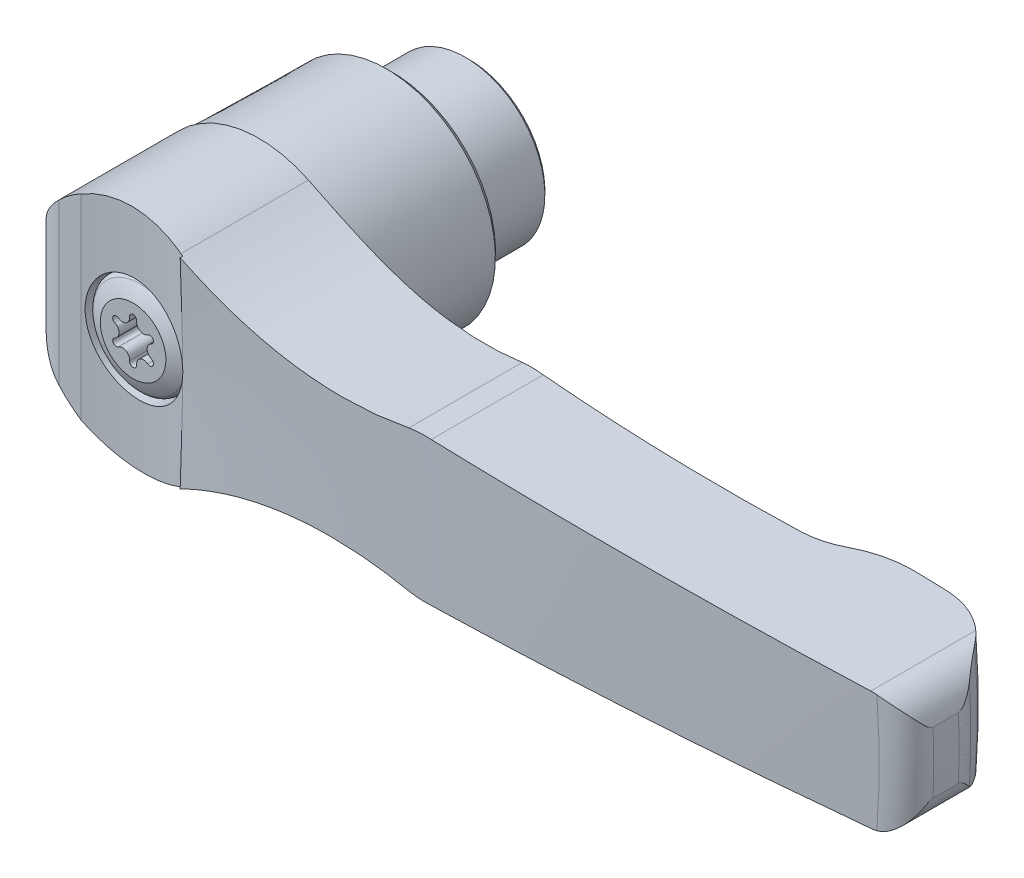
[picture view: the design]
ISO-10303-21;
HEADER;
FILE_DESCRIPTION(('STEP AP214'),'2;1');
FILE_NAME('part.step','',(''),(''),'','','');
FILE_SCHEMA(('AUTOMOTIVE_DESIGN { 1 0 10303 214 1 1 1 1 }'));
ENDSEC;
DATA;
#1=APPLICATION_CONTEXT('core data for automotive mechanical design processes');
#2=APPLICATION_PROTOCOL_DEFINITION('international standard','automotive_design',2000,#1);
#3=PRODUCT_CONTEXT('',#1,'mechanical');
#4=PRODUCT('Part','Part','',(#3));
#5=PRODUCT_RELATED_PRODUCT_CATEGORY('part','',(#4));
#6=PRODUCT_DEFINITION_FORMATION('','',#4);
#7=PRODUCT_DEFINITION_CONTEXT('part definition',#1,'design');
#8=PRODUCT_DEFINITION('design','',#6,#7);
#9=PRODUCT_DEFINITION_SHAPE('','',#8);
#10=(LENGTH_UNIT() NAMED_UNIT(*) SI_UNIT(.MILLI.,.METRE.));
#11=(NAMED_UNIT(*) PLANE_ANGLE_UNIT() SI_UNIT($,.RADIAN.));
#12=(NAMED_UNIT(*) SI_UNIT($,.STERADIAN.) SOLID_ANGLE_UNIT());
#13=UNCERTAINTY_MEASURE_WITH_UNIT(LENGTH_MEASURE(1.E-05),#10,'distance_accuracy_value','');
#14=(GEOMETRIC_REPRESENTATION_CONTEXT(3) GLOBAL_UNCERTAINTY_ASSIGNED_CONTEXT((#13)) GLOBAL_UNIT_ASSIGNED_CONTEXT((#10,
#11,#12)) REPRESENTATION_CONTEXT('',''));
#15=CARTESIAN_POINT('',(0.,0.,0.));
#16=DIRECTION('',(0.,0.,1.));
#17=DIRECTION('',(1.,0.,0.));
#18=AXIS2_PLACEMENT_3D('',#15,#16,#17);
#19=CARTESIAN_POINT('',(0.,0.,28.6698930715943));
#20=DIRECTION('',(0.,0.,1.));
#21=DIRECTION('',(0.,-1.,0.));
#22=AXIS2_PLACEMENT_3D('',#19,#20,#21);
#23=CONICAL_SURFACE('',#22,4.38770360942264,0.0279252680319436);
#24=CARTESIAN_POINT('',(0.,0.,28.6701538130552));
#25=DIRECTION('',(0.,0.,-1.));
#26=DIRECTION('',(0.,1.,0.));
#27=AXIS2_PLACEMENT_3D('',#24,#25,#26);
#28=CIRCLE('',#27,4.38771089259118);
#29=CARTESIAN_POINT('',(4.37640128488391,0.314814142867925,28.6698627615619));
#30=VERTEX_POINT('',#29);
#31=CARTESIAN_POINT('',(4.37640128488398,-0.314814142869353,28.6698627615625));
#32=VERTEX_POINT('',#31);
#33=EDGE_CURVE('E681',#30,#32,#28,.T.);
#34=ORIENTED_EDGE('',*,*,#33,.F.);
#35=CARTESIAN_POINT('',(4.37638813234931,0.314810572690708,28.6696312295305));
#36=CARTESIAN_POINT('',(4.36759225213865,0.436746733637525,28.66825751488));
#37=CARTESIAN_POINT('',(4.35365143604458,0.558298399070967,28.666073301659));
#38=CARTESIAN_POINT('',(4.31565104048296,0.799759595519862,28.6601580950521));
#39=CARTESIAN_POINT('',(4.29159247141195,0.919669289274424,28.6564272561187));
#40=CARTESIAN_POINT('',(4.23356084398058,1.15685508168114,28.6474980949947));
#41=CARTESIAN_POINT('',(4.19959976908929,1.27413418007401,28.6423015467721));
#42=CARTESIAN_POINT('',(4.1220143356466,1.50538038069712,28.6305521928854));
#43=CARTESIAN_POINT('',(4.07838997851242,1.61934748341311,28.6239993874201));
#44=CARTESIAN_POINT('',(3.9818019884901,1.84317559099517,28.6096750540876));
#45=CARTESIAN_POINT('',(3.92883814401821,1.95303650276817,28.6019034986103));
#46=CARTESIAN_POINT('',(3.81394032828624,2.16793056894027,28.5852999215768));
#47=CARTESIAN_POINT('',(3.75200305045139,2.2729619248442,28.5764675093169));
#48=CARTESIAN_POINT('',(3.61964681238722,2.4773951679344,28.5579277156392));
#49=CARTESIAN_POINT('',(3.5492312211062,2.57679926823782,28.5482206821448));
#50=CARTESIAN_POINT('',(3.40037126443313,2.76938620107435,28.5281177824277));
#51=CARTESIAN_POINT('',(3.32192391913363,2.86256670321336,28.5177216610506));
#52=CARTESIAN_POINT('',(3.15690159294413,3.04277004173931,28.4963587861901));
#53=CARTESIAN_POINT('',(3.07026568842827,3.12973662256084,28.485388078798));
#54=CARTESIAN_POINT('',(2.88998825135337,3.29610688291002,28.4631610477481));
#55=CARTESIAN_POINT('',(2.7963441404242,3.37550775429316,28.4519046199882));
#56=CARTESIAN_POINT('',(2.60274956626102,3.52615287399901,28.4293219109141));
#57=CARTESIAN_POINT('',(2.50280041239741,3.59739880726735,28.4179956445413));
#58=CARTESIAN_POINT('',(2.29723122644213,3.7312887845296,28.3954704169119));
#59=CARTESIAN_POINT('',(2.19160910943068,3.79392963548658,28.384271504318));
#60=CARTESIAN_POINT('',(1.97464335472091,3.91058078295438,28.3621157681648));
#61=CARTESIAN_POINT('',(1.86326268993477,3.96452269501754,28.3511613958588));
#62=CARTESIAN_POINT('',(1.63625749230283,4.06283483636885,28.3297617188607));
#63=CARTESIAN_POINT('',(1.52063139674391,4.10720149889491,28.319316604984));
#64=CARTESIAN_POINT('',(1.28603822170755,4.18599718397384,28.2991083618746));
#65=CARTESIAN_POINT('',(1.16707260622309,4.22043048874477,28.2893449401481));
#66=CARTESIAN_POINT('',(0.926553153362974,4.27913923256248,28.2706331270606));
#67=CARTESIAN_POINT('',(0.804998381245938,4.30341093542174,28.2616850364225));
#68=CARTESIAN_POINT('',(0.56050926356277,4.34153901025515,28.2447454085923));
#69=CARTESIAN_POINT('',(0.437579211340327,4.35542170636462,28.2367514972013));
#70=CARTESIAN_POINT('',(0.190912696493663,4.37277111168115,28.221778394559));
#71=CARTESIAN_POINT('',(0.067175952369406,4.37623396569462,28.2147995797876));
#72=CARTESIAN_POINT('',(-0.303814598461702,4.37087373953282,28.1954907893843));
#73=CARTESIAN_POINT('',(-0.551121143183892,4.34634416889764,28.1847695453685));
#74=CARTESIAN_POINT('',(-1.03650636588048,4.2562142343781,28.1678211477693));
#75=CARTESIAN_POINT('',(-1.27463404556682,4.19087822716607,28.1615656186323));
#76=CARTESIAN_POINT('',(-1.73666742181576,4.02119102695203,28.1530588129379));
#77=CARTESIAN_POINT('',(-1.96057336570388,3.91684051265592,28.1508074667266));
#78=CARTESIAN_POINT('',(-2.38718935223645,3.67236312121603,28.1495611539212));
#79=CARTESIAN_POINT('',(-2.58994945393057,3.53232357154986,28.1505583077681));
#80=CARTESIAN_POINT('',(-2.96915676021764,3.22029180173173,28.1547714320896));
#81=CARTESIAN_POINT('',(-3.14560364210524,3.04829918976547,28.1579874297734));
#82=CARTESIAN_POINT('',(-3.46742933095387,2.67692052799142,28.1654937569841));
#83=CARTESIAN_POINT('',(-3.61276071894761,2.4774934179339,28.169785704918));
#84=CARTESIAN_POINT('',(-3.86788705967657,2.05707167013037,28.1783049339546));
#85=CARTESIAN_POINT('',(-3.97768202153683,1.8360770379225,28.1825322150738));
#86=CARTESIAN_POINT('',(-4.15862712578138,1.37869612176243,28.1899517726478));
#87=CARTESIAN_POINT('',(-4.22976508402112,1.14230501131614,28.1931437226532));
#88=CARTESIAN_POINT('',(-4.33129348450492,0.660912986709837,28.1978079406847));
#89=CARTESIAN_POINT('',(-4.36168448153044,0.415912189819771,28.1992802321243));
#90=CARTESIAN_POINT('',(-4.38082304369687,-0.0752514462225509,28.2001998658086));
#91=CARTESIAN_POINT('',(-4.36964881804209,-0.321411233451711,28.1996510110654));
#92=CARTESIAN_POINT('',(-4.30615469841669,-0.808352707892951,28.1966493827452));
#93=CARTESIAN_POINT('',(-4.25383484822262,-1.04913440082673,28.1941966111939));
#94=CARTESIAN_POINT('',(-4.10958617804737,-1.51838976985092,28.1879011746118));
#95=CARTESIAN_POINT('',(-4.01767438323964,-1.74686868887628,28.1840591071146));
#96=CARTESIAN_POINT('',(-3.79686828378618,-2.18518682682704,28.1758300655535));
#97=CARTESIAN_POINT('',(-3.66797348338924,-2.39502579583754,28.1714430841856));
#98=CARTESIAN_POINT('',(-3.37658641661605,-2.79052813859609,28.1631865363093));
#99=CARTESIAN_POINT('',(-3.21403231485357,-2.97614597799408,28.1593179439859));
#100=CARTESIAN_POINT('',(-2.86008476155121,-3.31751162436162,28.1532728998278));
#101=CARTESIAN_POINT('',(-2.66869127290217,-3.47325939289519,28.1510964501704));
#102=CARTESIAN_POINT('',(-2.26239270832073,-3.75056183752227,28.1495386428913));
#103=CARTESIAN_POINT('',(-2.04747487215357,-3.87209782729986,28.1501588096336));
#104=CARTESIAN_POINT('',(-1.60034041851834,-4.07742306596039,28.1550942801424));
#105=CARTESIAN_POINT('',(-1.36812412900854,-4.1612130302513,28.1594095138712));
#106=CARTESIAN_POINT('',(-0.893482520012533,-4.28860890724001,28.1722769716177));
#107=CARTESIAN_POINT('',(-0.651074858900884,-4.33228155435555,28.1808221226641));
#108=CARTESIAN_POINT('',(-0.162434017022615,-4.3784984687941,28.2022857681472));
#109=CARTESIAN_POINT('',(0.0837991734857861,-4.38104263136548,28.2152042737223));
#110=CARTESIAN_POINT('',(0.450557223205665,-4.35410663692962,28.2375786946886));
#111=CARTESIAN_POINT('',(0.572490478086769,-4.33997502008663,28.2455451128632));
#112=CARTESIAN_POINT('',(0.814673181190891,-4.3015689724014,28.262388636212));
#113=CARTESIAN_POINT('',(0.934923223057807,-4.27729821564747,28.271265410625));
#114=CARTESIAN_POINT('',(1.17294984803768,-4.21878135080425,28.2898222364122));
#115=CARTESIAN_POINT('',(1.2907254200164,-4.1845312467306,28.2995026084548));
#116=CARTESIAN_POINT('',(1.52290562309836,-4.10632591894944,28.319522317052));
#117=CARTESIAN_POINT('',(1.63731144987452,-4.0623741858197,28.3298614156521));
#118=CARTESIAN_POINT('',(1.86270011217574,-3.9647705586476,28.3511080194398));
#119=CARTESIAN_POINT('',(1.9736573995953,-3.91106034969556,28.3620186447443));
#120=CARTESIAN_POINT('',(2.19059187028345,-3.79452642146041,28.3841641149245));
#121=CARTESIAN_POINT('',(2.29657083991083,-3.73170600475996,28.3953988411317));
#122=CARTESIAN_POINT('',(2.50289007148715,-3.59735327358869,28.4180046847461));
#123=CARTESIAN_POINT('',(2.60322844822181,-3.52581807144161,28.4293758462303));
#124=CARTESIAN_POINT('',(2.79749365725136,-3.37457510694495,28.4520406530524));
#125=CARTESIAN_POINT('',(2.89142283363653,-3.29487035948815,28.4633343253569));
#126=CARTESIAN_POINT('',(3.07268721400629,-3.12741243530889,28.4856903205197));
#127=CARTESIAN_POINT('',(3.15998858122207,-3.03962244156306,28.4967512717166));
#128=CARTESIAN_POINT('',(3.32684040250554,-2.85696457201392,28.5183655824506));
#129=CARTESIAN_POINT('',(3.40639373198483,-2.76209934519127,28.5289191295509));
#130=CARTESIAN_POINT('',(3.55727025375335,-2.5658447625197,28.5493194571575));
#131=CARTESIAN_POINT('',(3.62858698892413,-2.46445038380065,28.559165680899));
#132=CARTESIAN_POINT('',(3.76236832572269,-2.25595422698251,28.577935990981));
#133=CARTESIAN_POINT('',(3.82483631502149,-2.1488546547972,28.5868604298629));
#134=CARTESIAN_POINT('',(3.94027260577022,-1.9300734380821,28.6035728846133));
#135=CARTESIAN_POINT('',(3.99327497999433,-1.8184100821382,28.6113649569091));
#136=CARTESIAN_POINT('',(4.08964142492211,-1.590970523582,28.6256827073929));
#137=CARTESIAN_POINT('',(4.13300929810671,-1.47519596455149,28.6322088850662));
#138=CARTESIAN_POINT('',(4.20974206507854,-1.24050512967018,28.6438484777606));
#139=CARTESIAN_POINT('',(4.24312178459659,-1.12159379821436,28.6489639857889));
#140=CARTESIAN_POINT('',(4.29969149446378,-0.881370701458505,28.6576807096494));
#141=CARTESIAN_POINT('',(4.32288741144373,-0.760060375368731,28.6612828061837));
#142=CARTESIAN_POINT('',(4.34882803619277,-0.584348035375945,28.6653234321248));
#143=CARTESIAN_POINT('',(4.35574888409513,-0.530548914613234,28.6664035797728));
#144=CARTESIAN_POINT('',(4.36757549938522,-0.422796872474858,28.6682515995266));
#145=CARTESIAN_POINT('',(4.37248393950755,-0.368844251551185,28.6690198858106));
#146=CARTESIAN_POINT('',(4.37638813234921,-0.314810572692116,28.6696312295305));
#147=B_SPLINE_CURVE_WITH_KNOTS('',3,(#35,#36,#37,#38,#39,#40,#41,#42,#43,#44,#45,#46,#47,#48,
#49,#50,#51,#52,#53,#54,#55,#56,#57,#58,#59,#60,#61,#62,#63,#64,#65,#66,#67,#68,#69,#70,#71,#72,
#73,#74,#75,#76,#77,#78,#79,#80,#81,#82,#83,#84,#85,#86,#87,#88,#89,#90,#91,#92,#93,#94,#95,#96,
#97,#98,#99,#100,#101,#102,#103,#104,#105,#106,#107,#108,#109,#110,#111,#112,#113,#114,#115,
#116,#117,#118,#119,#120,#121,#122,#123,#124,#125,#126,#127,#128,#129,#130,#131,#132,#133,#134,
#135,#136,#137,#138,#139,#140,#141,#142,#143,#144,#145,#146),.UNSPECIFIED.,.F.,.F.,(4,2,2,2,2,2,
2,2,2,2,2,2,2,2,2,2,2,2,2,2,2,2,2,2,2,2,2,2,2,2,2,2,2,2,2,2,2,2,2,2,2,2,2,2,2,2,2,2,2,2,2,2,2,2,
2,4),(0.,0.366665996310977,0.733295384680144,1.09948292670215,1.46567041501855,1.83186620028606,
2.19819726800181,2.56438324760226,2.93070558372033,3.30000778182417,3.66944652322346,
4.03880879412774,4.40830775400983,4.78058304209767,5.15299676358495,5.525249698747,
5.89763938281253,6.26908226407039,6.64066255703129,7.38300471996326,8.12058694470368,
8.85815633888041,9.5939380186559,10.3297287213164,11.0666328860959,11.803536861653,
12.540672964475,13.2777990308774,14.0135388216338,14.7492778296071,15.484700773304,
16.220133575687,16.9569296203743,17.6937266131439,18.4309252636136,19.1681099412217,
19.9040660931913,20.6400241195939,21.0086915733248,21.3772255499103,21.7459073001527,
22.1144566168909,22.485285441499,22.855980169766,23.2267980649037,23.59747960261,
23.969941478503,24.342264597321,24.7148776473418,25.08734765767,25.4584486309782,
25.8294028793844,26.1998037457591,26.569988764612,26.732716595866,26.8952275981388),.UNSPECIFIED.);
#148=EDGE_CURVE('E1294',#30,#32,#147,.T.);
#149=ORIENTED_EDGE('',*,*,#148,.T.);
#150=EDGE_LOOP('',(#34,#149));
#151=FACE_BOUND('',#150,.T.);
#152=CARTESIAN_POINT('',(0.,0.,25.5));
#153=DIRECTION('',(0.,0.,-1.));
#154=DIRECTION('',(-1.,0.,0.));
#155=AXIS2_PLACEMENT_3D('',#152,#153,#154);
#156=CIRCLE('',#155,4.29916047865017);
#157=CARTESIAN_POINT('',(-4.29916047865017,0.,25.5));
#158=VERTEX_POINT('',#157);
#159=EDGE_CURVE('E9',#158,#158,#156,.F.);
#160=ORIENTED_EDGE('',*,*,#159,.F.);
#161=EDGE_LOOP('',(#160));
#162=FACE_BOUND('',#161,.T.);
#163=ADVANCED_FACE('F14',(#151,#162),#23,.F.);
#164=CARTESIAN_POINT('',(6.45,0.,0.));
#165=DIRECTION('',(0.,0.,1.));
#166=DIRECTION('',(0.,-1.,0.));
#167=AXIS2_PLACEMENT_3D('',#164,#165,#166);
#168=PLANE('',#167);
#169=CARTESIAN_POINT('',(0.,0.,0.));
#170=DIRECTION('',(0.,0.,1.));
#171=DIRECTION('',(0.,-1.,0.));
#172=AXIS2_PLACEMENT_3D('',#169,#170,#171);
#173=CIRCLE('',#172,4.5);
#174=CARTESIAN_POINT('',(0.,-4.5,0.));
#175=VERTEX_POINT('',#174);
#176=EDGE_CURVE('E23',#175,#175,#173,.T.);
#177=ORIENTED_EDGE('',*,*,#176,.T.);
#178=EDGE_LOOP('',(#177));
#179=FACE_BOUND('',#178,.T.);
#180=CARTESIAN_POINT('',(0.,0.,0.));
#181=DIRECTION('',(0.,0.,1.));
#182=DIRECTION('',(0.,-1.,0.));
#183=AXIS2_PLACEMENT_3D('',#180,#181,#182);
#184=CIRCLE('',#183,6.45000000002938);
#185=CARTESIAN_POINT('',(0.,-6.45000000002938,0.));
#186=VERTEX_POINT('',#185);
#187=EDGE_CURVE('E385',#186,#186,#184,.T.);
#188=ORIENTED_EDGE('',*,*,#187,.F.);
#189=EDGE_LOOP('',(#188));
#190=FACE_BOUND('',#189,.T.);
#191=ADVANCED_FACE('F400',(#179,#190),#168,.F.);
#192=CARTESIAN_POINT('',(0.,0.,0.299999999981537));
#193=DIRECTION('',(0.,0.,1.));
#194=DIRECTION('',(0.,-1.,0.));
#195=AXIS2_PLACEMENT_3D('',#192,#193,#194);
#196=CONICAL_SURFACE('',#195,6.75000000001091,0.785398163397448);
#197=CARTESIAN_POINT('',(0.,0.,0.3));
#198=DIRECTION('',(0.,0.,1.));
#199=DIRECTION('',(0.,-1.,0.));
#200=AXIS2_PLACEMENT_3D('',#197,#198,#199);
#201=CIRCLE('',#200,6.75);
#202=CARTESIAN_POINT('',(0.,-6.75,0.3));
#203=VERTEX_POINT('',#202);
#204=EDGE_CURVE('E381',#203,#203,#201,.T.);
#205=ORIENTED_EDGE('',*,*,#204,.F.);
#206=EDGE_LOOP('',(#205));
#207=FACE_BOUND('',#206,.T.);
#208=ORIENTED_EDGE('',*,*,#187,.T.);
#209=EDGE_LOOP('',(#208));
#210=FACE_BOUND('',#209,.T.);
#211=ADVANCED_FACE('F707',(#207,#210),#196,.T.);
#212=CARTESIAN_POINT('',(0.,0.,0.));
#213=DIRECTION('',(0.,0.,1.));
#214=DIRECTION('',(0.,-1.,0.));
#215=AXIS2_PLACEMENT_3D('',#212,#213,#214);
#216=CYLINDRICAL_SURFACE('',#215,6.75);
#217=CARTESIAN_POINT('',(0.,0.,6.5));
#218=DIRECTION('',(0.,0.,1.));
#219=DIRECTION('',(0.,-1.,0.));
#220=AXIS2_PLACEMENT_3D('',#217,#218,#219);
#221=CIRCLE('',#220,6.75);
#222=CARTESIAN_POINT('',(0.,-6.75,6.5));
#223=VERTEX_POINT('',#222);
#224=EDGE_CURVE('E384',#223,#223,#221,.F.);
#225=ORIENTED_EDGE('',*,*,#224,.T.);
#226=EDGE_LOOP('',(#225));
#227=FACE_BOUND('',#226,.T.);
#228=ORIENTED_EDGE('',*,*,#204,.T.);
#229=EDGE_LOOP('',(#228));
#230=FACE_BOUND('',#229,.T.);
#231=ADVANCED_FACE('F1124',(#227,#230),#216,.T.);
#232=CARTESIAN_POINT('',(8.75,0.,6.5));
#233=DIRECTION('',(0.,0.,1.));
#234=DIRECTION('',(0.,-1.,0.));
#235=AXIS2_PLACEMENT_3D('',#232,#233,#234);
#236=PLANE('',#235);
#237=CARTESIAN_POINT('',(0.,0.,6.5));
#238=DIRECTION('',(0.,0.,1.));
#239=DIRECTION('',(0.,-1.,0.));
#240=AXIS2_PLACEMENT_3D('',#237,#238,#239);
#241=CIRCLE('',#240,8.75);
#242=CARTESIAN_POINT('',(0.,-8.75,6.5));
#243=VERTEX_POINT('',#242);
#244=EDGE_CURVE('E684',#243,#243,#241,.T.);
#245=ORIENTED_EDGE('',*,*,#244,.F.);
#246=EDGE_LOOP('',(#245));
#247=FACE_BOUND('',#246,.T.);
#248=ORIENTED_EDGE('',*,*,#224,.F.);
#249=EDGE_LOOP('',(#248));
#250=FACE_BOUND('',#249,.T.);
#251=ADVANCED_FACE('F1116',(#247,#250),#236,.F.);
#252=CARTESIAN_POINT('',(0.,0.,7.));
#253=DIRECTION('',(0.,0.,1.));
#254=DIRECTION('',(0.,-1.,0.));
#255=AXIS2_PLACEMENT_3D('',#252,#253,#254);
#256=CONICAL_SURFACE('',#255,9.25,0.785398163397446);
#257=CARTESIAN_POINT('',(0.,0.,7.));
#258=DIRECTION('',(0.,0.,1.));
#259=DIRECTION('',(0.,-1.,0.));
#260=AXIS2_PLACEMENT_3D('',#257,#258,#259);
#261=CIRCLE('',#260,9.25);
#262=CARTESIAN_POINT('',(0.,-9.25,6.99999999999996));
#263=VERTEX_POINT('',#262);
#264=EDGE_CURVE('E374',#263,#263,#261,.T.);
#265=ORIENTED_EDGE('',*,*,#264,.F.);
#266=EDGE_LOOP('',(#265));
#267=FACE_BOUND('',#266,.T.);
#268=ORIENTED_EDGE('',*,*,#244,.T.);
#269=EDGE_LOOP('',(#268));
#270=FACE_BOUND('',#269,.T.);
#271=ADVANCED_FACE('F664',(#267,#270),#256,.T.);
#272=CARTESIAN_POINT('',(-9.25,-19.1,7.));
#273=DIRECTION('',(-0.999862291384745,0.,-0.0165951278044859));
#274=DIRECTION('',(0.0165951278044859,0.,-0.999862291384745));
#275=AXIS2_PLACEMENT_3D('',#272,#273,#274);
#276=PLANE('',#275);
#277=CARTESIAN_POINT('',(1.01243252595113E-13,0.,-550.315755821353));
#278=DIRECTION('',(-0.999862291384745,0.,-0.0165951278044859));
#279=DIRECTION('',(-0.0165951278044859,0.,0.999862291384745));
#280=AXIS2_PLACEMENT_3D('',#277,#278,#279);
#281=ELLIPSE('',#280,575.470108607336,9.55);
#282=CARTESIAN_POINT('',(-9.4295477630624,1.51199503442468,17.8178159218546));
#283=VERTEX_POINT('',#282);
#284=CARTESIAN_POINT('',(-9.54958687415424,0.0888286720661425,25.0502146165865));
#285=VERTEX_POINT('',#284);
#286=EDGE_CURVE('E637',#283,#285,#281,.F.);
#287=ORIENTED_EDGE('',*,*,#286,.F.);
#288=CARTESIAN_POINT('',(-9.4295477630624,1.51199503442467,17.8178159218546));
#289=CARTESIAN_POINT('',(-9.42944136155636,1.26003673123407,17.8114051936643));
#290=CARTESIAN_POINT('',(-9.42936147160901,1.00805803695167,17.8065917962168));
#291=CARTESIAN_POINT('',(-9.42925471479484,0.504059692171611,17.8001596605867));
#292=CARTESIAN_POINT('',(-9.42922784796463,0.252040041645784,17.7985409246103));
#293=CARTESIAN_POINT('',(-9.42922749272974,0.,17.798519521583));
#294=B_SPLINE_CURVE_WITH_KNOTS('',3,(#288,#289,#290,#291,#292,#293),.UNSPECIFIED.,.F.,.F.,(4,2,
4),(0.,0.75607402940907,1.51214858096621),.UNSPECIFIED.);
#295=CARTESIAN_POINT('',(-9.42922749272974,0.,17.798519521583));
#296=VERTEX_POINT('',#295);
#297=EDGE_CURVE('E380',#283,#296,#294,.T.);
#298=ORIENTED_EDGE('',*,*,#297,.T.);
#299=CARTESIAN_POINT('',(-9.42922749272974,0.,17.798519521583));
#300=CARTESIAN_POINT('',(-9.42922784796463,-0.252040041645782,17.7985409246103));
#301=CARTESIAN_POINT('',(-9.42925471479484,-0.504059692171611,17.8001596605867));
#302=CARTESIAN_POINT('',(-9.42936147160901,-1.00805803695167,17.8065917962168));
#303=CARTESIAN_POINT('',(-9.42944136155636,-1.26003673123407,17.8114051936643));
#304=CARTESIAN_POINT('',(-9.4295477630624,-1.51199503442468,17.8178159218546));
#305=B_SPLINE_CURVE_WITH_KNOTS('',3,(#299,#300,#301,#302,#303,#304),.UNSPECIFIED.,.F.,.F.,(4,2,
4),(0.,0.756074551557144,1.51214858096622),.UNSPECIFIED.);
#306=CARTESIAN_POINT('',(-9.4295477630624,-1.5119950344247,17.8178159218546));
#307=VERTEX_POINT('',#306);
#308=EDGE_CURVE('E675',#296,#307,#305,.T.);
#309=ORIENTED_EDGE('',*,*,#308,.T.);
#310=CARTESIAN_POINT('',(1.01243252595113E-13,0.,-550.315755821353));
#311=DIRECTION('',(-0.999862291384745,0.,-0.0165951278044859));
#312=DIRECTION('',(-0.0165951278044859,0.,0.999862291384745));
#313=AXIS2_PLACEMENT_3D('',#310,#311,#312);
#314=ELLIPSE('',#313,575.470108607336,9.55);
#315=CARTESIAN_POINT('',(-9.54958687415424,-0.0888286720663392,25.0502146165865));
#316=VERTEX_POINT('',#315);
#317=EDGE_CURVE('E1256',#316,#307,#314,.F.);
#318=ORIENTED_EDGE('',*,*,#317,.F.);
#319=DIRECTION('',(0.,-1.,0.));
#320=VECTOR('',#319,1.);
#321=CARTESIAN_POINT('',(-9.54958687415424,-19.1,25.0502146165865));
#322=LINE('',#321,#320);
#323=EDGE_CURVE('E375',#285,#316,#322,.T.);
#324=ORIENTED_EDGE('',*,*,#323,.F.);
#325=EDGE_LOOP('',(#287,#298,#309,#318,#324));
#326=FACE_BOUND('',#325,.T.);
#327=ADVANCED_FACE('F659',(#326),#276,.T.);
#328=CARTESIAN_POINT('',(-6.69999999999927,-19.1,28.0962476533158));
#329=DIRECTION('',(-0.0601647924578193,0.,0.998188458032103));
#330=DIRECTION('',(-0.998188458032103,0.,-0.0601647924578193));
#331=AXIS2_PLACEMENT_3D('',#328,#329,#330);
#332=PLANE('',#331);
#333=CARTESIAN_POINT('',(0.,0.,28.500083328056));
#334=DIRECTION('',(-0.0601647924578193,0.,0.998188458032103));
#335=DIRECTION('',(0.998188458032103,0.,0.0601647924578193));
#336=AXIS2_PLACEMENT_3D('',#333,#334,#335);
#337=ELLIPSE('',#336,9.56733162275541,9.55);
#338=CARTESIAN_POINT('',(-6.69999999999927,6.80532879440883,28.0962476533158));
#339=VERTEX_POINT('',#338);
#340=CARTESIAN_POINT('',(-4.70000000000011,8.31339280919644,28.2167956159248));
#341=VERTEX_POINT('',#340);
#342=EDGE_CURVE('E648',#339,#341,#337,.F.);
#343=ORIENTED_EDGE('',*,*,#342,.F.);
#344=DIRECTION('',(0.,-1.,0.));
#345=VECTOR('',#344,1.);
#346=CARTESIAN_POINT('',(-6.69999999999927,-19.1,28.0962476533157));
#347=LINE('',#346,#345);
#348=CARTESIAN_POINT('',(-6.69999999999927,-6.80532879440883,28.0962476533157));
#349=VERTEX_POINT('',#348);
#350=EDGE_CURVE('E378',#349,#339,#347,.F.);
#351=ORIENTED_EDGE('',*,*,#350,.F.);
#352=CARTESIAN_POINT('',(0.,0.,28.500083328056));
#353=DIRECTION('',(-0.0601647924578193,0.,0.998188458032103));
#354=DIRECTION('',(0.998188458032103,0.,0.0601647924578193));
#355=AXIS2_PLACEMENT_3D('',#352,#353,#354);
#356=ELLIPSE('',#355,9.56733162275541,9.55);
#357=CARTESIAN_POINT('',(-4.70000000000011,-8.31339280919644,28.2167956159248));
#358=VERTEX_POINT('',#357);
#359=EDGE_CURVE('E1262',#358,#349,#356,.F.);
#360=ORIENTED_EDGE('',*,*,#359,.F.);
#361=DIRECTION('',(0.,-1.,0.));
#362=VECTOR('',#361,1.);
#363=CARTESIAN_POINT('',(-4.70000000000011,-19.1,28.2167956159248));
#364=LINE('',#363,#362);
#365=EDGE_CURVE('E1233',#358,#341,#364,.F.);
#366=ORIENTED_EDGE('',*,*,#365,.T.);
#367=EDGE_LOOP('',(#343,#351,#360,#366));
#368=FACE_BOUND('',#367,.T.);
#369=ADVANCED_FACE('F654',(#368),#332,.T.);
#370=CARTESIAN_POINT('',(-6.55,-19.1,25.1));
#371=DIRECTION('',(0.,-1.,0.));
#372=DIRECTION('',(1.,0.,0.));
#373=AXIS2_PLACEMENT_3D('',#370,#371,#372);
#374=CYLINDRICAL_SURFACE('',#373,3.);
#375=CARTESIAN_POINT('',(-9.55,0.,25.1));
#376=CARTESIAN_POINT('',(-9.55,3.47671001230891E-08,25.1001435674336));
#377=CARTESIAN_POINT('',(-9.54999998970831,0.000424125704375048,25.1002871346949));
#378=CARTESIAN_POINT('',(-9.54999993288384,0.0013735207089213,25.1006836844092));
#379=CARTESIAN_POINT('',(-9.54999986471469,0.00172979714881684,25.1009366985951));
#380=CARTESIAN_POINT('',(-9.54999948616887,0.00320746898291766,25.1018926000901));
#381=CARTESIAN_POINT('',(-9.54999896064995,0.00456206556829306,25.102594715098));
#382=CARTESIAN_POINT('',(-9.54999589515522,0.00980280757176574,25.1053821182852));
#383=CARTESIAN_POINT('',(-9.54999142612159,0.0134222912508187,25.1074690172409));
#384=CARTESIAN_POINT('',(-9.54984305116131,0.0944102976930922,25.154064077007));
#385=CARTESIAN_POINT('',(-9.54871139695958,0.175284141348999,25.1985505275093));
#386=CARTESIAN_POINT('',(-9.5444403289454,0.336150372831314,25.2880374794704));
#387=CARTESIAN_POINT('',(-9.5412756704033,0.41611862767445,25.3330373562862));
#388=CARTESIAN_POINT('',(-9.53306454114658,0.573610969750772,25.4212745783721));
#389=CARTESIAN_POINT('',(-9.52809098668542,0.651117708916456,25.464516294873));
#390=CARTESIAN_POINT('',(-9.51627073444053,0.805689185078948,25.5506915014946));
#391=CARTESIAN_POINT('',(-9.50943037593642,0.882754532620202,25.5936255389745));
#392=CARTESIAN_POINT('',(-9.48445472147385,1.12996192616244,25.7310467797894));
#393=CARTESIAN_POINT('',(-9.46266049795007,1.30002022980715,25.8251235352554));
#394=CARTESIAN_POINT('',(-9.40954494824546,1.64104493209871,26.0124493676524));
#395=CARTESIAN_POINT('',(-9.37814208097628,1.81200629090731,26.1056840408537));
#396=CARTESIAN_POINT('',(-9.31379295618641,2.11521576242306,26.2693440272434));
#397=CARTESIAN_POINT('',(-9.28274317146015,2.24761769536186,26.3402306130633));
#398=CARTESIAN_POINT('',(-9.21483141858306,2.51155601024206,26.4801106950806));
#399=CARTESIAN_POINT('',(-9.1779819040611,2.64309363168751,26.5491078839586));
#400=CARTESIAN_POINT('',(-9.09908481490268,2.90297154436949,26.6837096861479));
#401=CARTESIAN_POINT('',(-9.05714892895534,3.03132520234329,26.7493538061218));
#402=CARTESIAN_POINT('',(-8.96742994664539,3.2872629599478,26.8782580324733));
#403=CARTESIAN_POINT('',(-8.9196441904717,3.41484668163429,26.941517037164));
#404=CARTESIAN_POINT('',(-8.79975726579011,3.71503866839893,27.087578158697));
#405=CARTESIAN_POINT('',(-8.7251146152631,3.88723290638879,27.1691685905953));
#406=CARTESIAN_POINT('',(-8.56416880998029,4.2300744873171,27.3261666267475));
#407=CARTESIAN_POINT('',(-8.4778157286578,4.4007116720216,27.4015454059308));
#408=CARTESIAN_POINT('',(-8.28951988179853,4.74622896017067,27.5472095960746));
#409=CARTESIAN_POINT('',(-8.18707228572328,4.92098334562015,27.6171448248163));
#410=CARTESIAN_POINT('',(-7.96936829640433,5.26623550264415,27.7460103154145));
#411=CARTESIAN_POINT('',(-7.85413022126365,5.43673894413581,27.8049559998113));
#412=CARTESIAN_POINT('',(-7.64561682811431,5.72441551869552,27.8943766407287));
#413=CARTESIAN_POINT('',(-7.55551597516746,5.84286462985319,27.9281691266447));
#414=CARTESIAN_POINT('',(-7.36878441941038,6.07666798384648,27.9877671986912));
#415=CARTESIAN_POINT('',(-7.2721523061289,6.19202155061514,28.0135710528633));
#416=CARTESIAN_POINT('',(-7.0736511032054,6.41781298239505,28.0556686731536));
#417=CARTESIAN_POINT('',(-6.97184621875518,6.52828924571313,28.0720576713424));
#418=CARTESIAN_POINT('',(-6.76252380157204,6.74488219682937,28.0943126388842));
#419=CARTESIAN_POINT('',(-6.65500601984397,6.85099869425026,28.1001781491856));
#420=CARTESIAN_POINT('',(-6.46343795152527,7.03128991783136,28.0998606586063));
#421=CARTESIAN_POINT('',(-6.38048824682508,7.10664323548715,28.0963952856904));
#422=CARTESIAN_POINT('',(-6.21235451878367,7.25407788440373,28.0821322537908));
#423=CARTESIAN_POINT('',(-6.12717105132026,7.32616001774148,28.0713364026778));
#424=CARTESIAN_POINT('',(-5.955080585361,7.46671649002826,28.0417159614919));
#425=CARTESIAN_POINT('',(-5.86817218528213,7.53518771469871,28.0228845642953));
#426=CARTESIAN_POINT('',(-5.69355294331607,7.6679866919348,27.9765732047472));
#427=CARTESIAN_POINT('',(-5.60584224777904,7.73231518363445,27.9490947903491));
#428=CARTESIAN_POINT('',(-5.37383569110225,7.8965468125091,27.8640863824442));
#429=CARTESIAN_POINT('',(-5.22954554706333,7.9926221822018,27.7986060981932));
#430=CARTESIAN_POINT('',(-5.01773611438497,8.12600028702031,27.6804530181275));
#431=CARTESIAN_POINT('',(-4.94788689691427,8.1686799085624,27.6377332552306));
#432=CARTESIAN_POINT('',(-4.8104935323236,8.25033380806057,27.5455968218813));
#433=CARTESIAN_POINT('',(-4.74294828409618,8.28930987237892,27.4961834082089));
#434=CARTESIAN_POINT('',(-4.61056271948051,8.36367281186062,27.3903740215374));
#435=CARTESIAN_POINT('',(-4.54574333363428,8.3990341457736,27.3339338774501));
#436=CARTESIAN_POINT('',(-4.42019774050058,8.46577835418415,27.2145781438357));
#437=CARTESIAN_POINT('',(-4.35946970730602,8.4971630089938,27.1516654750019));
#438=CARTESIAN_POINT('',(-4.24293765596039,8.55594777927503,27.0196895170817));
#439=CARTESIAN_POINT('',(-4.18713404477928,8.58334756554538,26.9506257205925));
#440=CARTESIAN_POINT('',(-4.0812939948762,8.63417541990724,26.806889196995));
#441=CARTESIAN_POINT('',(-4.03125694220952,8.65760391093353,26.7322170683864));
#442=CARTESIAN_POINT('',(-3.90083205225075,8.71748250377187,26.5169917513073));
#443=CARTESIAN_POINT('',(-3.82753078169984,8.7496789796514,26.3708197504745));
#444=CARTESIAN_POINT('',(-3.70530262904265,8.80214203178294,26.0667360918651));
#445=CARTESIAN_POINT('',(-3.6563685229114,8.82241214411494,25.9088279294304));
#446=CARTESIAN_POINT('',(-3.58669946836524,8.85095678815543,25.5936337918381));
#447=CARTESIAN_POINT('',(-3.56475897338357,8.8597453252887,25.4366603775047));
#448=CARTESIAN_POINT('',(-3.54590998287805,8.86730708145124,25.1209897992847));
#449=CARTESIAN_POINT('',(-3.54899880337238,8.86608137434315,24.9622928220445));
#450=CARTESIAN_POINT('',(-3.57992840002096,8.85363637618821,24.6492415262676));
#451=CARTESIAN_POINT('',(-3.60753685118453,8.84251088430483,24.4948604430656));
#452=CARTESIAN_POINT('',(-3.686063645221,8.81006376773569,24.1932781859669));
#453=CARTESIAN_POINT('',(-3.73698074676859,8.7887426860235,24.0460766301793));
#454=CARTESIAN_POINT('',(-3.86017848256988,8.73533137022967,23.7625338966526));
#455=CARTESIAN_POINT('',(-3.93251587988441,8.70321249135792,23.6262228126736));
#456=CARTESIAN_POINT('',(-4.09541934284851,8.62774986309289,23.368444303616));
#457=CARTESIAN_POINT('',(-4.18598535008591,8.5844061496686,23.2469768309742));
#458=CARTESIAN_POINT('',(-4.3835634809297,8.48524049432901,23.0191927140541));
#459=CARTESIAN_POINT('',(-4.49088076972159,8.42917584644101,22.9132473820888));
#460=CARTESIAN_POINT('',(-4.71597947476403,8.30533115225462,22.7212884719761));
#461=CARTESIAN_POINT('',(-4.83376196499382,8.23754990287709,22.6352769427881));
#462=CARTESIAN_POINT('',(-5.08355636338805,8.08595728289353,22.4784048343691));
#463=CARTESIAN_POINT('',(-5.21599086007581,8.0013678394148,22.4089779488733));
#464=CARTESIAN_POINT('',(-5.48298659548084,7.82082800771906,22.2923775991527));
#465=CARTESIAN_POINT('',(-5.61754980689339,7.72486647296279,22.2452261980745));
#466=CARTESIAN_POINT('',(-5.84755511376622,7.55137315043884,22.1816811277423));
#467=CARTESIAN_POINT('',(-5.9434498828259,7.47615707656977,22.1603779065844));
#468=CARTESIAN_POINT('',(-6.13329531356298,7.32121517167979,22.1275201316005));
#469=CARTESIAN_POINT('',(-6.22724527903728,7.24148776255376,22.1159690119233));
#470=CARTESIAN_POINT('',(-6.41225725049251,7.07818317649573,22.1017285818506));
#471=CARTESIAN_POINT('',(-6.50332159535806,6.99460925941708,22.0990319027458));
#472=CARTESIAN_POINT('',(-6.68208625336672,6.82403828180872,22.1015760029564));
#473=CARTESIAN_POINT('',(-6.76978559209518,6.73704024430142,22.1068190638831));
#474=CARTESIAN_POINT('',(-6.97625280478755,6.52414074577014,22.1279597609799));
#475=CARTESIAN_POINT('',(-7.09317594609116,6.39678691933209,22.1473193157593));
#476=CARTESIAN_POINT('',(-7.31887069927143,6.13728311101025,22.1978934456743));
#477=CARTESIAN_POINT('',(-7.42763838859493,6.0051308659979,22.2291136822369));
#478=CARTESIAN_POINT('',(-7.63812605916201,5.73508834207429,22.3020440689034));
#479=CARTESIAN_POINT('',(-7.73972802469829,5.59714403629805,22.3438930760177));
#480=CARTESIAN_POINT('',(-7.93408325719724,5.31805820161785,22.4361903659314));
#481=CARTESIAN_POINT('',(-8.02683920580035,5.176917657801,22.4866360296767));
#482=CARTESIAN_POINT('',(-8.24980156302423,4.81751224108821,22.6229913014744));
#483=CARTESIAN_POINT('',(-8.37426162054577,4.59747182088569,22.7136613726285));
#484=CARTESIAN_POINT('',(-8.60363827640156,4.15243763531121,22.9079226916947));
#485=CARTESIAN_POINT('',(-8.70851443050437,3.92743466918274,23.0115399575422));
#486=CARTESIAN_POINT('',(-8.89364636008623,3.48701966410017,23.2222758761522));
#487=CARTESIAN_POINT('',(-8.97496602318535,3.27179358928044,23.3288567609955));
#488=CARTESIAN_POINT('',(-9.12062405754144,2.84045818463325,23.5478797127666));
#489=CARTESIAN_POINT('',(-9.18506623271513,2.62436297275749,23.6602806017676));
#490=CARTESIAN_POINT('',(-9.26410174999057,2.32097248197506,23.820838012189));
#491=CARTESIAN_POINT('',(-9.28537933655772,2.23431431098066,23.8670103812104));
#492=CARTESIAN_POINT('',(-9.32541816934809,2.06082435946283,23.959993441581));
#493=CARTESIAN_POINT('',(-9.34418091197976,1.97399271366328,24.0068037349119));
#494=CARTESIAN_POINT('',(-9.37958405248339,1.79835785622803,24.1019601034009));
#495=CARTESIAN_POINT('',(-9.39617308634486,1.70955070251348,24.1503179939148));
#496=CARTESIAN_POINT('',(-9.42681937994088,1.53158407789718,24.2476394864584));
#497=CARTESIAN_POINT('',(-9.4408711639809,1.44242425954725,24.296604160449));
#498=CARTESIAN_POINT('',(-9.47029095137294,1.23688333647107,24.4098656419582));
#499=CARTESIAN_POINT('',(-9.48476525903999,1.12044890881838,24.4743078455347));
#500=CARTESIAN_POINT('',(-9.50929003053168,0.888497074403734,24.6031447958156));
#501=CARTESIAN_POINT('',(-9.51937783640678,0.772980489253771,24.6675350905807));
#502=CARTESIAN_POINT('',(-9.5345920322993,0.552299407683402,24.790656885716));
#503=CARTESIAN_POINT('',(-9.54009172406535,0.447168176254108,24.8493594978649));
#504=CARTESIAN_POINT('',(-9.54581598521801,0.288015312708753,24.9386824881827));
#505=CARTESIAN_POINT('',(-9.5473054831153,0.233694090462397,24.9692511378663));
#506=CARTESIAN_POINT('',(-9.54933602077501,0.124477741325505,25.0300231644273));
#507=CARTESIAN_POINT('',(-9.54988855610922,0.0695980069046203,25.0602263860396));
#508=CARTESIAN_POINT('',(-9.54999142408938,0.0134216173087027,25.0925303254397));
#509=CARTESIAN_POINT('',(-9.54999589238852,0.00980484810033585,25.0946165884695));
#510=CARTESIAN_POINT('',(-9.54999895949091,0.00456470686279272,25.0974038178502));
#511=CARTESIAN_POINT('',(-9.54999948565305,0.00320907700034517,25.0981064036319));
#512=CARTESIAN_POINT('',(-9.54999986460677,0.00173053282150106,25.0990629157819));
#513=CARTESIAN_POINT('',(-9.54999993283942,0.00137409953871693,25.0993160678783));
#514=CARTESIAN_POINT('',(-9.54999998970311,0.000424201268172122,25.0997127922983));
#515=CARTESIAN_POINT('',(-9.55,-3.47759051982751E-08,25.0998563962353));
#516=CARTESIAN_POINT('',(-9.55,0.,25.1));
#517=B_SPLINE_CURVE_WITH_KNOTS('',3,(#375,#376,#377,#378,#379,#380,#381,#382,#383,#384,#385,
#386,#387,#388,#389,#390,#391,#392,#393,#394,#395,#396,#397,#398,#399,#400,#401,#402,#403,#404,
#405,#406,#407,#408,#409,#410,#411,#412,#413,#414,#415,#416,#417,#418,#419,#420,#421,#422,#423,
#424,#425,#426,#427,#428,#429,#430,#431,#432,#433,#434,#435,#436,#437,#438,#439,#440,#441,#442,
#443,#444,#445,#446,#447,#448,#449,#450,#451,#452,#453,#454,#455,#456,#457,#458,#459,#460,#461,
#462,#463,#464,#465,#466,#467,#468,#469,#470,#471,#472,#473,#474,#475,#476,#477,#478,#479,#480,
#481,#482,#483,#484,#485,#486,#487,#488,#489,#490,#491,#492,#493,#494,#495,#496,#497,#498,#499,
#500,#501,#502,#503,#504,#505,#506,#507,#508,#509,#510,#511,#512,#513,#514,#515,#516),
.UNSPECIFIED.,.T.,.F.,(4,2,2,2,2,2,2,2,2,2,2,2,2,2,2,2,2,2,2,2,2,2,2,2,2,2,2,2,2,2,2,2,2,2,2,2,
2,2,2,2,2,2,2,2,2,2,2,2,2,2,2,2,2,2,2,2,2,2,2,2,2,2,2,2,2,2,2,2,2,2,4),(0.,0.000880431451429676,
0.00243160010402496,0.00674349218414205,0.0195448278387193,0.292570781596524,0.569054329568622,
0.835444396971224,1.100940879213,1.68733296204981,2.27884620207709,2.73880759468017,
3.19779446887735,3.64808683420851,4.09858470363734,4.7121040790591,5.32832658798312,
5.97060769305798,6.61198053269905,7.06948666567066,7.52709191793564,7.97998303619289,
8.43289390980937,8.76897667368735,9.10497658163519,9.44126169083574,9.77748663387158,
10.3306557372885,10.6073799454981,10.8839699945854,11.1623959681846,11.4406968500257,
11.7190207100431,11.9973149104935,12.4945187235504,12.9915750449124,13.4655162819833,
13.9394066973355,14.4088543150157,14.8782769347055,15.3489548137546,15.8196311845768,
16.3001819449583,16.780782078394,17.2941651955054,17.808055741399,18.1787484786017,
18.54957169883,18.9200862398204,19.2907072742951,19.8118239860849,20.3331897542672,
20.8617526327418,21.3901547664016,22.1945693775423,23.000627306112,23.7606591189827,
24.5159003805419,24.8172874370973,25.1184943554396,25.4258729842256,25.7339072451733,
26.1353797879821,26.5333643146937,26.8944471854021,27.0821321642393,27.2674973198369,
27.2802946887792,27.2846094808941,27.2861614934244,27.2870421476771),.UNSPECIFIED.);
#518=CARTESIAN_POINT('',(-9.55,-2.23035405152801E-07,25.0999998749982));
#519=VERTEX_POINT('',#518);
#520=EDGE_CURVE('E641',#519,#339,#517,.T.);
#521=ORIENTED_EDGE('',*,*,#520,.F.);
#522=CARTESIAN_POINT('',(-6.69999999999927,-6.80532879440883,28.0962476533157));
#523=CARTESIAN_POINT('',(-6.81996946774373,-6.68725177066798,28.0902004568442));
#524=CARTESIAN_POINT('',(-6.93649081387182,-6.56625473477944,28.077190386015));
#525=CARTESIAN_POINT('',(-7.16193168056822,-6.31957018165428,28.0391558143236));
#526=CARTESIAN_POINT('',(-7.27086521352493,-6.19389200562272,28.014154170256));
#527=CARTESIAN_POINT('',(-7.47996613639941,-5.93965552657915,27.9542734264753));
#528=CARTESIAN_POINT('',(-7.58020183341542,-5.81113200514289,27.9194825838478));
#529=CARTESIAN_POINT('',(-7.77288444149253,-5.55076668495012,27.8414168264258));
#530=CARTESIAN_POINT('',(-7.8653262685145,-5.4189227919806,27.7981364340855));
#531=CARTESIAN_POINT('',(-8.08527935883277,-5.08794110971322,27.6816755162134));
#532=CARTESIAN_POINT('',(-8.20806234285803,-4.88717024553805,27.6041723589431));
#533=CARTESIAN_POINT('',(-8.43659039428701,-4.4811559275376,27.4368437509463));
#534=CARTESIAN_POINT('',(-8.54233044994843,-4.27591117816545,27.3470146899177));
#535=CARTESIAN_POINT('',(-8.73776973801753,-3.86092720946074,27.1572579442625));
#536=CARTESIAN_POINT('',(-8.82737926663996,-3.65116970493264,27.0572783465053));
#537=CARTESIAN_POINT('',(-8.99035400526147,-3.22911960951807,26.8498759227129));
#538=CARTESIAN_POINT('',(-9.06372075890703,-3.01682726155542,26.7424538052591));
#539=CARTESIAN_POINT('',(-9.19977329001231,-2.57379717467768,26.5134302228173));
#540=CARTESIAN_POINT('',(-9.26119179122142,-2.34290423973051,26.3913749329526));
#541=CARTESIAN_POINT('',(-9.3662171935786,-1.87961094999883,26.142666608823));
#542=CARTESIAN_POINT('',(-9.40982093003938,-1.64721033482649,26.0160127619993));
#543=CARTESIAN_POINT('',(-9.51423453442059,-0.949863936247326,25.632354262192));
#544=CARTESIAN_POINT('',(-9.54915312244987,-0.483098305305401,25.370765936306));
#545=CARTESIAN_POINT('',(-9.54999492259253,-0.0113662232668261,25.1063705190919));
#546=CARTESIAN_POINT('',(-9.54999999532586,-0.00568305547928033,25.1031852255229));
#547=CARTESIAN_POINT('',(-9.55,0.,25.1));
#548=B_SPLINE_CURVE_WITH_KNOTS('',3,(#522,#523,#524,#525,#526,#527,#528,#529,#530,#531,#532,
#533,#534,#535,#536,#537,#538,#539,#540,#541,#542,#543,#544,#545,#546,#547),.UNSPECIFIED.,.F.,
.F.,(4,2,2,2,2,2,2,2,2,2,2,2,4),(0.,0.504881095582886,1.00880365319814,1.5083210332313,
2.00816177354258,2.75035501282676,3.49276610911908,4.23918622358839,4.98553537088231,
5.78968736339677,6.5939821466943,8.19672773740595,8.21627256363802),.UNSPECIFIED.);
#549=EDGE_CURVE('E309',#349,#519,#548,.T.);
#550=ORIENTED_EDGE('',*,*,#549,.F.);
#551=ORIENTED_EDGE('',*,*,#350,.T.);
#552=EDGE_LOOP('',(#521,#550,#551));
#553=FACE_BOUND('',#552,.T.);
#554=ADVANCED_FACE('F650',(#553),#374,.T.);
#555=CARTESIAN_POINT('',(-6.55,-19.1,25.1));
#556=DIRECTION('',(0.,-1.,0.));
#557=DIRECTION('',(1.,0.,0.));
#558=AXIS2_PLACEMENT_3D('',#555,#556,#557);
#559=CYLINDRICAL_SURFACE('',#558,3.);
#560=CARTESIAN_POINT('',(-9.55,0.,25.1));
#561=CARTESIAN_POINT('',(-9.55000000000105,-0.00370124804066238,25.0979256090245));
#562=CARTESIAN_POINT('',(-9.54999784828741,-0.00740249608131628,25.0958512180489));
#563=CARTESIAN_POINT('',(-9.54998924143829,-0.0148049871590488,25.0917024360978));
#564=CARTESIAN_POINT('',(-9.54998278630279,-0.0185062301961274,25.0896280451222));
#565=CARTESIAN_POINT('',(-9.54996557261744,-0.0259087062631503,25.0854792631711));
#566=CARTESIAN_POINT('',(-9.54995481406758,-0.0296099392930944,25.0834048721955));
#567=CARTESIAN_POINT('',(-9.54992899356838,-0.0370123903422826,25.0792560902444));
#568=CARTESIAN_POINT('',(-9.54991393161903,-0.0407136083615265,25.0771816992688));
#569=CARTESIAN_POINT('',(-9.54987950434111,-0.0481160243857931,25.0730329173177));
#570=CARTESIAN_POINT('',(-9.54986013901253,-0.0518172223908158,25.0709585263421));
#571=CARTESIAN_POINT('',(-9.54981710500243,-0.0592195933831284,25.066809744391));
#572=CARTESIAN_POINT('',(-9.54979343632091,-0.0629207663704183,25.0647353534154));
#573=CARTESIAN_POINT('',(-9.54974179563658,-0.0703230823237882,25.0605865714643));
#574=CARTESIAN_POINT('',(-9.54971382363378,-0.0740242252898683,25.0585121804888));
#575=CARTESIAN_POINT('',(-9.54965357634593,-0.081426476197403,25.0543633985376));
#576=CARTESIAN_POINT('',(-9.54962130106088,-0.0851275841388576,25.0522890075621));
#577=CARTESIAN_POINT('',(-9.54958687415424,-0.0888286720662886,25.0502146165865));
#578=B_SPLINE_CURVE_WITH_KNOTS('',3,(#560,#561,#562,#563,#564,#565,#566,#567,#568,#569,#570,
#571,#572,#573,#574,#575,#576,#577),.UNSPECIFIED.,.F.,.F.,(4,2,2,2,2,2,2,2,4),(0.,
0.0127287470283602,0.0254574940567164,0.0381862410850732,0.0509149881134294,0.0636437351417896,
0.0763724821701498,0.0891012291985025,0.101829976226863),.UNSPECIFIED.);
#579=EDGE_CURVE('E302',#519,#316,#578,.T.);
#580=ORIENTED_EDGE('',*,*,#579,.F.);
#581=CARTESIAN_POINT('',(-9.54958687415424,0.0888286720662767,25.0502146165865));
#582=CARTESIAN_POINT('',(-9.54962130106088,0.08512758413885,25.0522890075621));
#583=CARTESIAN_POINT('',(-9.54965357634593,0.0814264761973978,25.0543633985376));
#584=CARTESIAN_POINT('',(-9.54971382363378,0.0740242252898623,25.0585121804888));
#585=CARTESIAN_POINT('',(-9.54974179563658,0.070323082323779,25.0605865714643));
#586=CARTESIAN_POINT('',(-9.54979343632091,0.0629207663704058,25.0647353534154));
#587=CARTESIAN_POINT('',(-9.54981710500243,0.0592195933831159,25.066809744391));
#588=CARTESIAN_POINT('',(-9.54986013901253,0.0518172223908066,25.0709585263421));
#589=CARTESIAN_POINT('',(-9.54987950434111,0.0481160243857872,25.0730329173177));
#590=CARTESIAN_POINT('',(-9.54991393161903,0.0407136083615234,25.0771816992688));
#591=CARTESIAN_POINT('',(-9.54992899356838,0.0370123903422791,25.0792560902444));
#592=CARTESIAN_POINT('',(-9.54995481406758,0.029609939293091,25.0834048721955));
#593=CARTESIAN_POINT('',(-9.54996557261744,0.0259087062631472,25.0854792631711));
#594=CARTESIAN_POINT('',(-9.54998278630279,0.0185062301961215,25.0896280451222));
#595=CARTESIAN_POINT('',(-9.54998924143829,0.0148049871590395,25.0917024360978));
#596=CARTESIAN_POINT('',(-9.54999784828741,0.00740249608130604,25.0958512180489));
#597=CARTESIAN_POINT('',(-9.55000000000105,0.00370124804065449,25.0979256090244));
#598=CARTESIAN_POINT('',(-9.55,0.,25.1));
#599=B_SPLINE_CURVE_WITH_KNOTS('',3,(#581,#582,#583,#584,#585,#586,#587,#588,#589,#590,#591,
#592,#593,#594,#595,#596,#597,#598),.UNSPECIFIED.,.F.,.F.,(4,2,2,2,2,2,2,2,4),(0.,
0.0127287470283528,0.025457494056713,0.0381862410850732,0.050914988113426,0.0636437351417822,
0.076372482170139,0.0891012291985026,0.101829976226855),.UNSPECIFIED.);
#600=EDGE_CURVE('E640',#285,#519,#599,.T.);
#601=ORIENTED_EDGE('',*,*,#600,.F.);
#602=ORIENTED_EDGE('',*,*,#323,.T.);
#603=EDGE_LOOP('',(#580,#601,#602));
#604=FACE_BOUND('',#603,.T.);
#605=ADVANCED_FACE('F361',(#604),#559,.T.);
#606=CARTESIAN_POINT('',(0.,0.,23.4));
#607=DIRECTION('',(0.,0.,-1.));
#608=DIRECTION('',(0.,1.,0.));
#609=AXIS2_PLACEMENT_3D('',#606,#607,#608);
#610=TOROIDAL_SURFACE('',#609,62.5,2.50000000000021);
#611=CARTESIAN_POINT('',(64.9476609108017,2.60793830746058,23.4));
#612=CARTESIAN_POINT('',(64.9476635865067,2.60791747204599,23.385594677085));
#613=CARTESIAN_POINT('',(64.947502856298,2.60877349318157,23.3712062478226));
#614=CARTESIAN_POINT('',(64.9468772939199,2.61206665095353,23.3426765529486));
#615=CARTESIAN_POINT('',(64.9464137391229,2.61449714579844,23.3285345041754));
#616=CARTESIAN_POINT('',(64.9452204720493,2.6206884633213,23.3009477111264));
#617=CARTESIAN_POINT('',(64.9444979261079,2.62441339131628,23.2874943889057));
#618=CARTESIAN_POINT('',(64.9428130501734,2.63298432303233,23.2609554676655));
#619=CARTESIAN_POINT('',(64.941850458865,2.63783154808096,23.2478702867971));
#620=CARTESIAN_POINT('',(64.9386420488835,2.65373696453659,23.20918343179));
#621=CARTESIAN_POINT('',(64.9360765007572,2.66615397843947,23.1841697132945));
#622=CARTESIAN_POINT('',(64.930257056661,2.69326279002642,23.1354982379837));
#623=CARTESIAN_POINT('',(64.9270020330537,2.70795830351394,23.1118427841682));
#624=CARTESIAN_POINT('',(64.919825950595,2.73911357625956,23.0651153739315));
#625=CARTESIAN_POINT('',(64.9158924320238,2.75560370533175,23.0420658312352));
#626=CARTESIAN_POINT('',(64.9074693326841,2.78954602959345,22.9968322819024));
#627=CARTESIAN_POINT('',(64.9029801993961,2.80699744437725,22.9746475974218));
#628=CARTESIAN_POINT('',(64.8921425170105,2.84753754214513,22.9247915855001));
#629=CARTESIAN_POINT('',(64.8856256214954,2.87083431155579,22.8973268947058));
#630=CARTESIAN_POINT('',(64.8717651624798,2.91808586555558,22.8431803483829));
#631=CARTESIAN_POINT('',(64.8644214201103,2.94204079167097,22.8164986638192));
#632=CARTESIAN_POINT('',(64.8411574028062,3.01457187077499,22.7372790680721));
#633=CARTESIAN_POINT('',(64.8240216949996,3.06374820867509,22.6856446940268));
#634=CARTESIAN_POINT('',(64.786552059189,3.16262479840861,22.5839964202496));
#635=CARTESIAN_POINT('',(64.7662155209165,3.21232544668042,22.5339838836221));
#636=CARTESIAN_POINT('',(64.7225235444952,3.31125530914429,22.4357315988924));
#637=CARTESIAN_POINT('',(64.6991946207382,3.36048500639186,22.3874805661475));
#638=CARTESIAN_POINT('',(64.649378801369,3.45847846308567,22.2922586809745));
#639=CARTESIAN_POINT('',(64.6228949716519,3.50724262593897,22.2452866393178));
#640=CARTESIAN_POINT('',(64.5667171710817,3.60405706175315,22.1526018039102));
#641=CARTESIAN_POINT('',(64.5370250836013,3.65210773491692,22.1068882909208));
#642=CARTESIAN_POINT('',(64.4865991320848,3.72869921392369,22.0343649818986));
#643=CARTESIAN_POINT('',(64.4668945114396,3.75753177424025,22.0071437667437));
#644=CARTESIAN_POINT('',(64.4262368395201,3.8148255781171,21.9531918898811));
#645=CARTESIAN_POINT('',(64.405282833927,3.84328651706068,21.9264616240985));
#646=CARTESIAN_POINT('',(64.3837035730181,3.8715260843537,21.900000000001));
#647=B_SPLINE_CURVE_WITH_KNOTS('',3,(#611,#612,#613,#614,#615,#616,#617,#618,#619,#620,#621,
#622,#623,#624,#625,#626,#627,#628,#629,#630,#631,#632,#633,#634,#635,#636,#637,#638,#639,#640,
#641,#642,#643,#644,#645,#646),.UNSPECIFIED.,.F.,.F.,(4,2,2,2,2,2,2,2,2,2,2,2,2,2,2,2,2,4),(0.,
0.043162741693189,0.0861445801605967,0.128018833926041,0.169938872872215,0.253838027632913,
0.337875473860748,0.423663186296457,0.509382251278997,0.619147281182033,0.728936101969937,
0.948824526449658,1.16889320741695,1.38713161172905,1.60515963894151,1.82306036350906,
1.95587581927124,2.08879405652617),.UNSPECIFIED.);
#648=CARTESIAN_POINT('',(64.9476609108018,2.60793830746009,23.4));
#649=VERTEX_POINT('',#648);
#650=CARTESIAN_POINT('',(64.3837035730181,3.8715260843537,21.9000000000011));
#651=VERTEX_POINT('',#650);
#652=EDGE_CURVE('E618',#649,#651,#647,.T.);
#653=ORIENTED_EDGE('',*,*,#652,.F.);
#654=CARTESIAN_POINT('',(0.,0.,23.4));
#655=DIRECTION('',(0.,0.,1.));
#656=DIRECTION('',(0.,-1.,0.));
#657=AXIS2_PLACEMENT_3D('',#654,#655,#656);
#658=CIRCLE('',#657,65.);
#659=CARTESIAN_POINT('',(64.9476609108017,-2.60793830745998,23.4));
#660=VERTEX_POINT('',#659);
#661=EDGE_CURVE('E369',#660,#649,#658,.T.);
#662=ORIENTED_EDGE('',*,*,#661,.F.);
#663=CARTESIAN_POINT('',(64.3837035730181,-3.87152608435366,21.900000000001));
#664=CARTESIAN_POINT('',(64.4180366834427,-3.82659670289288,21.9421078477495));
#665=CARTESIAN_POINT('',(64.4507897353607,-3.78110226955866,21.9848884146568));
#666=CARTESIAN_POINT('',(64.51320073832,-3.68917940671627,22.071721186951));
#667=CARTESIAN_POINT('',(64.5428577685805,-3.64275070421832,22.1157737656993));
#668=CARTESIAN_POINT('',(64.5991290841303,-3.5491696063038,22.2050638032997));
#669=CARTESIAN_POINT('',(64.6257425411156,-3.50201701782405,22.2503015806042));
#670=CARTESIAN_POINT('',(64.6758790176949,-3.407397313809,22.341773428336));
#671=CARTESIAN_POINT('',(64.6994122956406,-3.35993182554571,22.38800356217));
#672=CARTESIAN_POINT('',(64.7435259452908,-3.26483020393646,22.4816568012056));
#673=CARTESIAN_POINT('',(64.764106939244,-3.21719410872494,22.529079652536));
#674=CARTESIAN_POINT('',(64.8023331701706,-3.12216841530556,22.6252958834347));
#675=CARTESIAN_POINT('',(64.8199798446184,-3.07477870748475,22.6740885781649));
#676=CARTESIAN_POINT('',(64.8431825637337,-3.00748612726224,22.7454166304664));
#677=CARTESIAN_POINT('',(64.8499332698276,-2.98719207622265,22.7671994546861));
#678=CARTESIAN_POINT('',(64.8628729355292,-2.94688678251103,22.8111908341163));
#679=CARTESIAN_POINT('',(64.8690619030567,-2.92687553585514,22.8333993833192));
#680=CARTESIAN_POINT('',(64.8808822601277,-2.88722543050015,22.8783931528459));
#681=CARTESIAN_POINT('',(64.8865122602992,-2.86758759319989,22.9011796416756));
#682=CARTESIAN_POINT('',(64.897179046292,-2.82894454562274,22.9474172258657));
#683=CARTESIAN_POINT('',(64.9022159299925,-2.80993923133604,22.9708682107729));
#684=CARTESIAN_POINT('',(64.9104527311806,-2.77764499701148,23.0125177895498));
#685=CARTESIAN_POINT('',(64.9137924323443,-2.76414027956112,23.0305206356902));
#686=CARTESIAN_POINT('',(64.920103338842,-2.7378797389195,23.0671250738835));
#687=CARTESIAN_POINT('',(64.9230746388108,-2.72512372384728,23.0857265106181));
#688=CARTESIAN_POINT('',(64.928609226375,-2.70069524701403,23.1236399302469));
#689=CARTESIAN_POINT('',(64.9311733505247,-2.68902058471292,23.1429503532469));
#690=CARTESIAN_POINT('',(64.9358433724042,-2.66720979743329,23.1824638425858));
#691=CARTESIAN_POINT('',(64.9379497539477,-2.65707205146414,23.2026659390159));
#692=CARTESIAN_POINT('',(64.9417784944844,-2.63825061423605,23.245853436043));
#693=CARTESIAN_POINT('',(64.9434538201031,-2.62976022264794,23.2689301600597));
#694=CARTESIAN_POINT('',(64.9460154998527,-2.61660407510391,23.3161557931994));
#695=CARTESIAN_POINT('',(64.946905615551,-2.61192009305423,23.3402990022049));
#696=CARTESIAN_POINT('',(64.947449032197,-2.6090565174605,23.3705170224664));
#697=CARTESIAN_POINT('',(64.9475283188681,-2.60863832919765,23.3764008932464));
#698=CARTESIAN_POINT('',(64.9476342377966,-2.60807937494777,23.3881892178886));
#699=CARTESIAN_POINT('',(64.9476608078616,-2.6079389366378,23.3940936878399));
#700=CARTESIAN_POINT('',(64.9476609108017,-2.60793830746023,23.4));
#701=B_SPLINE_CURVE_WITH_KNOTS('',3,(#663,#664,#665,#666,#667,#668,#669,#670,#671,#672,#673,
#674,#675,#676,#677,#678,#679,#680,#681,#682,#683,#684,#685,#686,#687,#688,#689,#690,#691,#692,
#693,#694,#695,#696,#697,#698,#699,#700),.UNSPECIFIED.,.F.,.F.,(4,2,2,2,2,2,2,2,2,2,2,2,2,2,2,2,
2,2,4),(0.,0.211470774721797,0.423004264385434,0.634595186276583,0.845462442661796,
1.05628518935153,1.26700435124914,1.35857909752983,1.45015255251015,1.54194820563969,
1.63372868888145,1.70196621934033,1.77018618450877,1.8382641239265,1.90626975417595,
1.97997982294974,2.05333483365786,2.07102756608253,2.08874115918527),.UNSPECIFIED.);
#702=CARTESIAN_POINT('',(64.3837035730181,-3.87152608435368,21.900000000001));
#703=VERTEX_POINT('',#702);
#704=EDGE_CURVE('E347',#703,#660,#701,.T.);
#705=ORIENTED_EDGE('',*,*,#704,.F.);
#706=CARTESIAN_POINT('',(0.,0.,21.900000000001));
#707=DIRECTION('',(0.,0.,1.));
#708=DIRECTION('',(0.,-1.,0.));
#709=AXIS2_PLACEMENT_3D('',#706,#707,#708);
#710=CIRCLE('',#709,64.5000000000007);
#711=EDGE_CURVE('E371',#651,#703,#710,.F.);
#712=ORIENTED_EDGE('',*,*,#711,.F.);
#713=EDGE_LOOP('',(#653,#662,#705,#712));
#714=FACE_BOUND('',#713,.T.);
#715=ADVANCED_FACE('F355',(#714),#610,.T.);
#716=CARTESIAN_POINT('',(0.,0.,21.900000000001));
#717=DIRECTION('',(0.,0.,1.));
#718=DIRECTION('',(-1.,0.,0.));
#719=AXIS2_PLACEMENT_3D('',#716,#717,#718);
#720=CONICAL_SURFACE('',#719,64.5000000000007,0.628318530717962);
#721=CARTESIAN_POINT('',(0.,0.,19.9732884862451));
#722=DIRECTION('',(0.,0.,-1.));
#723=DIRECTION('',(0.,1.,0.));
#724=AXIS2_PLACEMENT_3D('',#721,#722,#723);
#725=CIRCLE('',#724,63.1001621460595);
#726=CARTESIAN_POINT('',(62.9089199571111,4.9089971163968,19.9732884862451));
#727=VERTEX_POINT('',#726);
#728=CARTESIAN_POINT('',(62.9089199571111,-4.90899711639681,19.9732884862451));
#729=VERTEX_POINT('',#728);
#730=EDGE_CURVE('E1225',#727,#729,#725,.T.);
#731=ORIENTED_EDGE('',*,*,#730,.F.);
#732=CARTESIAN_POINT('',(64.3837035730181,3.87152608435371,21.9000000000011));
#733=CARTESIAN_POINT('',(64.352701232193,3.91209145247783,21.8607575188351));
#734=CARTESIAN_POINT('',(64.3210959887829,3.95131019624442,21.8206322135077));
#735=CARTESIAN_POINT('',(64.2568437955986,4.0271517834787,21.7388312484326));
#736=CARTESIAN_POINT('',(64.2241972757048,4.0637756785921,21.6971562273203));
#737=CARTESIAN_POINT('',(64.1250410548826,4.16980127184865,21.5702567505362));
#738=CARTESIAN_POINT('',(64.0571841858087,4.23552501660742,21.4829926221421));
#739=CARTESIAN_POINT('',(63.9199552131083,4.35695361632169,21.3057351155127));
#740=CARTESIAN_POINT('',(63.8506231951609,4.41279862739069,21.2158054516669));
#741=CARTESIAN_POINT('',(63.7100737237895,4.51642879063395,21.0327880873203));
#742=CARTESIAN_POINT('',(63.6388554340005,4.5642102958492,20.9396989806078));
#743=CARTESIAN_POINT('',(63.4601357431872,4.67368217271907,20.7052502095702));
#744=CARTESIAN_POINT('',(63.3518067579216,4.73086173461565,20.5623985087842));
#745=CARTESIAN_POINT('',(63.1873854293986,4.80568378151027,20.3444987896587));
#746=CARTESIAN_POINT('',(63.1319221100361,4.82890440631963,20.2708137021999));
#747=CARTESIAN_POINT('',(63.0206530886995,4.87166877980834,20.1226286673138));
#748=CARTESIAN_POINT('',(62.9648473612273,4.89121225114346,20.0481286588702));
#749=CARTESIAN_POINT('',(62.9089199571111,4.90899711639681,19.9732884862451));
#750=B_SPLINE_CURVE_WITH_KNOTS('',3,(#732,#733,#734,#735,#736,#737,#738,#739,#740,#741,#742,
#743,#744,#745,#746,#747,#748,#749),.UNSPECIFIED.,.F.,.F.,(4,2,2,2,2,2,2,2,4),(0.,
0.19312803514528,0.386177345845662,0.771470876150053,1.15076079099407,1.53022179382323,
2.09392248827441,2.37917816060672,2.66445533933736),.UNSPECIFIED.);
#751=EDGE_CURVE('E631',#651,#727,#750,.T.);
#752=ORIENTED_EDGE('',*,*,#751,.F.);
#753=ORIENTED_EDGE('',*,*,#711,.T.);
#754=CARTESIAN_POINT('',(62.9089199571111,-4.90899711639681,19.9732884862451));
#755=CARTESIAN_POINT('',(62.9630024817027,-4.89179931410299,20.0456599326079));
#756=CARTESIAN_POINT('',(63.0169726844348,-4.87295596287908,20.1177151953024));
#757=CARTESIAN_POINT('',(63.124616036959,-4.83182750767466,20.2610945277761));
#758=CARTESIAN_POINT('',(63.1782890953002,-4.80954139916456,20.3324183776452));
#759=CARTESIAN_POINT('',(63.3392215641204,-4.73707736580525,20.5457640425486));
#760=CARTESIAN_POINT('',(63.4458714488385,-4.68145647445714,20.6864603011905));
#761=CARTESIAN_POINT('',(63.6533664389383,-4.55612429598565,20.958799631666));
#762=CARTESIAN_POINT('',(63.7542903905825,-4.48685733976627,21.0905862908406));
#763=CARTESIAN_POINT('',(63.9518017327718,-4.33171037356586,21.3470805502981));
#764=CARTESIAN_POINT('',(64.0483992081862,-4.24587177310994,21.4718048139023));
#765=CARTESIAN_POINT('',(64.1834348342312,-4.10819047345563,21.6450407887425));
#766=CARTESIAN_POINT('',(64.2244694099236,-4.06382992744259,21.6975241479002));
#767=CARTESIAN_POINT('',(64.3052216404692,-3.97087451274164,21.800471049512));
#768=CARTESIAN_POINT('',(64.3449294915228,-3.92225497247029,21.8509199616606));
#769=CARTESIAN_POINT('',(64.3837035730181,-3.87152608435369,21.900000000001));
#770=B_SPLINE_CURVE_WITH_KNOTS('',3,(#754,#755,#756,#757,#758,#759,#760,#761,#762,#763,#764,
#765,#766,#767,#768,#769),.UNSPECIFIED.,.F.,.F.,(4,2,2,2,2,2,2,4),(0.,0.275873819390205,
0.551828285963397,1.10639534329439,1.64523513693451,2.18274549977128,2.42273350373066,
2.66421751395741),.UNSPECIFIED.);
#771=EDGE_CURVE('E301',#729,#703,#770,.T.);
#772=ORIENTED_EDGE('',*,*,#771,.F.);
#773=EDGE_LOOP('',(#731,#752,#753,#772));
#774=FACE_BOUND('',#773,.T.);
#775=ADVANCED_FACE('F360',(#774),#720,.T.);
#776=CARTESIAN_POINT('',(0.,0.,17.7985195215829));
#777=DIRECTION('',(0.,0.,1.));
#778=DIRECTION('',(-1.,0.,0.));
#779=AXIS2_PLACEMENT_3D('',#776,#777,#778);
#780=CONICAL_SURFACE('',#779,9.42922749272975,0.0165958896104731);
#781=CARTESIAN_POINT('',(0.,0.,17.798519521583));
#782=DIRECTION('',(0.,0.,-1.));
#783=DIRECTION('',(1.,0.,0.));
#784=AXIS2_PLACEMENT_3D('',#781,#782,#783);
#785=CIRCLE('',#784,9.42922749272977);
#786=EDGE_CURVE('E1450',#296,#296,#785,.T.);
#787=ORIENTED_EDGE('',*,*,#786,.T.);
#788=EDGE_LOOP('',(#787));
#789=FACE_BOUND('',#788,.T.);
#790=ORIENTED_EDGE('',*,*,#264,.T.);
#791=EDGE_LOOP('',(#790));
#792=FACE_BOUND('',#791,.T.);
#793=ADVANCED_FACE('F1076',(#789,#792),#780,.T.);
#794=CARTESIAN_POINT('',(0.,0.,0.));
#795=DIRECTION('',(0.,0.,1.));
#796=DIRECTION('',(0.,-1.,0.));
#797=AXIS2_PLACEMENT_3D('',#794,#795,#796);
#798=CYLINDRICAL_SURFACE('',#797,65.);
#799=ORIENTED_EDGE('',*,*,#661,.T.);
#800=DIRECTION('',(0.,0.,1.));
#801=VECTOR('',#800,1.);
#802=CARTESIAN_POINT('',(64.9476609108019,2.60793830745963,65.));
#803=LINE('',#802,#801);
#804=CARTESIAN_POINT('',(64.9476609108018,2.60793830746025,25.5534224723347));
#805=VERTEX_POINT('',#804);
#806=EDGE_CURVE('E1171',#805,#649,#803,.F.);
#807=ORIENTED_EDGE('',*,*,#806,.F.);
#808=CARTESIAN_POINT('',(0.,0.,25.5534224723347));
#809=DIRECTION('',(0.,0.,-1.));
#810=DIRECTION('',(0.,1.,0.));
#811=AXIS2_PLACEMENT_3D('',#808,#809,#810);
#812=CIRCLE('',#811,65.);
#813=CARTESIAN_POINT('',(64.9476609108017,-2.60793830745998,25.5534224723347));
#814=VERTEX_POINT('',#813);
#815=EDGE_CURVE('E578',#814,#805,#812,.F.);
#816=ORIENTED_EDGE('',*,*,#815,.F.);
#817=DIRECTION('',(0.,0.,1.));
#818=VECTOR('',#817,1.);
#819=CARTESIAN_POINT('',(64.9476609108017,-2.60793830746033,65.));
#820=LINE('',#819,#818);
#821=EDGE_CURVE('E354',#660,#814,#820,.T.);
#822=ORIENTED_EDGE('',*,*,#821,.F.);
#823=EDGE_LOOP('',(#799,#807,#816,#822));
#824=FACE_BOUND('',#823,.T.);
#825=ADVANCED_FACE('F612',(#824),#798,.T.);
#826=CARTESIAN_POINT('',(62.,2.04999999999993,65.));
#827=DIRECTION('',(0.,0.,1.));
#828=DIRECTION('',(0.,-1.,0.));
#829=AXIS2_PLACEMENT_3D('',#826,#827,#828);
#830=CYLINDRICAL_SURFACE('',#829,3.00000000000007);
#831=CARTESIAN_POINT('',(62.0873568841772,5.04872785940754,19.0696484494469));
#832=CARTESIAN_POINT('',(62.1255083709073,5.04761625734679,19.1042945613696));
#833=CARTESIAN_POINT('',(62.1632276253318,5.0457889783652,19.1393895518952));
#834=CARTESIAN_POINT('',(62.2376446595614,5.04080449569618,19.2103202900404));
#835=CARTESIAN_POINT('',(62.2743453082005,5.03765154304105,19.2461533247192));
#836=CARTESIAN_POINT('',(62.346740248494,5.03011627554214,19.3185530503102));
#837=CARTESIAN_POINT('',(62.3824363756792,5.02573638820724,19.3551181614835));
#838=CARTESIAN_POINT('',(62.452836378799,5.01583911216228,19.4289780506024));
#839=CARTESIAN_POINT('',(62.4875411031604,5.01032273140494,19.4662721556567));
#840=CARTESIAN_POINT('',(62.5559569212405,4.9982398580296,19.5415746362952));
#841=CARTESIAN_POINT('',(62.5896682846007,4.99167365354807,19.5795828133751));
#842=CARTESIAN_POINT('',(62.6561238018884,4.97756838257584,19.6563326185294));
#843=CARTESIAN_POINT('',(62.6888668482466,4.970028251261,19.6950750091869));
#844=CARTESIAN_POINT('',(62.7533949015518,4.95404944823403,19.773300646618));
#845=CARTESIAN_POINT('',(62.7851778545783,4.94560900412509,19.8127852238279));
#846=CARTESIAN_POINT('',(62.8477922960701,4.92790019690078,19.8925055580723));
#847=CARTESIAN_POINT('',(62.8786208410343,4.91862956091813,19.9327431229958));
#848=CARTESIAN_POINT('',(62.9089199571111,4.9089971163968,19.9732884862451));
#849=B_SPLINE_CURVE_WITH_KNOTS('',3,(#831,#832,#833,#834,#835,#836,#837,#838,#839,#840,#841,
#842,#843,#844,#845,#846,#847,#848),.UNSPECIFIED.,.F.,.F.,(4,2,2,2,2,2,2,2,4),(0.,
0.154629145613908,0.308766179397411,0.462600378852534,0.616298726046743,0.769954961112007,
0.923780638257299,1.07791493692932,1.23248493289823),.UNSPECIFIED.);
#850=CARTESIAN_POINT('',(62.0873568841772,5.04872785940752,19.0696484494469));
#851=VERTEX_POINT('',#850);
#852=EDGE_CURVE('E626',#851,#727,#849,.T.);
#853=ORIENTED_EDGE('',*,*,#852,.F.);
#854=DIRECTION('',(0.,0.,1.));
#855=VECTOR('',#854,1.);
#856=CARTESIAN_POINT('',(62.0873568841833,5.04872785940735,65.));
#857=LINE('',#856,#855);
#858=CARTESIAN_POINT('',(62.0873568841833,5.04872785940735,27.9810421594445));
#859=VERTEX_POINT('',#858);
#860=EDGE_CURVE('E566',#851,#859,#857,.T.);
#861=ORIENTED_EDGE('',*,*,#860,.T.);
#862=CARTESIAN_POINT('',(62.0873568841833,5.04872785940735,27.9810421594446));
#863=CARTESIAN_POINT('',(62.1686347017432,5.04634957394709,27.9753882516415));
#864=CARTESIAN_POINT('',(62.2495521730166,5.04070117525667,27.9697586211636));
#865=CARTESIAN_POINT('',(62.4106664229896,5.02286415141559,27.9585479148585));
#866=CARTESIAN_POINT('',(62.4908632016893,5.01067552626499,27.9529668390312));
#867=CARTESIAN_POINT('',(62.5706996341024,4.99521678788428,27.9474100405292));
#868=B_SPLINE_CURVE_WITH_KNOTS('',3,(#862,#863,#864,#865,#866,#867),.UNSPECIFIED.,.F.,.F.,(4,2,
4),(0.,0.243928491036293,0.487856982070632),.UNSPECIFIED.);
#869=CARTESIAN_POINT('',(62.5706996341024,4.99521678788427,27.9474100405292));
#870=VERTEX_POINT('',#869);
#871=EDGE_CURVE('E1168',#859,#870,#868,.T.);
#872=ORIENTED_EDGE('',*,*,#871,.T.);
#873=CARTESIAN_POINT('',(64.9476609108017,2.6079383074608,25.5534224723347));
#874=CARTESIAN_POINT('',(64.9476633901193,2.60791924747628,25.567115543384));
#875=CARTESIAN_POINT('',(64.9475121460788,2.60872439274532,25.5807933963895));
#876=CARTESIAN_POINT('',(64.9469231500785,2.6118257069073,25.6079197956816));
#877=CARTESIAN_POINT('',(64.9464865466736,2.61411589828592,25.6213690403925));
#878=CARTESIAN_POINT('',(64.9453615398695,2.61995912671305,25.6476228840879));
#879=CARTESIAN_POINT('',(64.9446796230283,2.62347957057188,25.6604352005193));
#880=CARTESIAN_POINT('',(64.9430887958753,2.63158884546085,25.6857119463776));
#881=CARTESIAN_POINT('',(64.9421796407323,2.63617882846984,25.6981759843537));
#882=CARTESIAN_POINT('',(64.9395348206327,2.6493356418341,25.7303265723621));
#883=CARTESIAN_POINT('',(64.937635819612,2.6586058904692,25.7497103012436));
#884=CARTESIAN_POINT('',(64.9333964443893,2.67872193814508,25.7875829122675));
#885=CARTESIAN_POINT('',(64.9310557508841,2.68956887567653,25.8060711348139));
#886=CARTESIAN_POINT('',(64.9259518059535,2.71253039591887,25.8425782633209));
#887=CARTESIAN_POINT('',(64.9231825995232,2.72466193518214,25.8605855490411));
#888=CARTESIAN_POINT('',(64.9172884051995,2.74971008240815,25.8959677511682));
#889=CARTESIAN_POINT('',(64.9141635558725,2.76262638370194,25.9133429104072));
#890=CARTESIAN_POINT('',(64.906260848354,2.7943187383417,25.9544655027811));
#891=CARTESIAN_POINT('',(64.9013228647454,2.8133662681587,25.9779720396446));
#892=CARTESIAN_POINT('',(64.8908333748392,2.85217711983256,26.0242488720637));
#893=CARTESIAN_POINT('',(64.8852816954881,2.87194064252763,26.0470189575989));
#894=CARTESIAN_POINT('',(64.8677221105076,2.93198956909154,26.1145521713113));
#895=CARTESIAN_POINT('',(64.8548244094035,2.97297303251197,26.1584635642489));
#896=CARTESIAN_POINT('',(64.8267259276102,3.05575343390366,26.2448128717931));
#897=CARTESIAN_POINT('',(64.8115231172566,3.0975510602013,26.2872494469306));
#898=CARTESIAN_POINT('',(64.7788849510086,3.18128754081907,26.3708356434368));
#899=CARTESIAN_POINT('',(64.7614565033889,3.22322558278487,26.4119887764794));
#900=CARTESIAN_POINT('',(64.7243434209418,3.30700057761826,26.4932672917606));
#901=CARTESIAN_POINT('',(64.7046612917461,3.34883759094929,26.5333937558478));
#902=CARTESIAN_POINT('',(64.6630111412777,3.43222426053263,26.6127187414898));
#903=CARTESIAN_POINT('',(64.6410437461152,3.47377399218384,26.6519175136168));
#904=CARTESIAN_POINT('',(64.5833088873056,3.57693614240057,26.7486403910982));
#905=CARTESIAN_POINT('',(64.5461016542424,3.63827581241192,26.805608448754));
#906=CARTESIAN_POINT('',(64.4663740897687,3.75946385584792,26.9173802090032));
#907=CARTESIAN_POINT('',(64.4238520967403,3.81931175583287,26.9721832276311));
#908=CARTESIAN_POINT('',(64.288150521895,3.99586165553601,27.1328878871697));
#909=CARTESIAN_POINT('',(64.1867490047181,4.1097277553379,27.235232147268));
#910=CARTESIAN_POINT('',(63.978123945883,4.30934371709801,27.4121999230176));
#911=CARTESIAN_POINT('',(63.8740630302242,4.39674772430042,27.4886781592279));
#912=CARTESIAN_POINT('',(63.6491822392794,4.55987073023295,27.6286726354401));
#913=CARTESIAN_POINT('',(63.5283720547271,4.63559643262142,27.6921963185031));
#914=CARTESIAN_POINT('',(63.2960215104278,4.75813817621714,27.7910265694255));
#915=CARTESIAN_POINT('',(63.1872866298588,4.80771179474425,27.8294217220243));
#916=CARTESIAN_POINT('',(63.0178784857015,4.87269113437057,27.8763565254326));
#917=CARTESIAN_POINT('',(62.9604184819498,4.89277205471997,27.8902166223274));
#918=CARTESIAN_POINT('',(62.8436641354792,4.92957763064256,27.9140674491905));
#919=CARTESIAN_POINT('',(62.784371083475,4.94630458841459,27.9240608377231));
#920=CARTESIAN_POINT('',(62.6989901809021,4.96755013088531,27.9352970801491));
#921=CARTESIAN_POINT('',(62.6734797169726,4.97354478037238,27.9382621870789));
#922=CARTESIAN_POINT('',(62.6222448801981,4.98487631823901,27.943419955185));
#923=CARTESIAN_POINT('',(62.5965205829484,4.99021342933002,27.9456128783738));
#924=CARTESIAN_POINT('',(62.5706996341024,4.99521678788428,27.9474100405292));
#925=B_SPLINE_CURVE_WITH_KNOTS('',3,(#873,#874,#875,#876,#877,#878,#879,#880,#881,#882,#883,
#884,#885,#886,#887,#888,#889,#890,#891,#892,#893,#894,#895,#896,#897,#898,#899,#900,#901,#902,
#903,#904,#905,#906,#907,#908,#909,#910,#911,#912,#913,#914,#915,#916,#917,#918,#919,#920,#921,
#922,#923,#924),.UNSPECIFIED.,.F.,.F.,(4,2,2,2,2,2,2,2,2,2,2,2,2,2,2,2,2,2,2,2,2,2,2,2,2,4),(0.,
0.0410304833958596,0.0818968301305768,0.121753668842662,0.161653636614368,0.226241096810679,
0.290875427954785,0.356505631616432,0.422110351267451,0.514041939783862,0.605999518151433,
0.790205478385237,0.974574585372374,1.15838472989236,1.34199246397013,1.52555002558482,
1.80016898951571,2.07487402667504,2.62359219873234,3.08988480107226,3.55590873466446,
3.93082088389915,4.11790471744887,4.3048596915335,4.38396069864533,4.46303483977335),.UNSPECIFIED.);
#926=EDGE_CURVE('E592',#805,#870,#925,.T.);
#927=ORIENTED_EDGE('',*,*,#926,.F.);
#928=ORIENTED_EDGE('',*,*,#806,.T.);
#929=ORIENTED_EDGE('',*,*,#652,.T.);
#930=ORIENTED_EDGE('',*,*,#751,.T.);
#931=EDGE_LOOP('',(#853,#861,#872,#927,#928,#929,#930));
#932=FACE_BOUND('',#931,.T.);
#933=ADVANCED_FACE('F606',(#932),#830,.T.);
#934=CARTESIAN_POINT('',(0.,0.,65.));
#935=DIRECTION('',(0.,0.,1.));
#936=DIRECTION('',(0.,-1.,0.));
#937=AXIS2_PLACEMENT_3D('',#934,#935,#936);
#938=CYLINDRICAL_SURFACE('',#937,9.55);
#939=DIRECTION('',(0.,0.,1.));
#940=VECTOR('',#939,1.);
#941=CARTESIAN_POINT('',(4.2000000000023,8.57685839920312,65.));
#942=LINE('',#941,#940);
#943=CARTESIAN_POINT('',(4.2000000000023,8.57685839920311,28.6423805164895));
#944=VERTEX_POINT('',#943);
#945=CARTESIAN_POINT('',(4.20000000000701,8.5768583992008,17.8178159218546));
#946=VERTEX_POINT('',#945);
#947=EDGE_CURVE('E554',#944,#946,#942,.F.);
#948=ORIENTED_EDGE('',*,*,#947,.T.);
#949=CARTESIAN_POINT('',(0.,0.,17.8178159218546));
#950=DIRECTION('',(0.,0.,1.));
#951=DIRECTION('',(-1.,0.,0.));
#952=AXIS2_PLACEMENT_3D('',#949,#950,#951);
#953=CIRCLE('',#952,9.55);
#954=EDGE_CURVE('E1452',#946,#283,#953,.T.);
#955=ORIENTED_EDGE('',*,*,#954,.T.);
#956=ORIENTED_EDGE('',*,*,#286,.T.);
#957=ORIENTED_EDGE('',*,*,#600,.T.);
#958=ORIENTED_EDGE('',*,*,#520,.T.);
#959=ORIENTED_EDGE('',*,*,#342,.T.);
#960=CARTESIAN_POINT('',(-4.70000000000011,8.31339280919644,28.2167956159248));
#961=CARTESIAN_POINT('',(-4.47062989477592,8.4431012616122,28.2040017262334));
#962=CARTESIAN_POINT('',(-4.23579339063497,8.56330633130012,28.1927729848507));
#963=CARTESIAN_POINT('',(-3.75686557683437,8.78395289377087,28.1739395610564));
#964=CARTESIAN_POINT('',(-3.51277401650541,8.88439385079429,28.1663349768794));
#965=CARTESIAN_POINT('',(-3.0174799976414,9.06458335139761,28.1552545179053));
#966=CARTESIAN_POINT('',(-2.7662913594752,9.1443694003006,28.1517711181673));
#967=CARTESIAN_POINT('',(-2.25816922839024,9.28291460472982,28.1492727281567));
#968=CARTESIAN_POINT('',(-2.0012359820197,9.34167466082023,28.1502575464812));
#969=CARTESIAN_POINT('',(-1.48313785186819,9.43781252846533,28.1569537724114));
#970=CARTESIAN_POINT('',(-1.22196822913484,9.47516441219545,28.1626708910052));
#971=CARTESIAN_POINT('',(-0.697584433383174,9.52813313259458,28.1789660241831));
#972=CARTESIAN_POINT('',(-0.434370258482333,9.54374994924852,28.1895440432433));
#973=CARTESIAN_POINT('',(0.0922303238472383,9.55318541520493,28.2155568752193));
#974=CARTESIAN_POINT('',(0.355616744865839,9.54700206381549,28.2309921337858));
#975=CARTESIAN_POINT('',(0.880648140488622,9.51294675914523,28.2665804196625));
#976=CARTESIAN_POINT('',(1.14229322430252,9.48507617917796,28.286733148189));
#977=CARTESIAN_POINT('',(1.64525649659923,9.41042201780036,28.3300452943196));
#978=CARTESIAN_POINT('',(1.88679798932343,9.36497305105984,28.3529272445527));
#979=CARTESIAN_POINT('',(2.36531448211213,9.25570200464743,28.4022703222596));
#980=CARTESIAN_POINT('',(2.60228954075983,9.19188016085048,28.4287314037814));
#981=CARTESIAN_POINT('',(3.0704099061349,9.04627986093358,28.4848540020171));
#982=CARTESIAN_POINT('',(3.3015518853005,8.9644914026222,28.514517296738));
#983=CARTESIAN_POINT('',(3.75655851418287,8.78355292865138,28.5765447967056));
#984=CARTESIAN_POINT('',(3.98042333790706,8.68440332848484,28.6089089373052));
#985=CARTESIAN_POINT('',(4.20000000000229,8.57685839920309,28.6423805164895));
#986=B_SPLINE_CURVE_WITH_KNOTS('',3,(#960,#961,#962,#963,#964,#965,#966,#967,#968,#969,#970,
#971,#972,#973,#974,#975,#976,#977,#978,#979,#980,#981,#982,#983,#984,#985),.UNSPECIFIED.,.F.,
.F.,(4,2,2,2,2,2,2,2,2,2,2,2,4),(0.,0.79122391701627,1.58246927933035,2.37226765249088,
3.16203219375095,3.95275122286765,4.74347098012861,5.53426330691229,6.32500556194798,
7.0647878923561,7.80456072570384,8.54474644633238,9.28491445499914),.UNSPECIFIED.);
#987=EDGE_CURVE('E1239',#341,#944,#986,.T.);
#988=ORIENTED_EDGE('',*,*,#987,.T.);
#989=EDGE_LOOP('',(#948,#955,#956,#957,#958,#959,#988));
#990=FACE_BOUND('',#989,.T.);
#991=ADVANCED_FACE('F611',(#990),#938,.T.);
#992=CARTESIAN_POINT('',(-2.30000000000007,-19.1,71.3000000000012));
#993=DIRECTION('',(0.,-1.,0.));
#994=DIRECTION('',(1.,0.,0.));
#995=AXIS2_PLACEMENT_3D('',#992,#993,#994);
#996=CYLINDRICAL_SURFACE('',#995,43.1500000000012);
#997=ORIENTED_EDGE('',*,*,#148,.F.);
#998=DIRECTION('',(0.,-1.,0.));
#999=VECTOR('',#998,1.);
#1000=CARTESIAN_POINT('',(4.37639516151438,8.49051827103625,28.6696323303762));
#1001=LINE('',#1000,#999);
#1002=CARTESIAN_POINT('',(4.37639515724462,8.49051826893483,28.6696323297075));
#1003=VERTEX_POINT('',#1002);
#1004=EDGE_CURVE('E553',#1003,#30,#1001,.T.);
#1005=ORIENTED_EDGE('',*,*,#1004,.F.);
#1006=CARTESIAN_POINT('',(4.37639515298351,8.49051827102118,28.6696323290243));
#1007=CARTESIAN_POINT('',(4.34695885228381,8.50481101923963,28.6650223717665));
#1008=CARTESIAN_POINT('',(4.31754110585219,8.51915240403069,28.6604464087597));
#1009=CARTESIAN_POINT('',(4.25874272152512,8.547932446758,28.6513624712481));
#1010=CARTESIAN_POINT('',(4.22936208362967,8.56237110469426,28.6468544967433));
#1011=CARTESIAN_POINT('',(4.2000000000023,8.57685839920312,28.6423805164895));
#1012=B_SPLINE_CURVE_WITH_KNOTS('',3,(#1006,#1007,#1008,#1009,#1010,#1011),.UNSPECIFIED.,.F.,
.F.,(4,2,4),(0.,0.0991371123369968,0.198274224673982),.UNSPECIFIED.);
#1013=EDGE_CURVE('E557',#1003,#944,#1012,.T.);
#1014=ORIENTED_EDGE('',*,*,#1013,.T.);
#1015=ORIENTED_EDGE('',*,*,#987,.F.);
#1016=ORIENTED_EDGE('',*,*,#365,.F.);
#1017=CARTESIAN_POINT('',(4.20000000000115,-8.57685839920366,28.6423805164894));
#1018=CARTESIAN_POINT('',(3.96298924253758,-8.69294838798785,28.6062473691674));
#1019=CARTESIAN_POINT('',(3.72097660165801,-8.79925096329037,28.5714091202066));
#1020=CARTESIAN_POINT('',(3.2285761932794,-8.99158139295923,28.5049226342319));
#1021=CARTESIAN_POINT('',(2.97818764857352,-9.07760735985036,28.4732746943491));
#1022=CARTESIAN_POINT('',(2.47095556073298,-9.22858935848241,28.4138049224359));
#1023=CARTESIAN_POINT('',(2.2141185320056,-9.29356579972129,28.3859793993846));
#1024=CARTESIAN_POINT('',(1.69553653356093,-9.40201114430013,28.334594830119));
#1025=CARTESIAN_POINT('',(1.43379185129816,-9.44548130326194,28.3110355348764));
#1026=CARTESIAN_POINT('',(0.906801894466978,-9.51056314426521,28.2685124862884));
#1027=CARTESIAN_POINT('',(0.641551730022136,-9.53214007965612,28.2495560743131));
#1028=CARTESIAN_POINT('',(0.109873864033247,-9.55307303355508,28.2165235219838));
#1029=CARTESIAN_POINT('',(-0.156553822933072,-9.55242932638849,28.2024473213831));
#1030=CARTESIAN_POINT('',(-0.688540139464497,-9.52886560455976,28.179279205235));
#1031=CARTESIAN_POINT('',(-0.954099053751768,-9.50595382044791,28.1701854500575));
#1032=CARTESIAN_POINT('',(-1.4824771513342,-9.43799234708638,28.1569358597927));
#1033=CARTESIAN_POINT('',(-1.74529656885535,-9.39294456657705,28.1527795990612));
#1034=CARTESIAN_POINT('',(-2.24146544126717,-9.28635866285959,28.1493956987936));
#1035=CARTESIAN_POINT('',(-2.47523929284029,-9.22679771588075,28.1497366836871));
#1036=CARTESIAN_POINT('',(-2.93757271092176,-9.09017436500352,28.1540911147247));
#1037=CARTESIAN_POINT('',(-3.16613254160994,-9.01311284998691,28.1581043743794));
#1038=CARTESIAN_POINT('',(-3.61693408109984,-8.84185864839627,28.1695117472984));
#1039=CARTESIAN_POINT('',(-3.83916866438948,-8.74764746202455,28.1769095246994));
#1040=CARTESIAN_POINT('',(-4.27579202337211,-8.54273752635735,28.1947015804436));
#1041=CARTESIAN_POINT('',(-4.49018040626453,-8.4320379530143,28.2050960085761));
#1042=CARTESIAN_POINT('',(-4.70000000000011,-8.31339280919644,28.2167956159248));
#1043=B_SPLINE_CURVE_WITH_KNOTS('',3,(#1017,#1018,#1019,#1020,#1021,#1022,#1023,#1024,#1025,
#1026,#1027,#1028,#1029,#1030,#1031,#1032,#1033,#1034,#1035,#1036,#1037,#1038,#1039,#1040,#1041,
#1042),.UNSPECIFIED.,.F.,.F.,(4,2,2,2,2,2,2,2,2,2,2,2,4),(0.,0.798917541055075,1.59790942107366,
2.39612426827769,3.19429250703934,3.99372554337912,4.79314871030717,5.59227651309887,
6.3913354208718,7.1143549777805,7.83733781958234,8.56110523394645,9.28490883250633),.UNSPECIFIED.);
#1044=CARTESIAN_POINT('',(4.20000000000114,-8.57685839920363,28.6423805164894));
#1045=VERTEX_POINT('',#1044);
#1046=EDGE_CURVE('E1263',#1045,#358,#1043,.T.);
#1047=ORIENTED_EDGE('',*,*,#1046,.F.);
#1048=CARTESIAN_POINT('',(4.37639515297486,-8.49051827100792,28.6696323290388));
#1049=CARTESIAN_POINT('',(4.3469588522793,-8.50481101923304,28.6650223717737));
#1050=CARTESIAN_POINT('',(4.31754110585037,-8.51915240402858,28.660446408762));
#1051=CARTESIAN_POINT('',(4.25874272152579,-8.54793244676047,28.6513624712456));
#1052=CARTESIAN_POINT('',(4.22936208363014,-8.56237110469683,28.6468544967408));
#1053=CARTESIAN_POINT('',(4.20000000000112,-8.5768583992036,28.6423805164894));
#1054=B_SPLINE_CURVE_WITH_KNOTS('',3,(#1048,#1049,#1050,#1051,#1052,#1053),.UNSPECIFIED.,.F.,
.F.,(4,2,4),(0.,0.0991371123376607,0.198274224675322),.UNSPECIFIED.);
#1055=CARTESIAN_POINT('',(4.37639515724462,-8.49051826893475,28.6696323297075));
#1056=VERTEX_POINT('',#1055);
#1057=EDGE_CURVE('E1240',#1056,#1045,#1054,.T.);
#1058=ORIENTED_EDGE('',*,*,#1057,.F.);
#1059=DIRECTION('',(0.,-1.,0.));
#1060=VECTOR('',#1059,1.);
#1061=CARTESIAN_POINT('',(4.37639516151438,-0.314814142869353,28.6696323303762));
#1062=LINE('',#1061,#1060);
#1063=EDGE_CURVE('E552',#32,#1056,#1062,.T.);
#1064=ORIENTED_EDGE('',*,*,#1063,.F.);
#1065=EDGE_LOOP('',(#997,#1005,#1014,#1015,#1016,#1047,#1058,#1064));
#1066=FACE_BOUND('',#1065,.T.);
#1067=ADVANCED_FACE('F1053',(#1066),#996,.F.);
#1068=CARTESIAN_POINT('',(0.,0.,65.));
#1069=DIRECTION('',(0.,0.,1.));
#1070=DIRECTION('',(0.,-1.,0.));
#1071=AXIS2_PLACEMENT_3D('',#1068,#1069,#1070);
#1072=CYLINDRICAL_SURFACE('',#1071,9.55);
#1073=ORIENTED_EDGE('',*,*,#549,.T.);
#1074=ORIENTED_EDGE('',*,*,#579,.T.);
#1075=ORIENTED_EDGE('',*,*,#317,.T.);
#1076=CARTESIAN_POINT('',(0.,0.,17.8178159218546));
#1077=DIRECTION('',(0.,0.,1.));
#1078=DIRECTION('',(-1.,0.,0.));
#1079=AXIS2_PLACEMENT_3D('',#1076,#1077,#1078);
#1080=CIRCLE('',#1079,9.55);
#1081=CARTESIAN_POINT('',(4.19999999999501,-8.57685839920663,17.8178159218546));
#1082=VERTEX_POINT('',#1081);
#1083=EDGE_CURVE('E1353',#307,#1082,#1080,.T.);
#1084=ORIENTED_EDGE('',*,*,#1083,.T.);
#1085=DIRECTION('',(0.,0.,1.));
#1086=VECTOR('',#1085,1.);
#1087=CARTESIAN_POINT('',(4.20000000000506,-8.57685839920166,65.));
#1088=LINE('',#1087,#1086);
#1089=EDGE_CURVE('E545',#1082,#1045,#1088,.T.);
#1090=ORIENTED_EDGE('',*,*,#1089,.T.);
#1091=ORIENTED_EDGE('',*,*,#1046,.T.);
#1092=ORIENTED_EDGE('',*,*,#359,.T.);
#1093=EDGE_LOOP('',(#1073,#1074,#1075,#1084,#1090,#1091,#1092));
#1094=FACE_BOUND('',#1093,.T.);
#1095=ADVANCED_FACE('F322',(#1094),#1072,.T.);
#1096=CARTESIAN_POINT('',(62.,-2.04999999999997,65.));
#1097=DIRECTION('',(0.,0.,1.));
#1098=DIRECTION('',(0.,-1.,0.));
#1099=AXIS2_PLACEMENT_3D('',#1096,#1097,#1098);
#1100=CYLINDRICAL_SURFACE('',#1099,3.);
#1101=ORIENTED_EDGE('',*,*,#821,.T.);
#1102=CARTESIAN_POINT('',(62.5706996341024,-4.99521678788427,27.9474100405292));
#1103=CARTESIAN_POINT('',(62.635563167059,-4.98266332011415,27.9429062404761));
#1104=CARTESIAN_POINT('',(62.6998016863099,-4.96797815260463,27.9358857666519));
#1105=CARTESIAN_POINT('',(62.8264657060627,-4.93465124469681,27.9172170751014));
#1106=CARTESIAN_POINT('',(62.888893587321,-4.91601499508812,27.9055752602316));
#1107=CARTESIAN_POINT('',(63.0110100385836,-4.87523850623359,27.8781771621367));
#1108=CARTESIAN_POINT('',(63.0707180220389,-4.853130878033,27.8624583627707));
#1109=CARTESIAN_POINT('',(63.1876686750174,-4.80561803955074,27.8272711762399));
#1110=CARTESIAN_POINT('',(63.2449105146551,-4.78021173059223,27.8078015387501));
#1111=CARTESIAN_POINT('',(63.4119170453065,-4.69984416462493,27.7446162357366));
#1112=CARTESIAN_POINT('',(63.5177367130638,-4.64046965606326,27.6959415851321));
#1113=CARTESIAN_POINT('',(63.7179114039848,-4.51230992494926,27.5881603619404));
#1114=CARTESIAN_POINT('',(63.812238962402,-4.4435029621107,27.5290295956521));
#1115=CARTESIAN_POINT('',(63.9698423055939,-4.31444530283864,27.4164909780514));
#1116=CARTESIAN_POINT('',(64.0354072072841,-4.2555936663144,27.3646403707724));
#1117=CARTESIAN_POINT('',(64.1594933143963,-4.13425593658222,27.2568409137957));
#1118=CARTESIAN_POINT('',(64.2180106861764,-4.07176789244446,27.2008898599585));
#1119=CARTESIAN_POINT('',(64.3283250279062,-3.94369270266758,27.0853934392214));
#1120=CARTESIAN_POINT('',(64.3800971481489,-3.87809524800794,27.0258359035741));
#1121=CARTESIAN_POINT('',(64.4768498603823,-3.74469707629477,26.9038375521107));
#1122=CARTESIAN_POINT('',(64.5218337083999,-3.67689743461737,26.8413981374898));
#1123=CARTESIAN_POINT('',(64.5921203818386,-3.56127213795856,26.7339458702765));
#1124=CARTESIAN_POINT('',(64.6191679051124,-3.51385920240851,26.6896171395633));
#1125=CARTESIAN_POINT('',(64.6702275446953,-3.41850655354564,26.5997468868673));
#1126=CARTESIAN_POINT('',(64.6942384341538,-3.37056663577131,26.5542048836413));
#1127=CARTESIAN_POINT('',(64.7392844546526,-3.27439486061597,26.4618114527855));
#1128=CARTESIAN_POINT('',(64.7603150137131,-3.22616267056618,26.4149581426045));
#1129=CARTESIAN_POINT('',(64.799272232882,-3.13015949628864,26.3200780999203));
#1130=CARTESIAN_POINT('',(64.8172151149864,-3.08238742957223,26.2720591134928));
#1131=CARTESIAN_POINT('',(64.8501082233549,-2.98775119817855,26.1742284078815));
#1132=CARTESIAN_POINT('',(64.8650621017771,-2.94088598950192,26.1244189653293));
#1133=CARTESIAN_POINT('',(64.8851749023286,-2.87239583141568,26.0475914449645));
#1134=CARTESIAN_POINT('',(64.8914871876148,-2.8498906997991,26.0216595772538));
#1135=CARTESIAN_POINT('',(64.9033127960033,-2.80583844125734,25.9688230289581));
#1136=CARTESIAN_POINT('',(64.9088264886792,-2.78429087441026,25.9419188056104));
#1137=CARTESIAN_POINT('',(64.9164340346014,-2.75322555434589,25.9006340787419));
#1138=CARTESIAN_POINT('',(64.9188526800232,-2.74311022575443,25.8867637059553));
#1139=CARTESIAN_POINT('',(64.9234639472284,-2.7233949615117,25.858617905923));
#1140=CARTESIAN_POINT('',(64.9256565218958,-2.71379513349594,25.8443423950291));
#1141=CARTESIAN_POINT('',(64.9297947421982,-2.69528488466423,25.8153253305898));
#1142=CARTESIAN_POINT('',(64.9317405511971,-2.68637400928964,25.8005840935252));
#1143=CARTESIAN_POINT('',(64.9353583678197,-2.66947242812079,25.7705543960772));
#1144=CARTESIAN_POINT('',(64.9370304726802,-2.66148139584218,25.7552661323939));
#1145=CARTESIAN_POINT('',(64.9406720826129,-2.64376596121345,25.717817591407));
#1146=CARTESIAN_POINT('',(64.9424928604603,-2.63462745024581,25.6953554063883));
#1147=CARTESIAN_POINT('',(64.9453712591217,-2.61995303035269,25.6492664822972));
#1148=CARTESIAN_POINT('',(64.946432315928,-2.6144009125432,25.6256455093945));
#1149=CARTESIAN_POINT('',(64.9472482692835,-2.61011469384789,25.5937262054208));
#1150=CARTESIAN_POINT('',(64.9474024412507,-2.60930241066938,25.5856985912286));
#1151=CARTESIAN_POINT('',(64.9476089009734,-2.60821326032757,25.5695893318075));
#1152=CARTESIAN_POINT('',(64.9476609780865,-2.60793750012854,25.5615076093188));
#1153=CARTESIAN_POINT('',(64.9476609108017,-2.60793830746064,25.5534224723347));
#1154=B_SPLINE_CURVE_WITH_KNOTS('',3,(#1102,#1103,#1104,#1105,#1106,#1107,#1108,#1109,#1110,
#1111,#1112,#1113,#1114,#1115,#1116,#1117,#1118,#1119,#1120,#1121,#1122,#1123,#1124,#1125,#1126,
#1127,#1128,#1129,#1130,#1131,#1132,#1133,#1134,#1135,#1136,#1137,#1138,#1139,#1140,#1141,#1142,
#1143,#1144,#1145,#1146,#1147,#1148,#1149,#1150,#1151,#1152,#1153),.UNSPECIFIED.,.F.,.F.,(4,2,2,
2,2,2,2,2,2,2,2,2,2,2,2,2,2,2,2,2,2,2,2,2,2,4),(0.,0.198523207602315,0.396772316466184,
0.593259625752,0.789812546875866,1.18043420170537,1.57197180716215,1.8782575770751,
2.18470921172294,2.49225968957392,2.79966217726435,3.01054330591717,3.22150936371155,
3.43279562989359,3.64293550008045,3.85281701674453,3.95752882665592,4.06219202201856,
4.11419127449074,4.16620134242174,4.21817679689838,4.27013374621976,4.34288099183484,
4.41529710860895,4.43949139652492,4.46373554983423),.UNSPECIFIED.);
#1155=CARTESIAN_POINT('',(62.5706996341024,-4.99521678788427,27.9474100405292));
#1156=VERTEX_POINT('',#1155);
#1157=EDGE_CURVE('E333',#1156,#814,#1154,.T.);
#1158=ORIENTED_EDGE('',*,*,#1157,.F.);
#1159=CARTESIAN_POINT('',(62.5706996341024,-4.99521678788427,27.9474100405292));
#1160=CARTESIAN_POINT('',(62.4908632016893,-5.01067552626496,27.9529668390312));
#1161=CARTESIAN_POINT('',(62.4106664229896,-5.02286415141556,27.9585479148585));
#1162=CARTESIAN_POINT('',(62.2495521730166,-5.04070117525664,27.9697586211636));
#1163=CARTESIAN_POINT('',(62.1686347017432,-5.04634957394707,27.9753882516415));
#1164=CARTESIAN_POINT('',(62.0873568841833,-5.04872785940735,27.9810421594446));
#1165=B_SPLINE_CURVE_WITH_KNOTS('',3,(#1159,#1160,#1161,#1162,#1163,#1164),.UNSPECIFIED.,.F.,
.F.,(4,2,4),(0.,0.243928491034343,0.487856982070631),.UNSPECIFIED.);
#1166=CARTESIAN_POINT('',(62.0873568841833,-5.04872785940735,27.9810421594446));
#1167=VERTEX_POINT('',#1166);
#1168=EDGE_CURVE('E31',#1156,#1167,#1165,.T.);
#1169=ORIENTED_EDGE('',*,*,#1168,.T.);
#1170=DIRECTION('',(0.,0.,1.));
#1171=VECTOR('',#1170,1.);
#1172=CARTESIAN_POINT('',(62.0873568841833,-5.04872785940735,65.));
#1173=LINE('',#1172,#1171);
#1174=CARTESIAN_POINT('',(62.0873568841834,-5.04872785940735,19.0696484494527));
#1175=VERTEX_POINT('',#1174);
#1176=EDGE_CURVE('E536',#1167,#1175,#1173,.F.);
#1177=ORIENTED_EDGE('',*,*,#1176,.T.);
#1178=CARTESIAN_POINT('',(62.9089199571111,-4.90899711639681,19.9732884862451));
#1179=CARTESIAN_POINT('',(62.8786208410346,-4.91862956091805,19.9327431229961));
#1180=CARTESIAN_POINT('',(62.8477922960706,-4.92790019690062,19.8925055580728));
#1181=CARTESIAN_POINT('',(62.7851778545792,-4.94560900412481,19.812785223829));
#1182=CARTESIAN_POINT('',(62.7533949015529,-4.95404944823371,19.7733006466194));
#1183=CARTESIAN_POINT('',(62.6888668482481,-4.9700282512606,19.6950750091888));
#1184=CARTESIAN_POINT('',(62.6561238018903,-4.9775683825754,19.6563326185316));
#1185=CARTESIAN_POINT('',(62.589668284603,-4.99167365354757,19.5795828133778));
#1186=CARTESIAN_POINT('',(62.5559569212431,-4.99823985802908,19.5415746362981));
#1187=CARTESIAN_POINT('',(62.4875411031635,-5.01032273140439,19.4662721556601));
#1188=CARTESIAN_POINT('',(62.4528363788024,-5.01583911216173,19.4289780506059));
#1189=CARTESIAN_POINT('',(62.3824363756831,-5.0257363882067,19.3551181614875));
#1190=CARTESIAN_POINT('',(62.3467402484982,-5.03011627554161,19.3185530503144));
#1191=CARTESIAN_POINT('',(62.2743453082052,-5.03765154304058,19.2461533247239));
#1192=CARTESIAN_POINT('',(62.2376446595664,-5.04080449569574,19.2103202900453));
#1193=CARTESIAN_POINT('',(62.1632276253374,-5.04578897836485,19.1393895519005));
#1194=CARTESIAN_POINT('',(62.1255083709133,-5.04761625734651,19.1042945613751));
#1195=CARTESIAN_POINT('',(62.0873568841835,-5.04872785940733,19.0696484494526));
#1196=B_SPLINE_CURVE_WITH_KNOTS('',3,(#1178,#1179,#1180,#1181,#1182,#1183,#1184,#1185,#1186,
#1187,#1188,#1189,#1190,#1191,#1192,#1193,#1194,#1195),.UNSPECIFIED.,.F.,.F.,(4,2,2,2,2,2,2,2,
4),(0.,0.154569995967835,0.308704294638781,0.462529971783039,0.616186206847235,
0.769884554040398,0.923718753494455,1.0778557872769,1.23248493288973),.UNSPECIFIED.);
#1197=EDGE_CURVE('E342',#729,#1175,#1196,.T.);
#1198=ORIENTED_EDGE('',*,*,#1197,.F.);
#1199=ORIENTED_EDGE('',*,*,#771,.T.);
#1200=ORIENTED_EDGE('',*,*,#704,.T.);
#1201=EDGE_LOOP('',(#1101,#1158,#1169,#1177,#1198,#1199,#1200));
#1202=FACE_BOUND('',#1201,.T.);
#1203=ADVANCED_FACE('F317',(#1202),#1100,.T.);
#1204=CARTESIAN_POINT('',(0.,0.,23.5));
#1205=DIRECTION('',(0.,0.,-1.));
#1206=DIRECTION('',(0.,1.,0.));
#1207=AXIS2_PLACEMENT_3D('',#1204,#1205,#1206);
#1208=TOROIDAL_SURFACE('',#1207,58.2460601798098,6.);
#1209=ORIENTED_EDGE('',*,*,#852,.T.);
#1210=ORIENTED_EDGE('',*,*,#730,.T.);
#1211=ORIENTED_EDGE('',*,*,#1197,.T.);
#1212=CARTESIAN_POINT('',(62.0873568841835,-5.04872785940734,19.0696484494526));
#1213=CARTESIAN_POINT('',(61.9615814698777,-5.05239186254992,18.955402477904));
#1214=CARTESIAN_POINT('',(61.830950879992,-5.05619730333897,18.8465145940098));
#1215=CARTESIAN_POINT('',(61.5609781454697,-5.06406196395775,18.640153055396));
#1216=CARTESIAN_POINT('',(61.4216362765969,-5.06812117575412,18.5426790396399));
#1217=CARTESIAN_POINT('',(61.1350609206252,-5.07646949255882,18.3597269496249));
#1218=CARTESIAN_POINT('',(60.9878182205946,-5.08075886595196,18.2742633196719));
#1219=CARTESIAN_POINT('',(60.6866648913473,-5.08953185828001,18.1160595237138));
#1220=CARTESIAN_POINT('',(60.5327545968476,-5.09401546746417,18.0433187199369));
#1221=CARTESIAN_POINT('',(60.2192797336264,-5.10314740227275,17.9110204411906));
#1222=CARTESIAN_POINT('',(60.0597122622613,-5.107795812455,17.8514698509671));
#1223=CARTESIAN_POINT('',(59.7361362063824,-5.11722200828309,17.7460050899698));
#1224=CARTESIAN_POINT('',(59.5721276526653,-5.12199979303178,17.7000908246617));
#1225=CARTESIAN_POINT('',(59.2412191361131,-5.13163959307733,17.6222960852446));
#1226=CARTESIAN_POINT('',(59.074326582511,-5.1365013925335,17.5903839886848));
#1227=CARTESIAN_POINT('',(58.7385277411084,-5.14628365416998,17.5406666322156));
#1228=CARTESIAN_POINT('',(58.5696226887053,-5.15120408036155,17.5228531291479));
#1229=CARTESIAN_POINT('',(58.336382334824,-5.15799867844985,17.5080895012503));
#1230=CARTESIAN_POINT('',(58.2723877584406,-5.15986292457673,17.5050545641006));
#1231=CARTESIAN_POINT('',(58.1443968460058,-5.16359146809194,17.5010109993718));
#1232=CARTESIAN_POINT('',(58.0804005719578,-5.16545576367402,17.5000004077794));
#1233=CARTESIAN_POINT('',(58.0163970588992,-5.16732027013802,17.5));
#1234=B_SPLINE_CURVE_WITH_KNOTS('',3,(#1212,#1213,#1214,#1215,#1216,#1217,#1218,#1219,#1220,
#1221,#1222,#1223,#1224,#1225,#1226,#1227,#1228,#1229,#1230,#1231,#1232,#1233),.UNSPECIFIED.,
.F.,.F.,(4,2,2,2,2,2,2,2,2,2,4),(0.,0.509707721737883,1.01939931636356,1.52969874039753,
2.03997257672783,2.55051213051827,3.06104814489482,3.57042515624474,4.0795041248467,
4.27176027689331,4.46382981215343),.UNSPECIFIED.);
#1235=CARTESIAN_POINT('',(58.0163970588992,-5.16732027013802,17.5));
#1236=VERTEX_POINT('',#1235);
#1237=EDGE_CURVE('E533',#1175,#1236,#1234,.T.);
#1238=ORIENTED_EDGE('',*,*,#1237,.T.);
#1239=CARTESIAN_POINT('',(0.,0.,17.5));
#1240=DIRECTION('',(0.,0.,1.));
#1241=DIRECTION('',(0.996057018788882,-0.0887153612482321,0.));
#1242=AXIS2_PLACEMENT_3D('',#1239,#1240,#1241);
#1243=CIRCLE('',#1242,58.2460601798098);
#1244=CARTESIAN_POINT('',(58.0163970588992,5.16732027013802,17.5));
#1245=VERTEX_POINT('',#1244);
#1246=EDGE_CURVE('E1214',#1236,#1245,#1243,.T.);
#1247=ORIENTED_EDGE('',*,*,#1246,.T.);
#1248=CARTESIAN_POINT('',(58.0163970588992,5.16732027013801,17.5));
#1249=CARTESIAN_POINT('',(58.1867903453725,5.16235648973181,17.4999825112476));
#1250=CARTESIAN_POINT('',(58.3571817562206,5.15739276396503,17.5071632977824));
#1251=CARTESIAN_POINT('',(58.6967651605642,5.14750025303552,17.535801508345));
#1252=CARTESIAN_POINT('',(58.8659571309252,5.14257146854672,17.5572592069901));
#1253=CARTESIAN_POINT('',(59.2022182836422,5.13277573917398,17.6143787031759));
#1254=CARTESIAN_POINT('',(59.369283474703,5.12790891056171,17.650064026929));
#1255=CARTESIAN_POINT('',(59.6998030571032,5.11828044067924,17.7353906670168));
#1256=CARTESIAN_POINT('',(59.8632576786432,5.11351879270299,17.7850310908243));
#1257=CARTESIAN_POINT('',(60.1855244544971,5.104130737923,17.8979773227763));
#1258=CARTESIAN_POINT('',(60.3443328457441,5.09950444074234,17.9612938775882));
#1259=CARTESIAN_POINT('',(60.6560290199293,5.09042432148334,18.1011348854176));
#1260=CARTESIAN_POINT('',(60.8089168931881,5.08597049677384,18.1776591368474));
#1261=CARTESIAN_POINT('',(61.107292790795,5.07727841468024,18.3431756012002));
#1262=CARTESIAN_POINT('',(61.2527981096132,5.07303965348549,18.4321366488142));
#1263=CARTESIAN_POINT('',(61.5357002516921,5.0647983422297,18.6220169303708));
#1264=CARTESIAN_POINT('',(61.6731019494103,5.06079565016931,18.7229288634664));
#1265=CARTESIAN_POINT('',(61.854087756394,5.05552329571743,18.8680441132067));
#1266=CARTESIAN_POINT('',(61.9016310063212,5.05413829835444,18.907380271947));
#1267=CARTESIAN_POINT('',(61.9954446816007,5.05140538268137,18.9874593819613));
#1268=CARTESIAN_POINT('',(62.0417162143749,5.05005743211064,19.0282010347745));
#1269=CARTESIAN_POINT('',(62.0873568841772,5.04872785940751,19.0696484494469));
#1270=B_SPLINE_CURVE_WITH_KNOTS('',3,(#1248,#1249,#1250,#1251,#1252,#1253,#1254,#1255,#1256,
#1257,#1258,#1259,#1260,#1261,#1262,#1263,#1264,#1265,#1266,#1267,#1268,#1269),.UNSPECIFIED.,
.F.,.F.,(4,2,2,2,2,2,2,2,2,2,4),(0.,0.511242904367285,1.02249564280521,1.53459729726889,
2.0466662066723,2.55913897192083,3.0716039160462,3.58280695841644,4.09369930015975,
4.27884339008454,4.46382078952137),.UNSPECIFIED.);
#1271=EDGE_CURVE('E569',#1245,#851,#1270,.T.);
#1272=ORIENTED_EDGE('',*,*,#1271,.T.);
#1273=EDGE_LOOP('',(#1209,#1210,#1211,#1238,#1247,#1272));
#1274=FACE_BOUND('',#1273,.T.);
#1275=ADVANCED_FACE('F321',(#1274),#1208,.T.);
#1276=CARTESIAN_POINT('',(58.2460601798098,0.,17.5));
#1277=DIRECTION('',(0.,0.,1.));
#1278=DIRECTION('',(0.,-1.,0.));
#1279=AXIS2_PLACEMENT_3D('',#1276,#1277,#1278);
#1280=PLANE('',#1279);
#1281=DIRECTION('',(-0.999575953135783,-0.0291189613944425,0.));
#1282=VECTOR('',#1281,1.);
#1283=CARTESIAN_POINT('',(26.,-6.1,17.5));
#1284=LINE('',#1283,#1282);
#1285=CARTESIAN_POINT('',(55.4898810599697,-5.24092100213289,17.5));
#1286=VERTEX_POINT('',#1285);
#1287=EDGE_CURVE('E529',#1236,#1286,#1284,.T.);
#1288=ORIENTED_EDGE('',*,*,#1287,.T.);
#1289=CARTESIAN_POINT('',(0.,0.,17.5));
#1290=DIRECTION('',(0.,0.,-1.));
#1291=DIRECTION('',(0.995569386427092,0.0940297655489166,0.));
#1292=AXIS2_PLACEMENT_3D('',#1289,#1290,#1291);
#1293=CIRCLE('',#1292,55.7368294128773);
#1294=CARTESIAN_POINT('',(55.4898810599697,5.24092100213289,17.5));
#1295=VERTEX_POINT('',#1294);
#1296=EDGE_CURVE('E1181',#1295,#1286,#1293,.T.);
#1297=ORIENTED_EDGE('',*,*,#1296,.F.);
#1298=DIRECTION('',(0.999575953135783,-0.0291189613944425,0.));
#1299=VECTOR('',#1298,1.);
#1300=CARTESIAN_POINT('',(62.0873568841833,5.04872785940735,17.5));
#1301=LINE('',#1300,#1299);
#1302=EDGE_CURVE('E570',#1295,#1245,#1301,.T.);
#1303=ORIENTED_EDGE('',*,*,#1302,.T.);
#1304=ORIENTED_EDGE('',*,*,#1246,.F.);
#1305=EDGE_LOOP('',(#1288,#1297,#1303,#1304));
#1306=FACE_BOUND('',#1305,.T.);
#1307=ADVANCED_FACE('F1032',(#1306),#1280,.F.);
#1308=CARTESIAN_POINT('',(0.,0.,26.7));
#1309=DIRECTION('',(0.,0.,-1.));
#1310=DIRECTION('',(0.,1.,0.));
#1311=AXIS2_PLACEMENT_3D('',#1308,#1309,#1310);
#1312=TOROIDAL_SURFACE('',#1311,55.7368294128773,9.2);
#1313=CARTESIAN_POINT('',(50.8163077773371,5.37706833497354,18.7539435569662));
#1314=CARTESIAN_POINT('',(51.0459585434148,5.37037830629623,18.6210561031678));
#1315=CARTESIAN_POINT('',(51.2813079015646,5.36352227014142,18.4980372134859));
#1316=CARTESIAN_POINT('',(51.761687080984,5.34952819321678,18.2724624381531));
#1317=CARTESIAN_POINT('',(52.0067194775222,5.34239007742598,18.1699120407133));
#1318=CARTESIAN_POINT('',(52.4992638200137,5.3280416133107,17.9880509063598));
#1319=CARTESIAN_POINT('',(52.7466088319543,5.32083612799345,17.9082874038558));
#1320=CARTESIAN_POINT('',(53.2469739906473,5.30625983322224,17.7696716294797));
#1321=CARTESIAN_POINT('',(53.4999918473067,5.29888909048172,17.7108110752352));
#1322=CARTESIAN_POINT('',(54.0390528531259,5.28318553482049,17.6088923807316));
#1323=CARTESIAN_POINT('',(54.3255819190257,5.27483856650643,17.5683896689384));
#1324=CARTESIAN_POINT('',(54.9046823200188,5.25796861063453,17.5137572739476));
#1325=CARTESIAN_POINT('',(55.1972846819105,5.24944471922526,17.4999565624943));
#1326=CARTESIAN_POINT('',(55.4898810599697,5.24092100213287,17.5));
#1327=B_SPLINE_CURVE_WITH_KNOTS('',3,(#1313,#1314,#1315,#1316,#1317,#1318,#1319,#1320,#1321,
#1322,#1323,#1324,#1325,#1326),.UNSPECIFIED.,.F.,.F.,(4,2,2,2,2,2,4),(0.,0.795985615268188,
1.59218437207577,2.37124299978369,3.14999259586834,4.01722632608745,4.89507809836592),.UNSPECIFIED.);
#1328=CARTESIAN_POINT('',(50.8163077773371,5.37706833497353,18.7539435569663));
#1329=VERTEX_POINT('',#1328);
#1330=EDGE_CURVE('E573',#1329,#1295,#1327,.T.);
#1331=ORIENTED_EDGE('',*,*,#1330,.T.);
#1332=ORIENTED_EDGE('',*,*,#1296,.T.);
#1333=CARTESIAN_POINT('',(55.4898810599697,-5.24092100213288,17.5));
#1334=CARTESIAN_POINT('',(55.2245816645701,-5.24864952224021,17.4999719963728));
#1335=CARTESIAN_POINT('',(54.9592852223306,-5.2563779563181,17.51131057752));
#1336=CARTESIAN_POINT('',(54.430539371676,-5.27178101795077,17.5565109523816));
#1337=CARTESIAN_POINT('',(54.1670905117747,-5.27945562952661,17.5903791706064));
#1338=CARTESIAN_POINT('',(53.6496682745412,-5.29452881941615,17.6794587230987));
#1339=CARTESIAN_POINT('',(53.3956130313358,-5.30192978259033,17.7341945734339));
#1340=CARTESIAN_POINT('',(52.8930467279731,-5.31657019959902,17.8646112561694));
#1341=CARTESIAN_POINT('',(52.6445334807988,-5.32380971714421,17.9402836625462));
#1342=CARTESIAN_POINT('',(52.1268271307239,-5.33889118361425,18.1218541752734));
#1343=CARTESIAN_POINT('',(51.8584915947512,-5.34670815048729,18.2302092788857));
#1344=CARTESIAN_POINT('',(51.329798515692,-5.36210967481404,18.4728185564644));
#1345=CARTESIAN_POINT('',(51.0695789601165,-5.36969021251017,18.6073737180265));
#1346=CARTESIAN_POINT('',(50.8163077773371,-5.37706833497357,18.7539435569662));
#1347=B_SPLINE_CURVE_WITH_KNOTS('',3,(#1333,#1334,#1335,#1336,#1337,#1338,#1339,#1340,#1341,
#1342,#1343,#1344,#1345,#1346),.UNSPECIFIED.,.F.,.F.,(4,2,2,2,2,2,4),(0.,0.795990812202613,
1.59220870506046,2.37127469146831,3.15002759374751,4.0172412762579,4.89507773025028),.UNSPECIFIED.);
#1348=CARTESIAN_POINT('',(50.8163077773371,-5.37706833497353,18.7539435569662));
#1349=VERTEX_POINT('',#1348);
#1350=EDGE_CURVE('E532',#1286,#1349,#1347,.T.);
#1351=ORIENTED_EDGE('',*,*,#1350,.T.);
#1352=CARTESIAN_POINT('',(0.,0.,18.7539435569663));
#1353=DIRECTION('',(0.,0.,-1.));
#1354=DIRECTION('',(0.,1.,0.));
#1355=AXIS2_PLACEMENT_3D('',#1352,#1353,#1354);
#1356=CIRCLE('',#1355,51.1);
#1357=EDGE_CURVE('E1200',#1349,#1329,#1356,.F.);
#1358=ORIENTED_EDGE('',*,*,#1357,.T.);
#1359=EDGE_LOOP('',(#1331,#1332,#1351,#1358));
#1360=FACE_BOUND('',#1359,.T.);
#1361=ADVANCED_FACE('F1022',(#1360),#1312,.T.);
#1362=CARTESIAN_POINT('',(0.,0.,12.6691039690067));
#1363=DIRECTION('',(0.,0.,-1.));
#1364=DIRECTION('',(0.,1.,0.));
#1365=AXIS2_PLACEMENT_3D('',#1362,#1363,#1364);
#1366=TOROIDAL_SURFACE('',#1365,47.6395481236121,6.9999999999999);
#1367=CARTESIAN_POINT('',(50.8163077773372,-5.37706833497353,18.7539435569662));
#1368=CARTESIAN_POINT('',(50.6406084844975,-5.38218668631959,18.8530289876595));
#1369=CARTESIAN_POINT('',(50.4606536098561,-5.38742900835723,18.9445538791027));
#1370=CARTESIAN_POINT('',(50.0935242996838,-5.39812396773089,19.1119756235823));
#1371=CARTESIAN_POINT('',(49.9063467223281,-5.40357669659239,19.1878655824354));
#1372=CARTESIAN_POINT('',(49.5297226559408,-5.41454825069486,19.3221734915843));
#1373=CARTESIAN_POINT('',(49.3403815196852,-5.42006400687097,19.3808876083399));
#1374=CARTESIAN_POINT('',(48.9575590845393,-5.43121612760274,19.4822866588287));
#1375=CARTESIAN_POINT('',(48.7640802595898,-5.43685242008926,19.5249809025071));
#1376=CARTESIAN_POINT('',(48.4404670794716,-5.44627969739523,19.5823723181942));
#1377=CARTESIAN_POINT('',(48.3111265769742,-5.45004755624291,19.601653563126));
#1378=CARTESIAN_POINT('',(48.0507781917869,-5.45763184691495,19.6331780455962));
#1379=CARTESIAN_POINT('',(47.9197649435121,-5.46144843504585,19.6453769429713));
#1380=CARTESIAN_POINT('',(47.7885006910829,-5.46527233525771,19.6539435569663));
#1381=B_SPLINE_CURVE_WITH_KNOTS('',3,(#1367,#1368,#1369,#1370,#1371,#1372,#1373,#1374,#1375,
#1376,#1377,#1378,#1379,#1380),.UNSPECIFIED.,.F.,.F.,(4,2,2,2,2,2,4),(0.,0.605146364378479,
1.21055899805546,1.80481657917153,2.3987282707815,2.79101670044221,3.18573534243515),.UNSPECIFIED.);
#1382=CARTESIAN_POINT('',(47.7885006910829,-5.46527233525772,19.6539435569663));
#1383=VERTEX_POINT('',#1382);
#1384=EDGE_CURVE('E1463',#1349,#1383,#1381,.T.);
#1385=ORIENTED_EDGE('',*,*,#1384,.T.);
#1386=CARTESIAN_POINT('',(0.,0.,19.6539435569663));
#1387=DIRECTION('',(0.,0.,1.));
#1388=DIRECTION('',(0.,-1.,0.));
#1389=AXIS2_PLACEMENT_3D('',#1386,#1387,#1388);
#1390=CIRCLE('',#1389,48.1000000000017);
#1391=CARTESIAN_POINT('',(47.7885006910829,5.46527233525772,19.6539435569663));
#1392=VERTEX_POINT('',#1391);
#1393=EDGE_CURVE('E1356',#1383,#1392,#1390,.T.);
#1394=ORIENTED_EDGE('',*,*,#1393,.T.);
#1395=CARTESIAN_POINT('',(47.7885006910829,5.46527233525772,19.6539435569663));
#1396=CARTESIAN_POINT('',(47.9897604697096,5.45940937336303,19.6408280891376));
#1397=CARTESIAN_POINT('',(48.1904639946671,5.45356261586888,19.6191380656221));
#1398=CARTESIAN_POINT('',(48.5894189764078,5.44194053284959,19.5588227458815));
#1399=CARTESIAN_POINT('',(48.7876691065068,5.43616524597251,19.5201886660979));
#1400=CARTESIAN_POINT('',(49.1765352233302,5.42483706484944,19.4270824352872));
#1401=CARTESIAN_POINT('',(49.3672245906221,5.41928203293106,19.3729165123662));
#1402=CARTESIAN_POINT('',(49.7433183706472,5.40832592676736,19.2488727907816));
#1403=CARTESIAN_POINT('',(49.9287259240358,5.40292476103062,19.1790045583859));
#1404=CARTESIAN_POINT('',(50.2311634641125,5.39411435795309,19.0503338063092));
#1405=CARTESIAN_POINT('',(50.3500387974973,5.39065136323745,18.9958266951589));
#1406=CARTESIAN_POINT('',(50.5853222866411,5.38379724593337,18.8799579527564));
#1407=CARTESIAN_POINT('',(50.7017105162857,5.38040670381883,18.8185558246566));
#1408=CARTESIAN_POINT('',(50.8163077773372,5.37706833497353,18.7539435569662));
#1409=B_SPLINE_CURVE_WITH_KNOTS('',3,(#1395,#1396,#1397,#1398,#1399,#1400,#1401,#1402,#1403,
#1404,#1405,#1406,#1407,#1408),.UNSPECIFIED.,.F.,.F.,(4,2,2,2,2,2,4),(0.,0.605140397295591,
1.21059486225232,1.80484837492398,2.39874082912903,2.7910200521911,3.18573738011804),.UNSPECIFIED.);
#1410=EDGE_CURVE('E1460',#1392,#1329,#1409,.T.);
#1411=ORIENTED_EDGE('',*,*,#1410,.T.);
#1412=ORIENTED_EDGE('',*,*,#1357,.F.);
#1413=EDGE_LOOP('',(#1385,#1394,#1411,#1412));
#1414=FACE_BOUND('',#1413,.T.);
#1415=ADVANCED_FACE('F587',(#1414),#1366,.F.);
#1416=CARTESIAN_POINT('',(0.,0.,-155.000000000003));
#1417=DIRECTION('',(0.,0.,-1.));
#1418=DIRECTION('',(0.,1.,0.));
#1419=AXIS2_PLACEMENT_3D('',#1416,#1417,#1418);
#1420=DEGENERATE_TOROIDAL_SURFACE('',#1419,37.1,175.000000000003,.T.);
#1421=ORIENTED_EDGE('',*,*,#786,.F.);
#1422=ORIENTED_EDGE('',*,*,#297,.F.);
#1423=ORIENTED_EDGE('',*,*,#954,.F.);
#1424=CARTESIAN_POINT('',(4.20000000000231,8.57685839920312,17.8178159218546));
#1425=CARTESIAN_POINT('',(4.37114779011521,8.49241339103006,17.8177185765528));
#1426=CARTESIAN_POINT('',(4.54307025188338,8.40955197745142,17.8188275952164));
#1427=CARTESIAN_POINT('',(4.88838698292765,8.24703103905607,17.823405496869));
#1428=CARTESIAN_POINT('',(5.06178122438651,8.167371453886,17.8268743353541));
#1429=CARTESIAN_POINT('',(5.58397106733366,7.93328492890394,17.8407388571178));
#1430=CARTESIAN_POINT('',(5.93486625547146,7.78370459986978,17.8545925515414));
#1431=CARTESIAN_POINT('',(6.64120336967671,7.49787651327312,17.8904902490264));
#1432=CARTESIAN_POINT('',(6.99664046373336,7.36161573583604,17.9125261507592));
#1433=CARTESIAN_POINT('',(7.7118754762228,7.10240768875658,17.9633608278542));
#1434=CARTESIAN_POINT('',(8.0716736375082,6.97946116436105,17.9921599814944));
#1435=CARTESIAN_POINT('',(8.79532208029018,6.74694041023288,18.0549883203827));
#1436=CARTESIAN_POINT('',(9.15917445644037,6.63737347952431,18.0890203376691));
#1437=CARTESIAN_POINT('',(9.89030756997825,6.43177282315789,18.1608268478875));
#1438=CARTESIAN_POINT('',(10.2575882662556,6.33573893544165,18.1986012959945));
#1439=CARTESIAN_POINT('',(10.9952642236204,6.15725278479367,18.2766085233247));
#1440=CARTESIAN_POINT('',(11.3656601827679,6.07480365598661,18.3168418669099));
#1441=CARTESIAN_POINT('',(12.1090830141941,5.9235798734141,18.3986788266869));
#1442=CARTESIAN_POINT('',(12.4821099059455,5.85480532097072,18.4402824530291));
#1443=CARTESIAN_POINT('',(13.2293702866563,5.73116428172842,18.5238686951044));
#1444=CARTESIAN_POINT('',(13.6035977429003,5.67626051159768,18.5658499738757));
#1445=CARTESIAN_POINT('',(14.3538126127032,5.58017948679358,18.6496119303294));
#1446=CARTESIAN_POINT('',(14.7298000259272,5.53900222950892,18.6913926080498));
#1447=CARTESIAN_POINT('',(15.8597711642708,5.43614982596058,18.8155811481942));
#1448=CARTESIAN_POINT('',(16.6158762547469,5.39513544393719,18.896848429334));
#1449=CARTESIAN_POINT('',(18.1283509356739,5.36858591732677,19.0530659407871));
#1450=CARTESIAN_POINT('',(18.8847180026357,5.38295877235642,19.1280264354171));
#1451=CARTESIAN_POINT('',(20.3949229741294,5.46704791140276,19.2699339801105));
#1452=CARTESIAN_POINT('',(21.1487617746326,5.53674190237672,19.336884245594));
#1453=CARTESIAN_POINT('',(22.2680871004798,5.68173764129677,19.4299422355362));
#1454=CARTESIAN_POINT('',(22.6361030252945,5.73616166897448,19.4595050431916));
#1455=CARTESIAN_POINT('',(23.3698180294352,5.85820291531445,19.5163387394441));
#1456=CARTESIAN_POINT('',(23.7355187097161,5.92580967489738,19.5436114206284));
#1457=CARTESIAN_POINT('',(24.1,6.,19.5697166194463));
#1458=B_SPLINE_CURVE_WITH_KNOTS('',3,(#1424,#1425,#1426,#1427,#1428,#1429,#1430,#1431,#1432,
#1433,#1434,#1435,#1436,#1437,#1438,#1439,#1440,#1441,#1442,#1443,#1444,#1445,#1446,#1447,#1448,
#1449,#1450,#1451,#1452,#1453,#1454,#1455,#1456,#1457),.UNSPECIFIED.,.F.,.F.,(4,2,2,2,2,2,2,2,2,
2,2,2,2,2,2,2,4),(0.,0.572515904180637,1.145021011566,2.28972217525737,3.43329296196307,
4.57692772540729,5.7211836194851,6.8654258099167,8.0099316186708,9.15444590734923,
10.2958503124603,11.4372545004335,13.719719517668,15.9983949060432,18.2761525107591,
19.3955142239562,20.5139914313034),.UNSPECIFIED.);
#1459=CARTESIAN_POINT('',(24.1,6.,19.5697166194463));
#1460=VERTEX_POINT('',#1459);
#1461=EDGE_CURVE('E561',#946,#1460,#1458,.T.);
#1462=ORIENTED_EDGE('',*,*,#1461,.T.);
#1463=CARTESIAN_POINT('',(26.,6.1,19.691054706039));
#1464=CARTESIAN_POINT('',(25.8410773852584,6.11060773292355,19.6819939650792));
#1465=CARTESIAN_POINT('',(25.6818540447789,6.11645694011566,19.6726566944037));
#1466=CARTESIAN_POINT('',(25.3639375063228,6.11864488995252,19.653475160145));
#1467=CARTESIAN_POINT('',(25.2052444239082,6.11501717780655,19.6436328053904));
#1468=CARTESIAN_POINT('',(24.8883885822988,6.09833261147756,19.6234229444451));
#1469=CARTESIAN_POINT('',(24.7302258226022,6.0852757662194,19.6130554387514));
#1470=CARTESIAN_POINT('',(24.4144294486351,6.04973049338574,19.5917794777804));
#1471=CARTESIAN_POINT('',(24.2567997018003,6.02720877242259,19.5808692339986));
#1472=CARTESIAN_POINT('',(24.1,6.,19.5697166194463));
#1473=B_SPLINE_CURVE_WITH_KNOTS('',3,(#1463,#1464,#1465,#1466,#1467,#1468,#1469,#1470,#1471,
#1472),.UNSPECIFIED.,.F.,.F.,(4,2,2,2,4),(0.,0.478528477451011,0.95536541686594,
1.43220190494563,1.91072992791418),.UNSPECIFIED.);
#1474=CARTESIAN_POINT('',(26.,6.1,19.691054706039));
#1475=VERTEX_POINT('',#1474);
#1476=EDGE_CURVE('E565',#1475,#1460,#1473,.T.);
#1477=ORIENTED_EDGE('',*,*,#1476,.F.);
#1478=CARTESIAN_POINT('',(26.,6.1,19.691054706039));
#1479=CARTESIAN_POINT('',(26.9072910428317,6.07356941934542,19.743269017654));
#1480=CARTESIAN_POINT('',(27.814956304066,6.04712793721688,19.789018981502));
#1481=CARTESIAN_POINT('',(29.6308607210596,5.99422825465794,19.8673437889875));
#1482=CARTESIAN_POINT('',(30.5390998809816,5.96777005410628,19.8999185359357));
#1483=CARTESIAN_POINT('',(32.3551451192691,5.91486626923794,19.9516223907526));
#1484=CARTESIAN_POINT('',(33.2629508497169,5.88842069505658,19.9707635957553));
#1485=CARTESIAN_POINT('',(35.0787341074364,5.83552454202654,19.9954926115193));
#1486=CARTESIAN_POINT('',(35.9867116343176,5.80907396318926,20.0010804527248));
#1487=CARTESIAN_POINT('',(38.7106799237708,5.72972118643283,19.997324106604));
#1488=CARTESIAN_POINT('',(40.5267058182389,5.67681796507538,19.9674600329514));
#1489=CARTESIAN_POINT('',(43.2501649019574,5.59748002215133,19.8811528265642));
#1490=CARTESIAN_POINT('',(44.1583124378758,5.57102449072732,19.8454388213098));
#1491=CARTESIAN_POINT('',(45.9739447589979,5.51813273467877,19.7601192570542));
#1492=CARTESIAN_POINT('',(46.8814295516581,5.49169650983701,19.7105138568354));
#1493=CARTESIAN_POINT('',(47.7885006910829,5.46527233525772,19.6539435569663));
#1494=B_SPLINE_CURVE_WITH_KNOTS('',3,(#1478,#1479,#1480,#1481,#1482,#1483,#1484,#1485,#1486,
#1487,#1488,#1489,#1490,#1491,#1492,#1493),.UNSPECIFIED.,.F.,.F.,(4,2,2,2,2,2,2,4),(0.,
2.72750953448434,5.45503908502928,8.18010928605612,10.9051733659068,16.3553032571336,
19.0829199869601,21.8105055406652),.UNSPECIFIED.);
#1495=EDGE_CURVE('E600',#1475,#1392,#1494,.T.);
#1496=ORIENTED_EDGE('',*,*,#1495,.T.);
#1497=ORIENTED_EDGE('',*,*,#1393,.F.);
#1498=CARTESIAN_POINT('',(47.7885006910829,-5.46527233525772,19.6539435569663));
#1499=CARTESIAN_POINT('',(46.8814295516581,-5.49169650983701,19.7105138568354));
#1500=CARTESIAN_POINT('',(45.9739447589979,-5.51813273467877,19.7601192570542));
#1501=CARTESIAN_POINT('',(44.1583124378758,-5.57102449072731,19.8454388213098));
#1502=CARTESIAN_POINT('',(43.2501649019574,-5.59748002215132,19.8811528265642));
#1503=CARTESIAN_POINT('',(40.5267058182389,-5.67681796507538,19.9674600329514));
#1504=CARTESIAN_POINT('',(38.7106799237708,-5.72972118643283,19.997324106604));
#1505=CARTESIAN_POINT('',(35.9867116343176,-5.80907396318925,20.0010804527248));
#1506=CARTESIAN_POINT('',(35.0787341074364,-5.83552454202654,19.9954926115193));
#1507=CARTESIAN_POINT('',(33.2629508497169,-5.88842069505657,19.9707635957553));
#1508=CARTESIAN_POINT('',(32.3551451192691,-5.91486626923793,19.9516223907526));
#1509=CARTESIAN_POINT('',(30.5390998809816,-5.96777005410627,19.8999185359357));
#1510=CARTESIAN_POINT('',(29.6308607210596,-5.99422825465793,19.8673437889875));
#1511=CARTESIAN_POINT('',(27.814956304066,-6.04712793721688,19.789018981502));
#1512=CARTESIAN_POINT('',(26.9072910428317,-6.07356941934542,19.743269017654));
#1513=CARTESIAN_POINT('',(26.,-6.1,19.691054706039));
#1514=B_SPLINE_CURVE_WITH_KNOTS('',3,(#1498,#1499,#1500,#1501,#1502,#1503,#1504,#1505,#1506,
#1507,#1508,#1509,#1510,#1511,#1512,#1513),.UNSPECIFIED.,.F.,.F.,(4,2,2,2,2,2,2,4),(0.,
2.72758555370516,5.45520228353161,10.9053321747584,13.6303962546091,16.3554664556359,
19.0829960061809,21.8105055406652),.UNSPECIFIED.);
#1515=CARTESIAN_POINT('',(26.,-6.1,19.691054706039));
#1516=VERTEX_POINT('',#1515);
#1517=EDGE_CURVE('E528',#1383,#1516,#1514,.T.);
#1518=ORIENTED_EDGE('',*,*,#1517,.T.);
#1519=CARTESIAN_POINT('',(24.1000000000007,-6.00000000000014,19.5697166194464));
#1520=CARTESIAN_POINT('',(24.2567997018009,-6.02720877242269,19.5808692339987));
#1521=CARTESIAN_POINT('',(24.4144294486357,-6.04973049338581,19.5917794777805));
#1522=CARTESIAN_POINT('',(24.7302258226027,-6.08527576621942,19.6130554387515));
#1523=CARTESIAN_POINT('',(24.8883885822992,-6.09833261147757,19.6234229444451));
#1524=CARTESIAN_POINT('',(25.2052444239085,-6.11501717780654,19.6436328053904));
#1525=CARTESIAN_POINT('',(25.363937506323,-6.1186448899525,19.653475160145));
#1526=CARTESIAN_POINT('',(25.6818540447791,-6.11645694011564,19.6726566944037));
#1527=CARTESIAN_POINT('',(25.8410773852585,-6.11060773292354,19.6819939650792));
#1528=CARTESIAN_POINT('',(26.,-6.1,19.691054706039));
#1529=B_SPLINE_CURVE_WITH_KNOTS('',3,(#1519,#1520,#1521,#1522,#1523,#1524,#1525,#1526,#1527,
#1528),.UNSPECIFIED.,.F.,.F.,(4,2,2,2,4),(0.,0.47852802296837,0.955364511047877,
1.43220145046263,1.91072992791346),.UNSPECIFIED.);
#1530=CARTESIAN_POINT('',(24.1000000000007,-6.00000000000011,19.5697166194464));
#1531=VERTEX_POINT('',#1530);
#1532=EDGE_CURVE('E538',#1531,#1516,#1529,.T.);
#1533=ORIENTED_EDGE('',*,*,#1532,.F.);
#1534=CARTESIAN_POINT('',(24.1000000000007,-6.00000000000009,19.5697166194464));
#1535=CARTESIAN_POINT('',(23.6700491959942,-5.91247637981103,19.5389283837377));
#1536=CARTESIAN_POINT('',(23.238352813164,-5.83411655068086,19.5065023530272));
#1537=CARTESIAN_POINT('',(22.3722698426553,-5.6958106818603,19.4385173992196));
#1538=CARTESIAN_POINT('',(21.9378832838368,-5.63586444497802,19.4029585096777));
#1539=CARTESIAN_POINT('',(21.0673528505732,-5.53448653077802,19.3288618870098));
#1540=CARTESIAN_POINT('',(20.6312095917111,-5.49304885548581,19.2903251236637));
#1541=CARTESIAN_POINT('',(19.7578136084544,-5.42869998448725,19.2104767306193));
#1542=CARTESIAN_POINT('',(19.3205608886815,-5.40578871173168,19.1691651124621));
#1543=CARTESIAN_POINT('',(18.4573972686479,-5.37886583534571,19.085189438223));
#1544=CARTESIAN_POINT('',(18.0314951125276,-5.37436615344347,19.0425909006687));
#1545=CARTESIAN_POINT('',(17.1800698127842,-5.38290602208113,18.9553893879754));
#1546=CARTESIAN_POINT('',(16.7545466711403,-5.39594566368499,18.9107864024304));
#1547=CARTESIAN_POINT('',(15.9045189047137,-5.43952264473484,18.820037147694));
#1548=CARTESIAN_POINT('',(15.4800143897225,-5.47006179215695,18.7738907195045));
#1549=CARTESIAN_POINT('',(14.6327236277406,-5.54857515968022,18.6806705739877));
#1550=CARTESIAN_POINT('',(14.2099373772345,-5.5965493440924,18.6335968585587));
#1551=CARTESIAN_POINT('',(13.379203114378,-5.70817516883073,18.5407202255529));
#1552=CARTESIAN_POINT('',(12.9711865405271,-5.77132032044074,18.4949209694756));
#1553=CARTESIAN_POINT('',(12.1579139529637,-5.91387254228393,18.4041526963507));
#1554=CARTESIAN_POINT('',(11.752657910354,-5.99327944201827,18.3591836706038));
#1555=CARTESIAN_POINT('',(10.9455521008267,-6.16824441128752,18.2712960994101));
#1556=CARTESIAN_POINT('',(10.5437013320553,-6.26379754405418,18.228376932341));
#1557=CARTESIAN_POINT('',(9.74378447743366,-6.47098793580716,18.1460754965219));
#1558=CARTESIAN_POINT('',(9.3457184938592,-6.58262562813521,18.1066933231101));
#1559=CARTESIAN_POINT('',(8.54324201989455,-6.82511092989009,18.0322671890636));
#1560=CARTESIAN_POINT('',(8.13894980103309,-6.95639528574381,17.9973688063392));
#1561=CARTESIAN_POINT('',(7.33557761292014,-7.23568604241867,17.9353504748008));
#1562=CARTESIAN_POINT('',(6.93649725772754,-7.3836911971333,17.9082299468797));
#1563=CARTESIAN_POINT('',(6.34213257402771,-7.61816786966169,17.8749195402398));
#1564=CARTESIAN_POINT('',(6.14459468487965,-7.69846056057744,17.8650404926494));
#1565=CARTESIAN_POINT('',(5.75111636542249,-7.86314935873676,17.8479604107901));
#1566=CARTESIAN_POINT('',(5.55517592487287,-7.94754543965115,17.8407593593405));
#1567=CARTESIAN_POINT('',(5.16495245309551,-8.12042294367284,17.8292080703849));
#1568=CARTESIAN_POINT('',(4.97066992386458,-8.2089055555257,17.8248586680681));
#1569=CARTESIAN_POINT('',(4.58393292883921,-8.38988474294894,17.8191052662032));
#1570=CARTESIAN_POINT('',(4.39147851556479,-8.48238143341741,17.817701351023));
#1571=CARTESIAN_POINT('',(4.20000000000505,-8.57685839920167,17.8178159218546));
#1572=B_SPLINE_CURVE_WITH_KNOTS('',3,(#1534,#1535,#1536,#1537,#1538,#1539,#1540,#1541,#1542,
#1543,#1544,#1545,#1546,#1547,#1548,#1549,#1550,#1551,#1552,#1553,#1554,#1555,#1556,#1557,#1558,
#1559,#1560,#1561,#1562,#1563,#1564,#1565,#1566,#1567,#1568,#1569,#1570,#1571),.UNSPECIFIED.,
.F.,.F.,(4,2,2,2,2,2,2,2,2,2,2,2,2,2,2,2,2,2,4),(0.,1.31943784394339,2.63886155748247,
3.95785738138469,5.27684771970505,6.56063666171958,7.84443226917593,9.12836053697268,
10.4122861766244,11.6581796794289,12.9040601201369,14.1495603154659,15.3950940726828,
16.6742064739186,17.9532236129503,18.5935561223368,19.2338845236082,19.8744003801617,
20.5149345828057),.UNSPECIFIED.);
#1573=EDGE_CURVE('E548',#1531,#1082,#1572,.T.);
#1574=ORIENTED_EDGE('',*,*,#1573,.T.);
#1575=ORIENTED_EDGE('',*,*,#1083,.F.);
#1576=ORIENTED_EDGE('',*,*,#308,.F.);
#1577=EDGE_LOOP('',(#1421,#1422,#1423,#1462,#1477,#1496,#1497,#1518,#1533,#1574,#1575,#1576));
#1578=FACE_BOUND('',#1577,.T.);
#1579=ADVANCED_FACE('F236',(#1578),#1420,.F.);
#1580=CARTESIAN_POINT('',(0.,0.,25.5534224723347));
#1581=DIRECTION('',(0.,0.,-1.));
#1582=DIRECTION('',(0.,1.,0.));
#1583=AXIS2_PLACEMENT_3D('',#1580,#1581,#1582);
#1584=TOROIDAL_SURFACE('',#1583,62.6,2.39999999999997);
#1585=ORIENTED_EDGE('',*,*,#926,.T.);
#1586=CARTESIAN_POINT('',(0.,0.,27.9474100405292));
#1587=DIRECTION('',(0.,0.,1.));
#1588=DIRECTION('',(0.,-1.,0.));
#1589=AXIS2_PLACEMENT_3D('',#1586,#1587,#1588);
#1590=CIRCLE('',#1589,62.7697749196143);
#1591=EDGE_CURVE('E523',#1156,#870,#1590,.T.);
#1592=ORIENTED_EDGE('',*,*,#1591,.F.);
#1593=ORIENTED_EDGE('',*,*,#1157,.T.);
#1594=ORIENTED_EDGE('',*,*,#815,.T.);
#1595=EDGE_LOOP('',(#1585,#1592,#1593,#1594));
#1596=FACE_BOUND('',#1595,.T.);
#1597=ADVANCED_FACE('F580',(#1596),#1584,.T.);
#1598=CARTESIAN_POINT('',(62.0873568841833,5.04872785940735,65.));
#1599=DIRECTION('',(-0.0291189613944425,-0.999575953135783,0.));
#1600=DIRECTION('',(0.999575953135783,-0.0291189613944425,0.));
#1601=AXIS2_PLACEMENT_3D('',#1598,#1599,#1600);
#1602=PLANE('',#1601);
#1603=ORIENTED_EDGE('',*,*,#860,.F.);
#1604=ORIENTED_EDGE('',*,*,#1271,.F.);
#1605=ORIENTED_EDGE('',*,*,#1302,.F.);
#1606=ORIENTED_EDGE('',*,*,#1330,.F.);
#1607=ORIENTED_EDGE('',*,*,#1410,.F.);
#1608=ORIENTED_EDGE('',*,*,#1495,.F.);
#1609=DIRECTION('',(0.,0.,1.));
#1610=VECTOR('',#1609,1.);
#1611=CARTESIAN_POINT('',(26.,6.1,65.));
#1612=LINE('',#1611,#1610);
#1613=CARTESIAN_POINT('',(26.,6.1,29.1995183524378));
#1614=VERTEX_POINT('',#1613);
#1615=EDGE_CURVE('E562',#1614,#1475,#1612,.F.);
#1616=ORIENTED_EDGE('',*,*,#1615,.F.);
#1617=CARTESIAN_POINT('',(62.0873568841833,5.04872785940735,27.9810421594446));
#1618=CARTESIAN_POINT('',(59.0845187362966,5.1362044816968,28.1899530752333));
#1619=CARTESIAN_POINT('',(56.0797745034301,5.22373663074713,28.3718069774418));
#1620=CARTESIAN_POINT('',(50.0684583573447,5.39885417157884,28.6816007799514));
#1621=CARTESIAN_POINT('',(47.0618873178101,5.48643953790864,28.8095576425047));
#1622=CARTESIAN_POINT('',(42.5507239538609,5.61785565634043,28.9613060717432));
#1623=CARTESIAN_POINT('',(41.04678262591,5.66166744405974,29.0051911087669));
#1624=CARTESIAN_POINT('',(38.0385656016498,5.74930076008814,29.0796454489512));
#1625=CARTESIAN_POINT('',(36.5342899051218,5.7931222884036,29.1102147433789));
#1626=CARTESIAN_POINT('',(33.5250556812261,5.88078523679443,29.1581465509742));
#1627=CARTESIAN_POINT('',(32.0200970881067,5.92462665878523,29.1755048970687));
#1628=CARTESIAN_POINT('',(29.0100889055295,6.01231215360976,29.1972137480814));
#1629=CARTESIAN_POINT('',(27.5050393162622,6.05615622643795,29.2015642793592));
#1630=CARTESIAN_POINT('',(26.,6.1,29.1995183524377));
#1631=B_SPLINE_CURVE_WITH_KNOTS('',3,(#1617,#1618,#1619,#1620,#1621,#1622,#1623,#1624,#1625,
#1626,#1627,#1628,#1629,#1630),.UNSPECIFIED.,.F.,.F.,(4,2,2,2,2,2,4),(0.,9.0340334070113,
18.0652215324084,22.580830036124,27.0964415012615,31.6134767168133,36.1305027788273),.UNSPECIFIED.);
#1632=EDGE_CURVE('E286',#859,#1614,#1631,.T.);
#1633=ORIENTED_EDGE('',*,*,#1632,.F.);
#1634=EDGE_LOOP('',(#1603,#1604,#1605,#1606,#1607,#1608,#1616,#1633));
#1635=FACE_BOUND('',#1634,.T.);
#1636=ADVANCED_FACE('F584',(#1635),#1602,.F.);
#1637=CARTESIAN_POINT('',(25.4674872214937,-1.88225720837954,65.));
#1638=DIRECTION('',(0.,0.,1.));
#1639=DIRECTION('',(0.,-1.,0.));
#1640=AXIS2_PLACEMENT_3D('',#1637,#1638,#1639);
#1641=CYLINDRICAL_SURFACE('',#1640,8.);
#1642=ORIENTED_EDGE('',*,*,#1476,.T.);
#1643=DIRECTION('',(0.,0.,1.));
#1644=VECTOR('',#1643,1.);
#1645=CARTESIAN_POINT('',(24.1,6.,65.));
#1646=LINE('',#1645,#1644);
#1647=CARTESIAN_POINT('',(24.1,6.,29.1934241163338));
#1648=VERTEX_POINT('',#1647);
#1649=EDGE_CURVE('E558',#1460,#1648,#1646,.T.);
#1650=ORIENTED_EDGE('',*,*,#1649,.T.);
#1651=CARTESIAN_POINT('',(26.,6.1,29.1995183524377));
#1652=CARTESIAN_POINT('',(25.8411419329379,6.11060338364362,29.199307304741));
#1653=CARTESIAN_POINT('',(25.6819675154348,6.11645323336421,29.1990244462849));
#1654=CARTESIAN_POINT('',(25.3641169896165,6.11864656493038,29.1983119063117));
#1655=CARTESIAN_POINT('',(25.2054411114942,6.11502361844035,29.1978827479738));
#1656=CARTESIAN_POINT('',(24.8885861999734,6.09834692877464,29.1968729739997));
#1657=CARTESIAN_POINT('',(24.7304071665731,6.08529318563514,29.1962923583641));
#1658=CARTESIAN_POINT('',(24.4145448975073,6.04974649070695,29.194975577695));
#1659=CARTESIAN_POINT('',(24.2568654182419,6.02722017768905,29.1942388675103));
#1660=CARTESIAN_POINT('',(24.1,6.,29.1934241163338));
#1661=B_SPLINE_CURVE_WITH_KNOTS('',3,(#1651,#1652,#1653,#1654,#1655,#1656,#1657,#1658,#1659,
#1660),.UNSPECIFIED.,.F.,.F.,(4,2,2,2,4),(0.,0.477562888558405,0.953435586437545,
1.42930828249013,1.90687116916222),.UNSPECIFIED.);
#1662=EDGE_CURVE('E279',#1614,#1648,#1661,.T.);
#1663=ORIENTED_EDGE('',*,*,#1662,.F.);
#1664=ORIENTED_EDGE('',*,*,#1615,.T.);
#1665=EDGE_LOOP('',(#1642,#1650,#1663,#1664));
#1666=FACE_BOUND('',#1665,.T.);
#1667=ADVANCED_FACE('F979',(#1666),#1641,.T.);
#1668=CARTESIAN_POINT('',(17.9166998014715,36.3770768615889,65.));
#1669=DIRECTION('',(0.,0.,1.));
#1670=DIRECTION('',(0.,-1.,0.));
#1671=AXIS2_PLACEMENT_3D('',#1668,#1669,#1670);
#1672=CYLINDRICAL_SURFACE('',#1671,31.);
#1673=ORIENTED_EDGE('',*,*,#1013,.F.);
#1674=DIRECTION('',(0.,0.,-1.));
#1675=VECTOR('',#1674,1.);
#1676=CARTESIAN_POINT('',(4.37639516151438,8.49051826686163,28.6696323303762));
#1677=LINE('',#1676,#1675);
#1678=CARTESIAN_POINT('',(4.37639516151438,8.49051826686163,28.8813492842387));
#1679=VERTEX_POINT('',#1678);
#1680=EDGE_CURVE('E549',#1679,#1003,#1677,.T.);
#1681=ORIENTED_EDGE('',*,*,#1680,.F.);
#1682=CARTESIAN_POINT('',(24.1,6.,29.1934241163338));
#1683=CARTESIAN_POINT('',(23.667816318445,5.91202887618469,29.1911653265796));
#1684=CARTESIAN_POINT('',(23.2338129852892,5.83329325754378,29.1883239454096));
#1685=CARTESIAN_POINT('',(22.3628503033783,5.69440636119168,29.1814992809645));
#1686=CARTESIAN_POINT('',(21.9258909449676,5.63425514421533,29.1775159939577));
#1687=CARTESIAN_POINT('',(20.6118533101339,5.48187730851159,29.1638907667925));
#1688=CARTESIAN_POINT('',(19.7313727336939,5.41767712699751,29.1525721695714));
#1689=CARTESIAN_POINT('',(17.9918590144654,5.36528109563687,29.1262720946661));
#1690=CARTESIAN_POINT('',(17.1328802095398,5.37510369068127,29.11139636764));
#1691=CARTESIAN_POINT('',(15.4188012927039,5.46596315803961,29.0786509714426));
#1692=CARTESIAN_POINT('',(14.5637008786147,5.54699438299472,29.0607815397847));
#1693=CARTESIAN_POINT('',(12.9149329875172,5.77263622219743,29.0246375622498));
#1694=CARTESIAN_POINT('',(12.1206949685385,5.91307549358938,29.0064539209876));
#1695=CARTESIAN_POINT('',(10.939519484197,6.16976894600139,28.9797249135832));
#1696=CARTESIAN_POINT('',(10.5474604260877,6.26301511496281,28.9709056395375));
#1697=CARTESIAN_POINT('',(9.76723973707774,6.46472802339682,28.9538151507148));
#1698=CARTESIAN_POINT('',(9.37907813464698,6.57319487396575,28.9455439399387));
#1699=CARTESIAN_POINT('',(8.59732300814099,6.80817287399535,28.9297651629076));
#1700=CARTESIAN_POINT('',(8.20384714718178,6.93507688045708,28.9222827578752));
#1701=CARTESIAN_POINT('',(7.42226022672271,7.20452795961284,28.908826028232));
#1702=CARTESIAN_POINT('',(7.03414917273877,7.3470750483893,28.9028517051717));
#1703=CARTESIAN_POINT('',(6.26385850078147,7.64761096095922,28.8929028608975));
#1704=CARTESIAN_POINT('',(5.88167978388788,7.80560210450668,28.8889286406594));
#1705=CARTESIAN_POINT('',(5.12392751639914,8.13675064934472,28.8833096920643));
#1706=CARTESIAN_POINT('',(4.74835405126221,8.30990824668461,28.8816649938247));
#1707=CARTESIAN_POINT('',(4.37639516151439,8.49051826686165,28.8813492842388));
#1708=B_SPLINE_CURVE_WITH_KNOTS('',3,(#1682,#1683,#1684,#1685,#1686,#1687,#1688,#1689,#1690,
#1691,#1692,#1693,#1694,#1695,#1696,#1697,#1698,#1699,#1700,#1701,#1702,#1703,#1704,#1705,#1706,
#1707),.UNSPECIFIED.,.F.,.F.,(4,2,2,2,2,2,2,2,2,2,2,2,4),(0.,1.32294292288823,2.64589016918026,
5.29104396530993,7.86564478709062,10.4400414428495,12.8576983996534,14.0667194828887,
15.2757493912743,16.5159250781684,17.756102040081,18.9964655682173,20.2368451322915),.UNSPECIFIED.);
#1709=EDGE_CURVE('E271',#1648,#1679,#1708,.T.);
#1710=ORIENTED_EDGE('',*,*,#1709,.F.);
#1711=ORIENTED_EDGE('',*,*,#1649,.F.);
#1712=ORIENTED_EDGE('',*,*,#1461,.F.);
#1713=ORIENTED_EDGE('',*,*,#947,.F.);
#1714=EDGE_LOOP('',(#1673,#1681,#1710,#1711,#1712,#1713));
#1715=FACE_BOUND('',#1714,.T.);
#1716=ADVANCED_FACE('F971',(#1715),#1672,.F.);
#1717=CARTESIAN_POINT('',(4.37639516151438,-19.1,28.6696323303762));
#1718=DIRECTION('',(-1.,0.,0.));
#1719=DIRECTION('',(0.,0.,-1.));
#1720=AXIS2_PLACEMENT_3D('',#1717,#1718,#1719);
#1721=PLANE('',#1720);
#1722=CARTESIAN_POINT('',(4.37639516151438,8.49051826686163,28.8813492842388));
#1723=CARTESIAN_POINT('',(4.37639516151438,8.1499163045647,28.8705468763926));
#1724=CARTESIAN_POINT('',(4.37639516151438,7.80931953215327,28.8595840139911));
#1725=CARTESIAN_POINT('',(4.37639516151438,7.12813159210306,28.8375300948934));
#1726=CARTESIAN_POINT('',(4.37639516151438,6.78754042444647,28.8264390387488));
#1727=CARTESIAN_POINT('',(4.37639516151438,6.10636977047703,28.804321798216));
#1728=CARTESIAN_POINT('',(4.37639516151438,5.76579028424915,28.793295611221));
#1729=CARTESIAN_POINT('',(4.37639516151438,5.0846177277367,28.7716138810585));
#1730=CARTESIAN_POINT('',(4.37639516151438,4.74402465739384,28.7609583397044));
#1731=CARTESIAN_POINT('',(4.37639516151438,4.06278775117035,28.7404604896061));
#1732=CARTESIAN_POINT('',(4.37639516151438,3.7221439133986,28.7306182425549));
#1733=CARTESIAN_POINT('',(4.37639516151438,3.0408207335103,28.7123803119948));
#1734=CARTESIAN_POINT('',(4.37639516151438,2.70014139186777,28.7039846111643));
#1735=CARTESIAN_POINT('',(4.37639516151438,2.01871728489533,28.6894690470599));
#1736=CARTESIAN_POINT('',(4.37639516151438,1.67797251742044,28.6833492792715));
#1737=CARTESIAN_POINT('',(4.37639516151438,1.166816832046,28.6765241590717));
#1738=CARTESIAN_POINT('',(4.37639516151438,0.996421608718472,28.6746415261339));
#1739=CARTESIAN_POINT('',(4.37639516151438,0.655622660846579,28.6717349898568));
#1740=CARTESIAN_POINT('',(4.37639516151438,0.485218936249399,28.6707110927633));
#1741=CARTESIAN_POINT('',(4.37639516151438,0.3148131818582,28.6701534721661));
#1742=B_SPLINE_CURVE_WITH_KNOTS('',3,(#1722,#1723,#1724,#1725,#1726,#1727,#1728,#1729,#1730,
#1731,#1732,#1733,#1734,#1735,#1736,#1737,#1738,#1739,#1740,#1741),.UNSPECIFIED.,.F.,.F.,(4,2,2,
2,2,2,2,2,2,4),(0.,1.02231950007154,2.04463460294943,3.06690833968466,4.08918707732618,
5.11154328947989,6.13388725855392,7.15627411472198,7.6674889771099,8.17870755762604),.UNSPECIFIED.);
#1743=EDGE_CURVE('E1371',#1679,#30,#1742,.T.);
#1744=ORIENTED_EDGE('',*,*,#1743,.F.);
#1745=ORIENTED_EDGE('',*,*,#1680,.T.);
#1746=ORIENTED_EDGE('',*,*,#1004,.T.);
#1747=EDGE_LOOP('',(#1744,#1745,#1746));
#1748=FACE_BOUND('',#1747,.T.);
#1749=ADVANCED_FACE('F962',(#1748),#1721,.T.);
#1750=CARTESIAN_POINT('',(4.37639516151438,-19.1,28.6696323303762));
#1751=DIRECTION('',(-1.,0.,0.));
#1752=DIRECTION('',(0.,0.,-1.));
#1753=AXIS2_PLACEMENT_3D('',#1750,#1751,#1752);
#1754=PLANE('',#1753);
#1755=ORIENTED_EDGE('',*,*,#1063,.T.);
#1756=DIRECTION('',(0.,0.,1.));
#1757=VECTOR('',#1756,1.);
#1758=CARTESIAN_POINT('',(4.37639516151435,-8.49051826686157,65.));
#1759=LINE('',#1758,#1757);
#1760=CARTESIAN_POINT('',(4.37639516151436,-8.49051826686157,28.8813492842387));
#1761=VERTEX_POINT('',#1760);
#1762=EDGE_CURVE('E542',#1056,#1761,#1759,.T.);
#1763=ORIENTED_EDGE('',*,*,#1762,.T.);
#1764=CARTESIAN_POINT('',(4.37639516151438,-0.314813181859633,28.670153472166));
#1765=CARTESIAN_POINT('',(4.37639516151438,-0.497774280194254,28.6707507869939));
#1766=CARTESIAN_POINT('',(4.37639516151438,-0.680732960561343,28.6718875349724));
#1767=CARTESIAN_POINT('',(4.37639516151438,-1.04663999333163,28.6751448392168));
#1768=CARTESIAN_POINT('',(4.37639516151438,-1.22958834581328,28.6772653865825));
#1769=CARTESIAN_POINT('',(4.37639516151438,-1.77839772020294,28.6849599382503));
#1770=CARTESIAN_POINT('',(4.37639516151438,-2.14423998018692,28.6918669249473));
#1771=CARTESIAN_POINT('',(4.37639516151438,-2.87585084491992,28.708151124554));
#1772=CARTESIAN_POINT('',(4.37639516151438,-3.24161945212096,28.717528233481));
#1773=CARTESIAN_POINT('',(4.37639516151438,-3.97311930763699,28.7377703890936));
#1774=CARTESIAN_POINT('',(4.37639516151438,-4.3388505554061,28.7486354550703));
#1775=CARTESIAN_POINT('',(4.37639516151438,-5.33557803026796,28.7792610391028));
#1776=CARTESIAN_POINT('',(4.37639516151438,-5.96655115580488,28.7997571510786));
#1777=CARTESIAN_POINT('',(4.37639516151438,-6.91301927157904,28.8305291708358));
#1778=CARTESIAN_POINT('',(4.37639516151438,-7.22851492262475,28.840791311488));
#1779=CARTESIAN_POINT('',(4.37639516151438,-7.85951175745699,28.861194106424));
#1780=CARTESIAN_POINT('',(4.37639516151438,-8.17501294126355,28.8713347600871));
#1781=CARTESIAN_POINT('',(4.37639516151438,-8.49051826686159,28.8813492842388));
#1782=B_SPLINE_CURVE_WITH_KNOTS('',3,(#1764,#1765,#1766,#1767,#1768,#1769,#1770,#1771,#1772,
#1773,#1774,#1775,#1776,#1777,#1778,#1779,#1780,#1781),.UNSPECIFIED.,.F.,.F.,(4,2,2,2,2,2,2,2,
4),(0.,0.548884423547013,1.09776388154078,2.19547203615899,3.29313398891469,4.3908101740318,
6.28472679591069,7.23171436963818,8.17870677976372),.UNSPECIFIED.);
#1783=EDGE_CURVE('E1376',#32,#1761,#1782,.T.);
#1784=ORIENTED_EDGE('',*,*,#1783,.F.);
#1785=EDGE_LOOP('',(#1755,#1763,#1784));
#1786=FACE_BOUND('',#1785,.T.);
#1787=ADVANCED_FACE('F952',(#1786),#1754,.T.);
#1788=CARTESIAN_POINT('',(17.9166998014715,-36.3770768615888,65.));
#1789=DIRECTION('',(0.,0.,1.));
#1790=DIRECTION('',(0.,-1.,0.));
#1791=AXIS2_PLACEMENT_3D('',#1788,#1789,#1790);
#1792=CYLINDRICAL_SURFACE('',#1791,31.);
#1793=ORIENTED_EDGE('',*,*,#1057,.T.);
#1794=ORIENTED_EDGE('',*,*,#1089,.F.);
#1795=ORIENTED_EDGE('',*,*,#1573,.F.);
#1796=DIRECTION('',(0.,0.,1.));
#1797=VECTOR('',#1796,1.);
#1798=CARTESIAN_POINT('',(24.1000000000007,-6.00000000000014,65.));
#1799=LINE('',#1798,#1797);
#1800=CARTESIAN_POINT('',(24.1000000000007,-6.00000000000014,29.1934241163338));
#1801=VERTEX_POINT('',#1800);
#1802=EDGE_CURVE('E539',#1801,#1531,#1799,.F.);
#1803=ORIENTED_EDGE('',*,*,#1802,.F.);
#1804=CARTESIAN_POINT('',(4.37639516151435,-8.49051826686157,28.8813492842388));
#1805=CARTESIAN_POINT('',(4.74515498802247,-8.3114617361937,28.8816631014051));
#1806=CARTESIAN_POINT('',(5.11746746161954,-8.13972981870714,28.8832820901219));
#1807=CARTESIAN_POINT('',(5.86858983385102,-7.81117065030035,28.8888122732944));
#1808=CARTESIAN_POINT('',(6.24739964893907,-7.65434320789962,28.8927234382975));
#1809=CARTESIAN_POINT('',(7.01085751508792,-7.35586759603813,28.9025190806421));
#1810=CARTESIAN_POINT('',(7.39550462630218,-7.21421701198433,28.9084032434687));
#1811=CARTESIAN_POINT('',(8.1700876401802,-6.94628529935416,28.9216665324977));
#1812=CARTESIAN_POINT('',(8.5600235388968,-6.82000415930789,28.9290456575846));
#1813=CARTESIAN_POINT('',(9.33480918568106,-6.58595731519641,28.944621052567));
#1814=CARTESIAN_POINT('',(9.7195437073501,-6.47780878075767,28.9527923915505));
#1815=CARTESIAN_POINT('',(10.4928704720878,-6.27647148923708,28.9696907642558));
#1816=CARTESIAN_POINT('',(10.8814626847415,-6.18328261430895,28.9784177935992));
#1817=CARTESIAN_POINT('',(12.0522080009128,-5.92636325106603,29.0048909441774));
#1818=CARTESIAN_POINT('',(12.8394398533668,-5.78524678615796,29.0229315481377));
#1819=CARTESIAN_POINT('',(14.4875786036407,-5.55518035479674,29.0591633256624));
#1820=CARTESIAN_POINT('',(15.3492185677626,-5.47147713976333,29.077244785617));
#1821=CARTESIAN_POINT('',(17.0765916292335,-5.37638987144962,29.1103928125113));
#1822=CARTESIAN_POINT('',(17.9423251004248,-5.36501255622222,29.1254590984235));
#1823=CARTESIAN_POINT('',(19.6957923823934,-5.41540844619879,29.1520969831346));
#1824=CARTESIAN_POINT('',(20.5834734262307,-5.4792106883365,29.1635605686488));
#1825=CARTESIAN_POINT('',(21.9082360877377,-5.63190649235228,29.1773503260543));
#1826=CARTESIAN_POINT('',(22.3487571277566,-5.69231603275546,29.1813796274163));
#1827=CARTESIAN_POINT('',(23.2268016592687,-5.83202195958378,29.1882780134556));
#1828=CARTESIAN_POINT('',(23.6643251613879,-5.91131827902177,29.1911471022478));
#1829=CARTESIAN_POINT('',(24.1000000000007,-6.00000000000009,29.1934241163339));
#1830=B_SPLINE_CURVE_WITH_KNOTS('',3,(#1804,#1805,#1806,#1807,#1808,#1809,#1810,#1811,#1812,
#1813,#1814,#1815,#1816,#1817,#1818,#1819,#1820,#1821,#1822,#1823,#1824,#1825,#1826,#1827,#1828,
#1829),.UNSPECIFIED.,.F.,.F.,(4,2,2,2,2,2,2,2,2,2,2,2,4),(0.,1.22971296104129,2.45941012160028,
3.68891134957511,4.91841165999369,6.11728820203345,7.31615529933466,9.71354541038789,
12.30816523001,14.9030267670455,17.569556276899,18.9031869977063,20.2368129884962),.UNSPECIFIED.);
#1831=EDGE_CURVE('E245',#1761,#1801,#1830,.T.);
#1832=ORIENTED_EDGE('',*,*,#1831,.F.);
#1833=ORIENTED_EDGE('',*,*,#1762,.F.);
#1834=EDGE_LOOP('',(#1793,#1794,#1795,#1803,#1832,#1833));
#1835=FACE_BOUND('',#1834,.T.);
#1836=ADVANCED_FACE('F942',(#1835),#1792,.F.);
#1837=CARTESIAN_POINT('',(25.4674872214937,1.88225720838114,65.));
#1838=DIRECTION('',(0.,0.,1.));
#1839=DIRECTION('',(0.,-1.,0.));
#1840=AXIS2_PLACEMENT_3D('',#1837,#1838,#1839);
#1841=CYLINDRICAL_SURFACE('',#1840,8.00000000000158);
#1842=ORIENTED_EDGE('',*,*,#1532,.T.);
#1843=DIRECTION('',(0.,0.,1.));
#1844=VECTOR('',#1843,1.);
#1845=CARTESIAN_POINT('',(26.,-6.1,65.));
#1846=LINE('',#1845,#1844);
#1847=CARTESIAN_POINT('',(26.,-6.1,29.1995183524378));
#1848=VERTEX_POINT('',#1847);
#1849=EDGE_CURVE('E526',#1516,#1848,#1846,.T.);
#1850=ORIENTED_EDGE('',*,*,#1849,.T.);
#1851=CARTESIAN_POINT('',(24.1000000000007,-6.00000000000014,29.1934241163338));
#1852=CARTESIAN_POINT('',(24.2568654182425,-6.02722017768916,29.1942388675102));
#1853=CARTESIAN_POINT('',(24.4145448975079,-6.04974649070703,29.194975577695));
#1854=CARTESIAN_POINT('',(24.7304071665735,-6.08529318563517,29.1962923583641));
#1855=CARTESIAN_POINT('',(24.8885861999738,-6.09834692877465,29.1968729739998));
#1856=CARTESIAN_POINT('',(25.2054411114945,-6.11502361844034,29.1978827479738));
#1857=CARTESIAN_POINT('',(25.3641169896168,-6.11864656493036,29.1983119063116));
#1858=CARTESIAN_POINT('',(25.6819675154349,-6.11645323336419,29.1990244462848));
#1859=CARTESIAN_POINT('',(25.8411419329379,-6.11060338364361,29.1993073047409));
#1860=CARTESIAN_POINT('',(26.,-6.1,29.1995183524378));
#1861=B_SPLINE_CURVE_WITH_KNOTS('',3,(#1851,#1852,#1853,#1854,#1855,#1856,#1857,#1858,#1859,
#1860),.UNSPECIFIED.,.F.,.F.,(4,2,2,2,4),(0.,0.477562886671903,0.953435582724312,
1.42930828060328,1.9068711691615),.UNSPECIFIED.);
#1862=EDGE_CURVE('E220',#1801,#1848,#1861,.T.);
#1863=ORIENTED_EDGE('',*,*,#1862,.F.);
#1864=ORIENTED_EDGE('',*,*,#1802,.T.);
#1865=EDGE_LOOP('',(#1842,#1850,#1863,#1864));
#1866=FACE_BOUND('',#1865,.T.);
#1867=ADVANCED_FACE('F933',(#1866),#1841,.T.);
#1868=CARTESIAN_POINT('',(26.,-6.1,65.));
#1869=DIRECTION('',(-0.0291189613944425,0.999575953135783,0.));
#1870=DIRECTION('',(-0.999575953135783,-0.0291189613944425,0.));
#1871=AXIS2_PLACEMENT_3D('',#1868,#1869,#1870);
#1872=PLANE('',#1871);
#1873=ORIENTED_EDGE('',*,*,#1849,.F.);
#1874=ORIENTED_EDGE('',*,*,#1517,.F.);
#1875=ORIENTED_EDGE('',*,*,#1384,.F.);
#1876=ORIENTED_EDGE('',*,*,#1350,.F.);
#1877=ORIENTED_EDGE('',*,*,#1287,.F.);
#1878=ORIENTED_EDGE('',*,*,#1237,.F.);
#1879=ORIENTED_EDGE('',*,*,#1176,.F.);
#1880=CARTESIAN_POINT('',(26.,-6.1,29.1995183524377));
#1881=CARTESIAN_POINT('',(27.113024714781,-6.06757612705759,29.2010204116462));
#1882=CARTESIAN_POINT('',(28.226051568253,-6.03515219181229,29.1990365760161));
#1883=CARTESIAN_POINT('',(30.4520714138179,-5.97030530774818,29.1879905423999));
#1884=CARTESIAN_POINT('',(31.5650644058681,-5.93788235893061,29.1789283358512));
#1885=CARTESIAN_POINT('',(34.9039592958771,-5.84061596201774,29.1409639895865));
#1886=CARTESIAN_POINT('',(37.1297491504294,-5.77577577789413,29.1012840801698));
#1887=CARTESIAN_POINT('',(41.5795686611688,-5.64614668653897,28.9927899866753));
#1888=CARTESIAN_POINT('',(43.8035986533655,-5.58135776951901,28.9239894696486));
#1889=CARTESIAN_POINT('',(48.2505308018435,-5.45181279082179,28.7570556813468));
#1890=CARTESIAN_POINT('',(50.4734329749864,-5.38705672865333,28.658922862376));
#1891=CARTESIAN_POINT('',(54.2615838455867,-5.27670291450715,28.4665409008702));
#1892=CARTESIAN_POINT('',(55.8272124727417,-5.23109409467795,28.379700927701));
#1893=CARTESIAN_POINT('',(58.9578482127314,-5.13989456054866,28.1913666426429));
#1894=CARTESIAN_POINT('',(60.5228551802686,-5.09430385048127,28.0898699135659));
#1895=CARTESIAN_POINT('',(62.0873568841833,-5.04872785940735,27.9810421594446));
#1896=B_SPLINE_CURVE_WITH_KNOTS('',3,(#1880,#1881,#1882,#1883,#1884,#1885,#1886,#1887,#1888,
#1889,#1890,#1891,#1892,#1893,#1894,#1895),.UNSPECIFIED.,.F.,.F.,(4,2,2,2,2,2,2,4),(0.,
3.3404827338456,6.68096950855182,13.3620269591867,20.0399522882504,26.7177746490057,
31.4238050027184,36.1306123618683),.UNSPECIFIED.);
#1897=EDGE_CURVE('E211',#1848,#1167,#1896,.T.);
#1898=ORIENTED_EDGE('',*,*,#1897,.F.);
#1899=EDGE_LOOP('',(#1873,#1874,#1875,#1876,#1877,#1878,#1879,#1898));
#1900=FACE_BOUND('',#1899,.T.);
#1901=ADVANCED_FACE('F227',(#1900),#1872,.F.);
#1902=CARTESIAN_POINT('',(0.,0.,-470.799999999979));
#1903=DIRECTION('',(0.,0.,-1.));
#1904=DIRECTION('',(0.,1.,0.));
#1905=AXIS2_PLACEMENT_3D('',#1902,#1903,#1904);
#1906=DEGENERATE_TOROIDAL_SURFACE('',#1905,27.3999999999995,499.999999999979,.T.);
#1907=ORIENTED_EDGE('',*,*,#1897,.T.);
#1908=ORIENTED_EDGE('',*,*,#1168,.F.);
#1909=ORIENTED_EDGE('',*,*,#1591,.T.);
#1910=ORIENTED_EDGE('',*,*,#871,.F.);
#1911=ORIENTED_EDGE('',*,*,#1632,.T.);
#1912=ORIENTED_EDGE('',*,*,#1662,.T.);
#1913=ORIENTED_EDGE('',*,*,#1709,.T.);
#1914=ORIENTED_EDGE('',*,*,#1743,.T.);
#1915=ORIENTED_EDGE('',*,*,#33,.T.);
#1916=ORIENTED_EDGE('',*,*,#1783,.T.);
#1917=ORIENTED_EDGE('',*,*,#1831,.T.);
#1918=ORIENTED_EDGE('',*,*,#1862,.T.);
#1919=EDGE_LOOP('',(#1907,#1908,#1909,#1910,#1911,#1912,#1913,#1914,#1915,#1916,#1917,#1918));
#1920=FACE_BOUND('',#1919,.T.);
#1921=ADVANCED_FACE('F230',(#1920),#1906,.T.);
#1922=CARTESIAN_POINT('',(0.,0.,12.));
#1923=DIRECTION('',(0.,0.,-1.));
#1924=DIRECTION('',(0.,1.,0.));
#1925=AXIS2_PLACEMENT_3D('',#1922,#1923,#1924);
#1926=PLANE('',#1925);
#1927=CARTESIAN_POINT('',(0.,0.,12.));
#1928=DIRECTION('',(0.,0.,-1.));
#1929=DIRECTION('',(0.,1.,0.));
#1930=AXIS2_PLACEMENT_3D('',#1927,#1928,#1929);
#1931=CIRCLE('',#1930,4.);
#1932=CARTESIAN_POINT('',(0.,4.,12.));
#1933=VERTEX_POINT('',#1932);
#1934=EDGE_CURVE('E185',#1933,#1933,#1931,.T.);
#1935=ORIENTED_EDGE('',*,*,#1934,.T.);
#1936=EDGE_LOOP('',(#1935));
#1937=FACE_BOUND('',#1936,.T.);
#1938=ADVANCED_FACE('F234',(#1937),#1926,.T.);
#1939=CARTESIAN_POINT('',(0.,0.,12.));
#1940=DIRECTION('',(0.,0.,-1.));
#1941=DIRECTION('',(0.,1.,0.));
#1942=AXIS2_PLACEMENT_3D('',#1939,#1940,#1941);
#1943=CYLINDRICAL_SURFACE('',#1942,4.);
#1944=CARTESIAN_POINT('',(0.,0.,0.5));
#1945=DIRECTION('',(0.,0.,1.));
#1946=DIRECTION('',(0.,-1.,0.));
#1947=AXIS2_PLACEMENT_3D('',#1944,#1945,#1946);
#1948=CIRCLE('',#1947,4.);
#1949=CARTESIAN_POINT('',(0.,-4.,0.5));
#1950=VERTEX_POINT('',#1949);
#1951=EDGE_CURVE('E219',#1950,#1950,#1948,.F.);
#1952=ORIENTED_EDGE('',*,*,#1951,.T.);
#1953=EDGE_LOOP('',(#1952));
#1954=FACE_BOUND('',#1953,.T.);
#1955=ORIENTED_EDGE('',*,*,#1934,.F.);
#1956=EDGE_LOOP('',(#1955));
#1957=FACE_BOUND('',#1956,.T.);
#1958=ADVANCED_FACE('F506',(#1954,#1957),#1943,.F.);
#1959=CARTESIAN_POINT('',(0.,0.,0.5));
#1960=DIRECTION('',(0.,0.,-1.));
#1961=DIRECTION('',(0.,1.,0.));
#1962=AXIS2_PLACEMENT_3D('',#1959,#1960,#1961);
#1963=CONICAL_SURFACE('',#1962,4.,0.785398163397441);
#1964=ORIENTED_EDGE('',*,*,#176,.F.);
#1965=EDGE_LOOP('',(#1964));
#1966=FACE_BOUND('',#1965,.T.);
#1967=ORIENTED_EDGE('',*,*,#1951,.F.);
#1968=EDGE_LOOP('',(#1967));
#1969=FACE_BOUND('',#1968,.T.);
#1970=ADVANCED_FACE('F16',(#1966,#1969),#1963,.F.);
#1971=CARTESIAN_POINT('',(0.,0.,25.5));
#1972=DIRECTION('',(0.,0.,-1.));
#1973=DIRECTION('',(-1.,0.,0.));
#1974=AXIS2_PLACEMENT_3D('',#1971,#1972,#1973);
#1975=PLANE('',#1974);
#1976=ORIENTED_EDGE('',*,*,#159,.T.);
#1977=EDGE_LOOP('',(#1976));
#1978=FACE_BOUND('',#1977,.T.);
#1979=CARTESIAN_POINT('',(0.,0.,25.5));
#1980=DIRECTION('',(0.,0.,1.));
#1981=DIRECTION('',(0.,1.,0.));
#1982=AXIS2_PLACEMENT_3D('',#1979,#1980,#1981);
#1983=CIRCLE('',#1982,3.7);
#1984=CARTESIAN_POINT('',(0.,3.7,25.5));
#1985=VERTEX_POINT('',#1984);
#1986=EDGE_CURVE('E514',#1985,#1985,#1983,.F.);
#1987=ORIENTED_EDGE('',*,*,#1986,.T.);
#1988=EDGE_LOOP('',(#1987));
#1989=FACE_BOUND('',#1988,.T.);
#1990=ADVANCED_FACE('F505',(#1978,#1989),#1975,.F.);
#1991=CARTESIAN_POINT('',(-1.60878559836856,0.412500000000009,25.5));
#1992=DIRECTION('',(0.,0.,1.));
#1993=DIRECTION('',(0.,-1.,0.));
#1994=AXIS2_PLACEMENT_3D('',#1991,#1992,#1993);
#1995=PLANE('',#1994);
#1996=CARTESIAN_POINT('',(-0.894314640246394,1.54899839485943,25.5));
#1997=DIRECTION('',(0.,0.,-1.));
#1998=DIRECTION('',(0.,1.,0.));
#1999=AXIS2_PLACEMENT_3D('',#1996,#1997,#1998);
#2000=CIRCLE('',#1999,0.6);
#2001=CARTESIAN_POINT('',(-0.298104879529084,1.61633279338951,25.5));
#2002=VERTEX_POINT('',#2001);
#2003=CARTESIAN_POINT('',(-1.25073281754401,1.06633279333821,25.5));
#2004=VERTEX_POINT('',#2003);
#2005=EDGE_CURVE('E457',#2002,#2004,#2000,.T.);
#2006=ORIENTED_EDGE('',*,*,#2005,.T.);
#2007=CARTESIAN_POINT('',(-1.42894191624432,0.825,25.5));
#2008=DIRECTION('',(0.,0.,-1.));
#2009=DIRECTION('',(0.,1.,0.));
#2010=AXIS2_PLACEMENT_3D('',#2007,#2008,#2009);
#2011=CIRCLE('',#2010,0.3);
#2012=CARTESIAN_POINT('',(-1.54883770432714,0.550000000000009,25.5));
#2013=VERTEX_POINT('',#2012);
#2014=EDGE_CURVE('E454',#2004,#2013,#2011,.F.);
#2015=ORIENTED_EDGE('',*,*,#2014,.T.);
#2016=CARTESIAN_POINT('',(-1.78862928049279,0.,25.5));
#2017=DIRECTION('',(0.,0.,-1.));
#2018=DIRECTION('',(0.,1.,0.));
#2019=AXIS2_PLACEMENT_3D('',#2016,#2017,#2018);
#2020=CIRCLE('',#2019,0.6);
#2021=CARTESIAN_POINT('',(-1.54883769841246,-0.549999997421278,25.5));
#2022=VERTEX_POINT('',#2021);
#2023=EDGE_CURVE('E448',#2022,#2013,#2020,.F.);
#2024=ORIENTED_EDGE('',*,*,#2023,.F.);
#2025=CARTESIAN_POINT('',(-1.42894191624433,-0.825,25.5));
#2026=DIRECTION('',(0.,0.,-1.));
#2027=DIRECTION('',(0.,1.,0.));
#2028=AXIS2_PLACEMENT_3D('',#2025,#2026,#2027);
#2029=CIRCLE('',#2028,0.3);
#2030=CARTESIAN_POINT('',(-1.25073282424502,-1.06633279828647,25.5));
#2031=VERTEX_POINT('',#2030);
#2032=EDGE_CURVE('E460',#2022,#2031,#2029,.F.);
#2033=ORIENTED_EDGE('',*,*,#2032,.T.);
#2034=CARTESIAN_POINT('',(-0.894314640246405,-1.54899839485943,25.5));
#2035=DIRECTION('',(0.,0.,-1.));
#2036=DIRECTION('',(0.,1.,0.));
#2037=AXIS2_PLACEMENT_3D('',#2034,#2035,#2036);
#2038=CIRCLE('',#2037,0.6);
#2039=CARTESIAN_POINT('',(-0.29810487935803,-1.61633279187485,25.5));
#2040=VERTEX_POINT('',#2039);
#2041=EDGE_CURVE('E469',#2040,#2031,#2038,.F.);
#2042=ORIENTED_EDGE('',*,*,#2041,.F.);
#2043=CARTESIAN_POINT('',(0.,-1.65,25.5));
#2044=DIRECTION('',(0.,0.,-1.));
#2045=DIRECTION('',(0.,1.,0.));
#2046=AXIS2_PLACEMENT_3D('',#2043,#2044,#2045);
#2047=CIRCLE('',#2046,0.3);
#2048=CARTESIAN_POINT('',(0.29810488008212,-1.61633279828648,25.5));
#2049=VERTEX_POINT('',#2048);
#2050=EDGE_CURVE('E483',#2040,#2049,#2047,.F.);
#2051=ORIENTED_EDGE('',*,*,#2050,.T.);
#2052=CARTESIAN_POINT('',(0.89431464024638,-1.54899839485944,25.5));
#2053=DIRECTION('',(0.,0.,-1.));
#2054=DIRECTION('',(0.,1.,0.));
#2055=AXIS2_PLACEMENT_3D('',#2052,#2053,#2054);
#2056=CIRCLE('',#2055,0.6);
#2057=CARTESIAN_POINT('',(1.25073281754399,-1.06633279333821,25.5));
#2058=VERTEX_POINT('',#2057);
#2059=EDGE_CURVE('E490',#2058,#2049,#2056,.F.);
#2060=ORIENTED_EDGE('',*,*,#2059,.F.);
#2061=CARTESIAN_POINT('',(1.42894191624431,-0.825,25.5));
#2062=DIRECTION('',(0.,0.,-1.));
#2063=DIRECTION('',(0.,1.,0.));
#2064=AXIS2_PLACEMENT_3D('',#2061,#2062,#2063);
#2065=CIRCLE('',#2064,0.3);
#2066=CARTESIAN_POINT('',(1.54883770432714,-0.55,25.5));
#2067=VERTEX_POINT('',#2066);
#2068=EDGE_CURVE('E210',#2058,#2067,#2065,.F.);
#2069=ORIENTED_EDGE('',*,*,#2068,.T.);
#2070=CARTESIAN_POINT('',(1.78862928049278,0.,25.5));
#2071=DIRECTION('',(0.,0.,-1.));
#2072=DIRECTION('',(0.,1.,0.));
#2073=AXIS2_PLACEMENT_3D('',#2070,#2071,#2072);
#2074=CIRCLE('',#2073,0.6);
#2075=CARTESIAN_POINT('',(1.54883769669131,0.54999999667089,25.5));
#2076=VERTEX_POINT('',#2075);
#2077=EDGE_CURVE('E184',#2076,#2067,#2074,.F.);
#2078=ORIENTED_EDGE('',*,*,#2077,.F.);
#2079=CARTESIAN_POINT('',(1.42894191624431,0.825,25.5));
#2080=DIRECTION('',(0.,0.,-1.));
#2081=DIRECTION('',(0.,1.,0.));
#2082=AXIS2_PLACEMENT_3D('',#2079,#2080,#2081);
#2083=CIRCLE('',#2082,0.3);
#2084=CARTESIAN_POINT('',(1.25073282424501,1.06633279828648,25.5));
#2085=VERTEX_POINT('',#2084);
#2086=EDGE_CURVE('E198',#2076,#2085,#2083,.F.);
#2087=ORIENTED_EDGE('',*,*,#2086,.T.);
#2088=CARTESIAN_POINT('',(0.894314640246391,1.54899839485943,25.5));
#2089=DIRECTION('',(0.,0.,-1.));
#2090=DIRECTION('',(0.,1.,0.));
#2091=AXIS2_PLACEMENT_3D('',#2088,#2089,#2090);
#2092=CIRCLE('',#2091,0.6);
#2093=CARTESIAN_POINT('',(0.298104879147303,1.6163327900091,25.5));
#2094=VERTEX_POINT('',#2093);
#2095=EDGE_CURVE('E486',#2094,#2085,#2092,.F.);
#2096=ORIENTED_EDGE('',*,*,#2095,.F.);
#2097=CARTESIAN_POINT('',(0.,1.65,25.5));
#2098=DIRECTION('',(0.,0.,-1.));
#2099=DIRECTION('',(0.,1.,0.));
#2100=AXIS2_PLACEMENT_3D('',#2097,#2098,#2099);
#2101=CIRCLE('',#2100,0.3);
#2102=EDGE_CURVE('E477',#2094,#2002,#2101,.F.);
#2103=ORIENTED_EDGE('',*,*,#2102,.T.);
#2104=EDGE_LOOP('',(#2006,#2015,#2024,#2033,#2042,#2051,#2060,#2069,#2078,#2087,#2096,#2103));
#2105=FACE_BOUND('',#2104,.T.);
#2106=ADVANCED_FACE('F717',(#2105),#1995,.T.);
#2107=CARTESIAN_POINT('',(-1.78862928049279,0.,25.5));
#2108=DIRECTION('',(0.,0.,-1.));
#2109=DIRECTION('',(0.,1.,0.));
#2110=AXIS2_PLACEMENT_3D('',#2107,#2108,#2109);
#2111=CYLINDRICAL_SURFACE('',#2110,0.6);
#2112=ORIENTED_EDGE('',*,*,#2023,.T.);
#2113=DIRECTION('',(0.,0.,-1.));
#2114=VECTOR('',#2113,1.);
#2115=CARTESIAN_POINT('',(-1.54883770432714,0.55000000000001,25.5));
#2116=LINE('',#2115,#2114);
#2117=CARTESIAN_POINT('',(-1.54883770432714,0.550000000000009,28.5));
#2118=VERTEX_POINT('',#2117);
#2119=EDGE_CURVE('E447',#2013,#2118,#2116,.F.);
#2120=ORIENTED_EDGE('',*,*,#2119,.T.);
#2121=CARTESIAN_POINT('',(-1.78862928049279,0.,28.5));
#2122=DIRECTION('',(0.,0.,-1.));
#2123=DIRECTION('',(0.,1.,0.));
#2124=AXIS2_PLACEMENT_3D('',#2121,#2122,#2123);
#2125=CIRCLE('',#2124,0.6);
#2126=CARTESIAN_POINT('',(-1.54883769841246,-0.549999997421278,28.5));
#2127=VERTEX_POINT('',#2126);
#2128=EDGE_CURVE('E443',#2118,#2127,#2125,.T.);
#2129=ORIENTED_EDGE('',*,*,#2128,.T.);
#2130=DIRECTION('',(0.,0.,-1.));
#2131=VECTOR('',#2130,1.);
#2132=CARTESIAN_POINT('',(-1.54883769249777,-0.549999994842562,25.5));
#2133=LINE('',#2132,#2131);
#2134=EDGE_CURVE('E451',#2127,#2022,#2133,.T.);
#2135=ORIENTED_EDGE('',*,*,#2134,.T.);
#2136=EDGE_LOOP('',(#2112,#2120,#2129,#2135));
#2137=FACE_BOUND('',#2136,.T.);
#2138=ADVANCED_FACE('F721',(#2137),#2111,.T.);
#2139=CARTESIAN_POINT('',(-1.42894191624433,-0.825,25.5));
#2140=DIRECTION('',(0.,0.,-1.));
#2141=DIRECTION('',(0.,1.,0.));
#2142=AXIS2_PLACEMENT_3D('',#2139,#2140,#2141);
#2143=CYLINDRICAL_SURFACE('',#2142,0.3);
#2144=DIRECTION('',(0.,0.,-1.));
#2145=VECTOR('',#2144,1.);
#2146=CARTESIAN_POINT('',(-1.25073282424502,-1.06633279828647,25.5));
#2147=LINE('',#2146,#2145);
#2148=CARTESIAN_POINT('',(-1.25073282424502,-1.06633279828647,28.5));
#2149=VERTEX_POINT('',#2148);
#2150=EDGE_CURVE('E465',#2031,#2149,#2147,.F.);
#2151=ORIENTED_EDGE('',*,*,#2150,.F.);
#2152=ORIENTED_EDGE('',*,*,#2032,.F.);
#2153=ORIENTED_EDGE('',*,*,#2134,.F.);
#2154=CARTESIAN_POINT('',(-1.42894191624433,-0.825,28.5));
#2155=DIRECTION('',(0.,0.,-1.));
#2156=DIRECTION('',(0.,1.,0.));
#2157=AXIS2_PLACEMENT_3D('',#2154,#2155,#2156);
#2158=CIRCLE('',#2157,0.3);
#2159=EDGE_CURVE('E463',#2149,#2127,#2158,.T.);
#2160=ORIENTED_EDGE('',*,*,#2159,.F.);
#2161=EDGE_LOOP('',(#2151,#2152,#2153,#2160));
#2162=FACE_BOUND('',#2161,.T.);
#2163=ADVANCED_FACE('F769',(#2162),#2143,.F.);
#2164=CARTESIAN_POINT('',(-0.894314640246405,-1.54899839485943,25.5));
#2165=DIRECTION('',(0.,0.,-1.));
#2166=DIRECTION('',(0.,1.,0.));
#2167=AXIS2_PLACEMENT_3D('',#2164,#2165,#2166);
#2168=CYLINDRICAL_SURFACE('',#2167,0.6);
#2169=ORIENTED_EDGE('',*,*,#2041,.T.);
#2170=ORIENTED_EDGE('',*,*,#2150,.T.);
#2171=CARTESIAN_POINT('',(-0.894314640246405,-1.54899839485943,28.5));
#2172=DIRECTION('',(0.,0.,-1.));
#2173=DIRECTION('',(0.,1.,0.));
#2174=AXIS2_PLACEMENT_3D('',#2171,#2172,#2173);
#2175=CIRCLE('',#2174,0.6);
#2176=CARTESIAN_POINT('',(-0.29810487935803,-1.61633279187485,28.5));
#2177=VERTEX_POINT('',#2176);
#2178=EDGE_CURVE('E472',#2149,#2177,#2175,.T.);
#2179=ORIENTED_EDGE('',*,*,#2178,.T.);
#2180=DIRECTION('',(0.,0.,-1.));
#2181=VECTOR('',#2180,1.);
#2182=CARTESIAN_POINT('',(-0.29810487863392,-1.61633278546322,25.5));
#2183=LINE('',#2182,#2181);
#2184=EDGE_CURVE('E471',#2177,#2040,#2183,.T.);
#2185=ORIENTED_EDGE('',*,*,#2184,.T.);
#2186=EDGE_LOOP('',(#2169,#2170,#2179,#2185));
#2187=FACE_BOUND('',#2186,.T.);
#2188=ADVANCED_FACE('F780',(#2187),#2168,.T.);
#2189=CARTESIAN_POINT('',(0.,-1.65,25.5));
#2190=DIRECTION('',(0.,0.,-1.));
#2191=DIRECTION('',(0.,1.,0.));
#2192=AXIS2_PLACEMENT_3D('',#2189,#2190,#2191);
#2193=CYLINDRICAL_SURFACE('',#2192,0.3);
#2194=DIRECTION('',(0.,0.,-1.));
#2195=VECTOR('',#2194,1.);
#2196=CARTESIAN_POINT('',(0.29810488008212,-1.61633279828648,25.5));
#2197=LINE('',#2196,#2195);
#2198=CARTESIAN_POINT('',(0.29810488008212,-1.61633279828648,28.5));
#2199=VERTEX_POINT('',#2198);
#2200=EDGE_CURVE('E482',#2049,#2199,#2197,.F.);
#2201=ORIENTED_EDGE('',*,*,#2200,.F.);
#2202=ORIENTED_EDGE('',*,*,#2050,.F.);
#2203=ORIENTED_EDGE('',*,*,#2184,.F.);
#2204=CARTESIAN_POINT('',(0.,-1.65,28.5));
#2205=DIRECTION('',(0.,0.,-1.));
#2206=DIRECTION('',(0.,1.,0.));
#2207=AXIS2_PLACEMENT_3D('',#2204,#2205,#2206);
#2208=CIRCLE('',#2207,0.3);
#2209=EDGE_CURVE('E480',#2199,#2177,#2208,.T.);
#2210=ORIENTED_EDGE('',*,*,#2209,.F.);
#2211=EDGE_LOOP('',(#2201,#2202,#2203,#2210));
#2212=FACE_BOUND('',#2211,.T.);
#2213=ADVANCED_FACE('F791',(#2212),#2193,.F.);
#2214=CARTESIAN_POINT('',(0.89431464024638,-1.54899839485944,25.5));
#2215=DIRECTION('',(0.,0.,-1.));
#2216=DIRECTION('',(0.,1.,0.));
#2217=AXIS2_PLACEMENT_3D('',#2214,#2215,#2216);
#2218=CYLINDRICAL_SURFACE('',#2217,0.6);
#2219=ORIENTED_EDGE('',*,*,#2059,.T.);
#2220=ORIENTED_EDGE('',*,*,#2200,.T.);
#2221=CARTESIAN_POINT('',(0.89431464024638,-1.54899839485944,28.5));
#2222=DIRECTION('',(0.,0.,-1.));
#2223=DIRECTION('',(0.,1.,0.));
#2224=AXIS2_PLACEMENT_3D('',#2221,#2222,#2223);
#2225=CIRCLE('',#2224,0.6);
#2226=CARTESIAN_POINT('',(1.25073281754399,-1.06633279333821,28.5));
#2227=VERTEX_POINT('',#2226);
#2228=EDGE_CURVE('E197',#2199,#2227,#2225,.T.);
#2229=ORIENTED_EDGE('',*,*,#2228,.T.);
#2230=DIRECTION('',(0.,0.,-1.));
#2231=VECTOR('',#2230,1.);
#2232=CARTESIAN_POINT('',(1.25073281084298,-1.06633278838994,25.5));
#2233=LINE('',#2232,#2231);
#2234=EDGE_CURVE('E207',#2227,#2058,#2233,.T.);
#2235=ORIENTED_EDGE('',*,*,#2234,.T.);
#2236=EDGE_LOOP('',(#2219,#2220,#2229,#2235));
#2237=FACE_BOUND('',#2236,.T.);
#2238=ADVANCED_FACE('F802',(#2237),#2218,.T.);
#2239=CARTESIAN_POINT('',(1.42894191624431,-0.825,25.5));
#2240=DIRECTION('',(0.,0.,-1.));
#2241=DIRECTION('',(0.,1.,0.));
#2242=AXIS2_PLACEMENT_3D('',#2239,#2240,#2241);
#2243=CYLINDRICAL_SURFACE('',#2242,0.3);
#2244=DIRECTION('',(0.,0.,-1.));
#2245=VECTOR('',#2244,1.);
#2246=CARTESIAN_POINT('',(1.54883770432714,-0.55,25.5));
#2247=LINE('',#2246,#2245);
#2248=CARTESIAN_POINT('',(1.54883770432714,-0.55,28.5));
#2249=VERTEX_POINT('',#2248);
#2250=EDGE_CURVE('E182',#2067,#2249,#2247,.F.);
#2251=ORIENTED_EDGE('',*,*,#2250,.F.);
#2252=ORIENTED_EDGE('',*,*,#2068,.F.);
#2253=ORIENTED_EDGE('',*,*,#2234,.F.);
#2254=CARTESIAN_POINT('',(1.42894191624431,-0.825,28.5));
#2255=DIRECTION('',(0.,0.,-1.));
#2256=DIRECTION('',(0.,1.,0.));
#2257=AXIS2_PLACEMENT_3D('',#2254,#2255,#2256);
#2258=CIRCLE('',#2257,0.3);
#2259=EDGE_CURVE('E201',#2249,#2227,#2258,.T.);
#2260=ORIENTED_EDGE('',*,*,#2259,.F.);
#2261=EDGE_LOOP('',(#2251,#2252,#2253,#2260));
#2262=FACE_BOUND('',#2261,.T.);
#2263=ADVANCED_FACE('F813',(#2262),#2243,.F.);
#2264=CARTESIAN_POINT('',(1.78862928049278,0.,25.5));
#2265=DIRECTION('',(0.,0.,-1.));
#2266=DIRECTION('',(0.,1.,0.));
#2267=AXIS2_PLACEMENT_3D('',#2264,#2265,#2266);
#2268=CYLINDRICAL_SURFACE('',#2267,0.6);
#2269=ORIENTED_EDGE('',*,*,#2077,.T.);
#2270=ORIENTED_EDGE('',*,*,#2250,.T.);
#2271=CARTESIAN_POINT('',(1.78862928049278,0.,28.5));
#2272=DIRECTION('',(0.,0.,-1.));
#2273=DIRECTION('',(0.,1.,0.));
#2274=AXIS2_PLACEMENT_3D('',#2271,#2272,#2273);
#2275=CIRCLE('',#2274,0.6);
#2276=CARTESIAN_POINT('',(1.54883769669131,0.54999999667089,28.5));
#2277=VERTEX_POINT('',#2276);
#2278=EDGE_CURVE('E172',#2249,#2277,#2275,.T.);
#2279=ORIENTED_EDGE('',*,*,#2278,.T.);
#2280=DIRECTION('',(0.,0.,-1.));
#2281=VECTOR('',#2280,1.);
#2282=CARTESIAN_POINT('',(1.54883768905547,0.549999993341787,25.5));
#2283=LINE('',#2282,#2281);
#2284=EDGE_CURVE('E179',#2277,#2076,#2283,.T.);
#2285=ORIENTED_EDGE('',*,*,#2284,.T.);
#2286=EDGE_LOOP('',(#2269,#2270,#2279,#2285));
#2287=FACE_BOUND('',#2286,.T.);
#2288=ADVANCED_FACE('F177',(#2287),#2268,.T.);
#2289=CARTESIAN_POINT('',(1.42894191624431,0.825,25.5));
#2290=DIRECTION('',(0.,0.,-1.));
#2291=DIRECTION('',(0.,1.,0.));
#2292=AXIS2_PLACEMENT_3D('',#2289,#2290,#2291);
#2293=CYLINDRICAL_SURFACE('',#2292,0.3);
#2294=DIRECTION('',(0.,0.,-1.));
#2295=VECTOR('',#2294,1.);
#2296=CARTESIAN_POINT('',(1.25073282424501,1.06633279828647,25.5));
#2297=LINE('',#2296,#2295);
#2298=CARTESIAN_POINT('',(1.25073282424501,1.06633279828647,28.5));
#2299=VERTEX_POINT('',#2298);
#2300=EDGE_CURVE('E485',#2085,#2299,#2297,.F.);
#2301=ORIENTED_EDGE('',*,*,#2300,.F.);
#2302=ORIENTED_EDGE('',*,*,#2086,.F.);
#2303=ORIENTED_EDGE('',*,*,#2284,.F.);
#2304=CARTESIAN_POINT('',(1.42894191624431,0.825,28.5));
#2305=DIRECTION('',(0.,0.,-1.));
#2306=DIRECTION('',(0.,1.,0.));
#2307=AXIS2_PLACEMENT_3D('',#2304,#2305,#2306);
#2308=CIRCLE('',#2307,0.3);
#2309=EDGE_CURVE('E188',#2299,#2277,#2308,.T.);
#2310=ORIENTED_EDGE('',*,*,#2309,.F.);
#2311=EDGE_LOOP('',(#2301,#2302,#2303,#2310));
#2312=FACE_BOUND('',#2311,.T.);
#2313=ADVANCED_FACE('F200',(#2312),#2293,.F.);
#2314=CARTESIAN_POINT('',(0.894314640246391,1.54899839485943,25.5));
#2315=DIRECTION('',(0.,0.,-1.));
#2316=DIRECTION('',(0.,1.,0.));
#2317=AXIS2_PLACEMENT_3D('',#2314,#2315,#2316);
#2318=CYLINDRICAL_SURFACE('',#2317,0.6);
#2319=ORIENTED_EDGE('',*,*,#2095,.T.);
#2320=ORIENTED_EDGE('',*,*,#2300,.T.);
#2321=CARTESIAN_POINT('',(0.894314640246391,1.54899839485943,28.5));
#2322=DIRECTION('',(0.,0.,-1.));
#2323=DIRECTION('',(0.,1.,0.));
#2324=AXIS2_PLACEMENT_3D('',#2321,#2322,#2323);
#2325=CIRCLE('',#2324,0.6);
#2326=CARTESIAN_POINT('',(0.298104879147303,1.6163327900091,28.5));
#2327=VERTEX_POINT('',#2326);
#2328=EDGE_CURVE('E193',#2299,#2327,#2325,.T.);
#2329=ORIENTED_EDGE('',*,*,#2328,.T.);
#2330=DIRECTION('',(0.,0.,-1.));
#2331=VECTOR('',#2330,1.);
#2332=CARTESIAN_POINT('',(0.298104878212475,1.61633278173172,25.5));
#2333=LINE('',#2332,#2331);
#2334=EDGE_CURVE('E479',#2327,#2094,#2333,.T.);
#2335=ORIENTED_EDGE('',*,*,#2334,.T.);
#2336=EDGE_LOOP('',(#2319,#2320,#2329,#2335));
#2337=FACE_BOUND('',#2336,.T.);
#2338=ADVANCED_FACE('F840',(#2337),#2318,.T.);
#2339=CARTESIAN_POINT('',(0.,1.65,25.5));
#2340=DIRECTION('',(0.,0.,-1.));
#2341=DIRECTION('',(0.,1.,0.));
#2342=AXIS2_PLACEMENT_3D('',#2339,#2340,#2341);
#2343=CYLINDRICAL_SURFACE('',#2342,0.3);
#2344=DIRECTION('',(0.,0.,-1.));
#2345=VECTOR('',#2344,1.);
#2346=CARTESIAN_POINT('',(-0.298104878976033,1.61633278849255,25.5));
#2347=LINE('',#2346,#2345);
#2348=CARTESIAN_POINT('',(-0.298104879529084,1.61633279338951,28.5));
#2349=VERTEX_POINT('',#2348);
#2350=EDGE_CURVE('E468',#2002,#2349,#2347,.F.);
#2351=ORIENTED_EDGE('',*,*,#2350,.F.);
#2352=ORIENTED_EDGE('',*,*,#2102,.F.);
#2353=ORIENTED_EDGE('',*,*,#2334,.F.);
#2354=CARTESIAN_POINT('',(0.,1.65,28.5));
#2355=DIRECTION('',(0.,0.,-1.));
#2356=DIRECTION('',(0.,1.,0.));
#2357=AXIS2_PLACEMENT_3D('',#2354,#2355,#2356);
#2358=CIRCLE('',#2357,0.3);
#2359=EDGE_CURVE('E475',#2349,#2327,#2358,.T.);
#2360=ORIENTED_EDGE('',*,*,#2359,.F.);
#2361=EDGE_LOOP('',(#2351,#2352,#2353,#2360));
#2362=FACE_BOUND('',#2361,.T.);
#2363=ADVANCED_FACE('F848',(#2362),#2343,.F.);
#2364=CARTESIAN_POINT('',(-0.894314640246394,1.54899839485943,25.5));
#2365=DIRECTION('',(0.,0.,-1.));
#2366=DIRECTION('',(0.,1.,0.));
#2367=AXIS2_PLACEMENT_3D('',#2364,#2365,#2366);
#2368=CYLINDRICAL_SURFACE('',#2367,0.6);
#2369=ORIENTED_EDGE('',*,*,#2005,.F.);
#2370=ORIENTED_EDGE('',*,*,#2350,.T.);
#2371=CARTESIAN_POINT('',(-0.894314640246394,1.54899839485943,28.5));
#2372=DIRECTION('',(0.,0.,-1.));
#2373=DIRECTION('',(0.,1.,0.));
#2374=AXIS2_PLACEMENT_3D('',#2371,#2372,#2373);
#2375=CIRCLE('',#2374,0.6);
#2376=CARTESIAN_POINT('',(-1.25073281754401,1.06633279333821,28.5));
#2377=VERTEX_POINT('',#2376);
#2378=EDGE_CURVE('E466',#2349,#2377,#2375,.T.);
#2379=ORIENTED_EDGE('',*,*,#2378,.T.);
#2380=DIRECTION('',(0.,0.,-1.));
#2381=VECTOR('',#2380,1.);
#2382=CARTESIAN_POINT('',(-1.250732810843,1.06633278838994,25.5));
#2383=LINE('',#2382,#2381);
#2384=EDGE_CURVE('E456',#2377,#2004,#2383,.T.);
#2385=ORIENTED_EDGE('',*,*,#2384,.T.);
#2386=EDGE_LOOP('',(#2369,#2370,#2379,#2385));
#2387=FACE_BOUND('',#2386,.T.);
#2388=ADVANCED_FACE('F857',(#2387),#2368,.T.);
#2389=CARTESIAN_POINT('',(-1.42894191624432,0.825,25.5));
#2390=DIRECTION('',(0.,0.,-1.));
#2391=DIRECTION('',(0.,1.,0.));
#2392=AXIS2_PLACEMENT_3D('',#2389,#2390,#2391);
#2393=CYLINDRICAL_SURFACE('',#2392,0.3);
#2394=ORIENTED_EDGE('',*,*,#2119,.F.);
#2395=ORIENTED_EDGE('',*,*,#2014,.F.);
#2396=ORIENTED_EDGE('',*,*,#2384,.F.);
#2397=CARTESIAN_POINT('',(-1.42894191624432,0.825,28.5));
#2398=DIRECTION('',(0.,0.,-1.));
#2399=DIRECTION('',(0.,1.,0.));
#2400=AXIS2_PLACEMENT_3D('',#2397,#2398,#2399);
#2401=CIRCLE('',#2400,0.3);
#2402=EDGE_CURVE('E452',#2118,#2377,#2401,.T.);
#2403=ORIENTED_EDGE('',*,*,#2402,.F.);
#2404=EDGE_LOOP('',(#2394,#2395,#2396,#2403));
#2405=FACE_BOUND('',#2404,.T.);
#2406=ADVANCED_FACE('F866',(#2405),#2393,.F.);
#2407=CARTESIAN_POINT('',(0.,0.,28.5));
#2408=DIRECTION('',(0.,0.,-1.));
#2409=DIRECTION('',(0.,1.,0.));
#2410=AXIS2_PLACEMENT_3D('',#2407,#2408,#2409);
#2411=PLANE('',#2410);
#2412=ORIENTED_EDGE('',*,*,#2402,.T.);
#2413=ORIENTED_EDGE('',*,*,#2378,.F.);
#2414=ORIENTED_EDGE('',*,*,#2359,.T.);
#2415=ORIENTED_EDGE('',*,*,#2328,.F.);
#2416=ORIENTED_EDGE('',*,*,#2309,.T.);
#2417=ORIENTED_EDGE('',*,*,#2278,.F.);
#2418=ORIENTED_EDGE('',*,*,#2259,.T.);
#2419=ORIENTED_EDGE('',*,*,#2228,.F.);
#2420=ORIENTED_EDGE('',*,*,#2209,.T.);
#2421=ORIENTED_EDGE('',*,*,#2178,.F.);
#2422=ORIENTED_EDGE('',*,*,#2159,.T.);
#2423=ORIENTED_EDGE('',*,*,#2128,.F.);
#2424=EDGE_LOOP('',(#2412,#2413,#2414,#2415,#2416,#2417,#2418,#2419,#2420,#2421,#2422,#2423));
#2425=FACE_BOUND('',#2424,.T.);
#2426=CARTESIAN_POINT('',(0.,2.78388218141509,28.5));
#2427=CARTESIAN_POINT('',(0.156371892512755,2.78387524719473,28.5));
#2428=CARTESIAN_POINT('',(0.312857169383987,2.77066275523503,28.5));
#2429=CARTESIAN_POINT('',(0.621518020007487,2.71813885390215,28.5));
#2430=CARTESIAN_POINT('',(0.773688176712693,2.67879603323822,28.5));
#2431=CARTESIAN_POINT('',(1.06920242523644,2.57513147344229,28.5));
#2432=CARTESIAN_POINT('',(1.21255069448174,2.51082166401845,28.5));
#2433=CARTESIAN_POINT('',(1.48637567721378,2.35906503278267,28.5));
#2434=CARTESIAN_POINT('',(1.61685558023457,2.27162396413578,28.5));
#2435=CARTESIAN_POINT('',(1.86129958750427,2.07606928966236,28.5));
#2436=CARTESIAN_POINT('',(1.97526196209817,1.96795352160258,28.5));
#2437=CARTESIAN_POINT('',(2.18342227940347,1.73411959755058,28.5));
#2438=CARTESIAN_POINT('',(2.27761944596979,1.60840075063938,28.5));
#2439=CARTESIAN_POINT('',(2.44356846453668,1.34293533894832,28.5));
#2440=CARTESIAN_POINT('',(2.51532073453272,1.20318903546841,28.5));
#2441=CARTESIAN_POINT('',(2.63434528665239,0.913634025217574,28.5));
#2442=CARTESIAN_POINT('',(2.68161761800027,0.763825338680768,28.4999999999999));
#2443=CARTESIAN_POINT('',(2.75034068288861,0.458397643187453,28.5000000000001));
#2444=CARTESIAN_POINT('',(2.77179136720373,0.30277862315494,28.5000000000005));
#2445=CARTESIAN_POINT('',(2.78826202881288,-0.00985161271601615,28.4999999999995));
#2446=CARTESIAN_POINT('',(2.78328205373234,-0.166862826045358,28.499999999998));
#2447=CARTESIAN_POINT('',(2.74703286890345,-0.477820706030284,28.4999999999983));
#2448=CARTESIAN_POINT('',(2.71576364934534,-0.631767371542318,28.5));
#2449=CARTESIAN_POINT('',(2.62782355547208,-0.932226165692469,28.5));
#2450=CARTESIAN_POINT('',(2.57115265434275,-1.07873828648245,28.4999999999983));
#2451=CARTESIAN_POINT('',(2.43401793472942,-1.36016871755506,28.4999999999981));
#2452=CARTESIAN_POINT('',(2.35355412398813,-1.49508703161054,28.4999999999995));
#2453=CARTESIAN_POINT('',(2.17111774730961,-1.74949991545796,28.5000000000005));
#2454=CARTESIAN_POINT('',(2.06914519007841,-1.86899449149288,28.5000000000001));
#2455=CARTESIAN_POINT('',(1.84658598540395,-2.08916788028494,28.4999999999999));
#2456=CARTESIAN_POINT('',(1.72599933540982,-2.18984669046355,28.5));
#2457=CARTESIAN_POINT('',(1.46963503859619,-2.36953056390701,28.5));
#2458=CARTESIAN_POINT('',(1.33385738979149,-2.44853562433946,28.5));
#2459=CARTESIAN_POINT('',(1.05096544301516,-2.58262925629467,28.5));
#2460=CARTESIAN_POINT('',(0.903851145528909,-2.63771782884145,28.5));
#2461=CARTESIAN_POINT('',(0.602462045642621,-2.72241468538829,28.5));
#2462=CARTESIAN_POINT('',(0.448187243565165,-2.75202297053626,28.5));
#2463=CARTESIAN_POINT('',(0.13685653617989,-2.78491876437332,28.5));
#2464=CARTESIAN_POINT('',(-0.0201993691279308,-2.7882062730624,28.5));
#2465=CARTESIAN_POINT('',(-0.332633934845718,-2.76836719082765,28.5));
#2466=CARTESIAN_POINT('',(-0.488012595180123,-2.74524059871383,28.5));
#2467=CARTESIAN_POINT('',(-0.792681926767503,-2.67322980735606,28.5));
#2468=CARTESIAN_POINT('',(-0.941972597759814,-2.62434560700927,28.5));
#2469=CARTESIAN_POINT('',(-1.23022800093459,-2.50220728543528,28.5));
#2470=CARTESIAN_POINT('',(-1.36919273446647,-2.42895316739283,28.5));
#2471=CARTESIAN_POINT('',(-1.6328514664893,-2.26015448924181,28.5));
#2472=CARTESIAN_POINT('',(-1.75754546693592,-2.16460993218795,28.5));
#2473=CARTESIAN_POINT('',(-1.98912310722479,-1.95394255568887,28.5));
#2474=CARTESIAN_POINT('',(-2.09600673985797,-1.83881972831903,28.5));
#2475=CARTESIAN_POINT('',(-2.28892950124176,-1.59226379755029,28.5));
#2476=CARTESIAN_POINT('',(-2.37496862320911,-1.4608306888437,28.5));
#2477=CARTESIAN_POINT('',(-2.52375983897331,-1.18538537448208,28.5));
#2478=CARTESIAN_POINT('',(-2.58651195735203,-1.04137318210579,28.5));
#2479=CARTESIAN_POINT('',(-2.68694792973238,-0.744857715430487,28.5));
#2480=CARTESIAN_POINT('',(-2.72463179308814,-0.592354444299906,28.5));
#2481=CARTESIAN_POINT('',(-2.77386160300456,-0.283185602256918,28.5));
#2482=CARTESIAN_POINT('',(-2.78540750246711,-0.126520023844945,28.4999999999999));
#2483=CARTESIAN_POINT('',(-2.78203350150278,0.186525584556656,28.5000000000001));
#2484=CARTESIAN_POINT('',(-2.76711365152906,0.342905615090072,28.5000000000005));
#2485=CARTESIAN_POINT('',(-2.71123169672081,0.650941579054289,28.4999999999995));
#2486=CARTESIAN_POINT('',(-2.67026953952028,0.802597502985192,28.4999999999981));
#2487=CARTESIAN_POINT('',(-2.56346482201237,1.09688259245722,28.4999999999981));
#2488=CARTESIAN_POINT('',(-2.49762179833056,1.23951158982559,28.4999999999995));
#2489=CARTESIAN_POINT('',(-2.34292722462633,1.5116854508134,28.5000000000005));
#2490=CARTESIAN_POINT('',(-2.25407657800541,1.64123082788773,28.5000000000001));
#2491=CARTESIAN_POINT('',(-2.05589954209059,1.88355368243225,28.4999999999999));
#2492=CARTESIAN_POINT('',(-1.94657529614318,1.99633291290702,28.5));
#2493=CARTESIAN_POINT('',(-1.71051270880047,2.20196523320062,28.5));
#2494=CARTESIAN_POINT('',(-1.58377004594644,2.29481336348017,28.5));
#2495=CARTESIAN_POINT('',(-1.31644635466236,2.45794844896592,28.5));
#2496=CARTESIAN_POINT('',(-1.17585874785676,2.52822461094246,28.5));
#2497=CARTESIAN_POINT('',(-0.884990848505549,2.64409585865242,28.5));
#2498=CARTESIAN_POINT('',(-0.734722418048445,2.6897205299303,28.5));
#2499=CARTESIAN_POINT('',(-0.486246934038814,2.74283368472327,28.5));
#2500=CARTESIAN_POINT('',(-0.389654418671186,2.75820765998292,28.5));
#2501=CARTESIAN_POINT('',(-0.195389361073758,2.7787340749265,28.5));
#2502=CARTESIAN_POINT('',(-0.0977168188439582,2.78388651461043,28.5));
#2503=CARTESIAN_POINT('',(0.,2.78388218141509,28.5));
#2504=B_SPLINE_CURVE_WITH_KNOTS('',3,(#2426,#2427,#2428,#2429,#2430,#2431,#2432,#2433,#2434,
#2435,#2436,#2437,#2438,#2439,#2440,#2441,#2442,#2443,#2444,#2445,#2446,#2447,#2448,#2449,#2450,
#2451,#2452,#2453,#2454,#2455,#2456,#2457,#2458,#2459,#2460,#2461,#2462,#2463,#2464,#2465,#2466,
#2467,#2468,#2469,#2470,#2471,#2472,#2473,#2474,#2475,#2476,#2477,#2478,#2479,#2480,#2481,#2482,
#2483,#2484,#2485,#2486,#2487,#2488,#2489,#2490,#2491,#2492,#2493,#2494,#2495,#2496,#2497,#2498,
#2499,#2500,#2501,#2502,#2503),.UNSPECIFIED.,.T.,.F.,(4,2,2,2,2,2,2,2,2,2,2,2,2,2,2,2,2,2,2,2,2,
2,2,2,2,2,2,2,2,2,2,2,2,2,2,2,2,2,4),(0.,0.468759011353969,0.938082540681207,1.40718209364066,
1.8761650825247,2.34519714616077,2.81424762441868,3.2832893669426,3.75233016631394,
4.22137185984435,4.69041270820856,5.15945373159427,5.62849525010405,6.0975366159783,
6.56657779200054,7.03561903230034,7.50466033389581,7.97370161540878,8.44274287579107,
8.91178413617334,9.38082541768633,9.84986671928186,10.3189079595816,10.7879491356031,
11.2569905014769,11.7260320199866,12.1950730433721,12.6641138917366,13.1331555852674,
13.6021963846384,14.0712381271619,14.5402886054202,15.009320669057,15.4783036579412,
15.9474032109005,16.4167267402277,16.8854857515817,17.1784133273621,17.4713409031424),.UNSPECIFIED.);
#2505=CARTESIAN_POINT('',(0.,2.78388218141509,28.5));
#2506=VERTEX_POINT('',#2505);
#2507=EDGE_CURVE('E436',#2506,#2506,#2504,.T.);
#2508=ORIENTED_EDGE('',*,*,#2507,.F.);
#2509=EDGE_LOOP('',(#2508));
#2510=FACE_BOUND('',#2509,.T.);
#2511=ADVANCED_FACE('F190',(#2425,#2510),#2411,.F.);
#2512=CARTESIAN_POINT('',(0.,0.,21.));
#2513=DIRECTION('',(1.,0.,0.));
#2514=DIRECTION('',(0.,-1.,0.));
#2515=AXIS2_PLACEMENT_3D('',#2512,#2513,#2514);
#2516=SPHERICAL_SURFACE('',#2515,8.);
#2517=CARTESIAN_POINT('',(0.,0.,27.9587227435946));
#2518=DIRECTION('',(0.,0.,-1.));
#2519=DIRECTION('',(0.,1.,0.));
#2520=AXIS2_PLACEMENT_3D('',#2517,#2518,#2519);
#2521=CIRCLE('',#2520,3.94666666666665);
#2522=CARTESIAN_POINT('',(0.,3.94666666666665,27.9587227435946));
#2523=VERTEX_POINT('',#2522);
#2524=EDGE_CURVE('E417',#2523,#2523,#2521,.T.);
#2525=ORIENTED_EDGE('',*,*,#2524,.F.);
#2526=EDGE_LOOP('',(#2525));
#2527=FACE_BOUND('',#2526,.T.);
#2528=ORIENTED_EDGE('',*,*,#2507,.T.);
#2529=EDGE_LOOP('',(#2528));
#2530=FACE_BOUND('',#2529,.T.);
#2531=ADVANCED_FACE('F427',(#2527,#2530),#2516,.T.);
#2532=CARTESIAN_POINT('',(0.,0.,27.52380257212));
#2533=DIRECTION('',(0.,0.,-1.));
#2534=DIRECTION('',(0.,1.,0.));
#2535=AXIS2_PLACEMENT_3D('',#2532,#2533,#2534);
#2536=TOROIDAL_SURFACE('',#2535,3.7,0.49999999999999);
#2537=CARTESIAN_POINT('',(0.,0.,27.52380257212));
#2538=DIRECTION('',(0.,0.,1.));
#2539=DIRECTION('',(0.,-1.,0.));
#2540=AXIS2_PLACEMENT_3D('',#2537,#2538,#2539);
#2541=CIRCLE('',#2540,4.2);
#2542=CARTESIAN_POINT('',(0.,-4.2,27.52380257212));
#2543=VERTEX_POINT('',#2542);
#2544=EDGE_CURVE('E409',#2543,#2543,#2541,.F.);
#2545=ORIENTED_EDGE('',*,*,#2544,.F.);
#2546=EDGE_LOOP('',(#2545));
#2547=FACE_BOUND('',#2546,.T.);
#2548=ORIENTED_EDGE('',*,*,#2524,.T.);
#2549=EDGE_LOOP('',(#2548));
#2550=FACE_BOUND('',#2549,.T.);
#2551=ADVANCED_FACE('F424',(#2547,#2550),#2536,.T.);
#2552=CARTESIAN_POINT('',(0.,0.,19.8));
#2553=DIRECTION('',(0.,0.,1.));
#2554=DIRECTION('',(0.,-1.,0.));
#2555=AXIS2_PLACEMENT_3D('',#2552,#2553,#2554);
#2556=CYLINDRICAL_SURFACE('',#2555,4.2);
#2557=ORIENTED_EDGE('',*,*,#2544,.T.);
#2558=EDGE_LOOP('',(#2557));
#2559=FACE_BOUND('',#2558,.T.);
#2560=CARTESIAN_POINT('',(0.,0.,26.));
#2561=DIRECTION('',(0.,0.,-1.));
#2562=DIRECTION('',(0.,1.,0.));
#2563=AXIS2_PLACEMENT_3D('',#2560,#2561,#2562);
#2564=CIRCLE('',#2563,4.2);
#2565=CARTESIAN_POINT('',(0.,4.2,26.));
#2566=VERTEX_POINT('',#2565);
#2567=EDGE_CURVE('E390',#2566,#2566,#2564,.T.);
#2568=ORIENTED_EDGE('',*,*,#2567,.F.);
#2569=EDGE_LOOP('',(#2568));
#2570=FACE_BOUND('',#2569,.T.);
#2571=ADVANCED_FACE('F398',(#2559,#2570),#2556,.T.);
#2572=CARTESIAN_POINT('',(0.,0.,26.));
#2573=DIRECTION('',(0.,0.,-1.));
#2574=DIRECTION('',(0.,1.,0.));
#2575=AXIS2_PLACEMENT_3D('',#2572,#2573,#2574);
#2576=TOROIDAL_SURFACE('',#2575,3.7,0.5);
#2577=ORIENTED_EDGE('',*,*,#1986,.F.);
#2578=EDGE_LOOP('',(#2577));
#2579=FACE_BOUND('',#2578,.T.);
#2580=ORIENTED_EDGE('',*,*,#2567,.T.);
#2581=EDGE_LOOP('',(#2580));
#2582=FACE_BOUND('',#2581,.T.);
#2583=ADVANCED_FACE('F393',(#2579,#2582),#2576,.T.);
#2584=CLOSED_SHELL('',(#163,#191,#211,#231,#251,#271,#327,#369,#554,#605,#715,#775,#793,#825,
#933,#991,#1067,#1095,#1203,#1275,#1307,#1361,#1415,#1579,#1597,#1636,#1667,#1716,#1749,#1787,
#1836,#1867,#1901,#1921,#1938,#1958,#1970,#1990,#2106,#2138,#2163,#2188,#2213,#2238,#2263,#2288,
#2313,#2338,#2363,#2388,#2406,#2511,#2531,#2551,#2571,#2583));
#2585=MANIFOLD_SOLID_BREP('B1',#2584);
#2586=ADVANCED_BREP_SHAPE_REPRESENTATION('',(#18,#2585),#14);
#2587=SHAPE_DEFINITION_REPRESENTATION(#9,#2586);
ENDSEC;
END-ISO-10303-21;
